VERSION 5.8 ;
BUSBITCHARS "[]" ;
DIVIDERCHAR "/" ;
UNITS
    DATABASE MICRONS 1000 ;
END UNITS

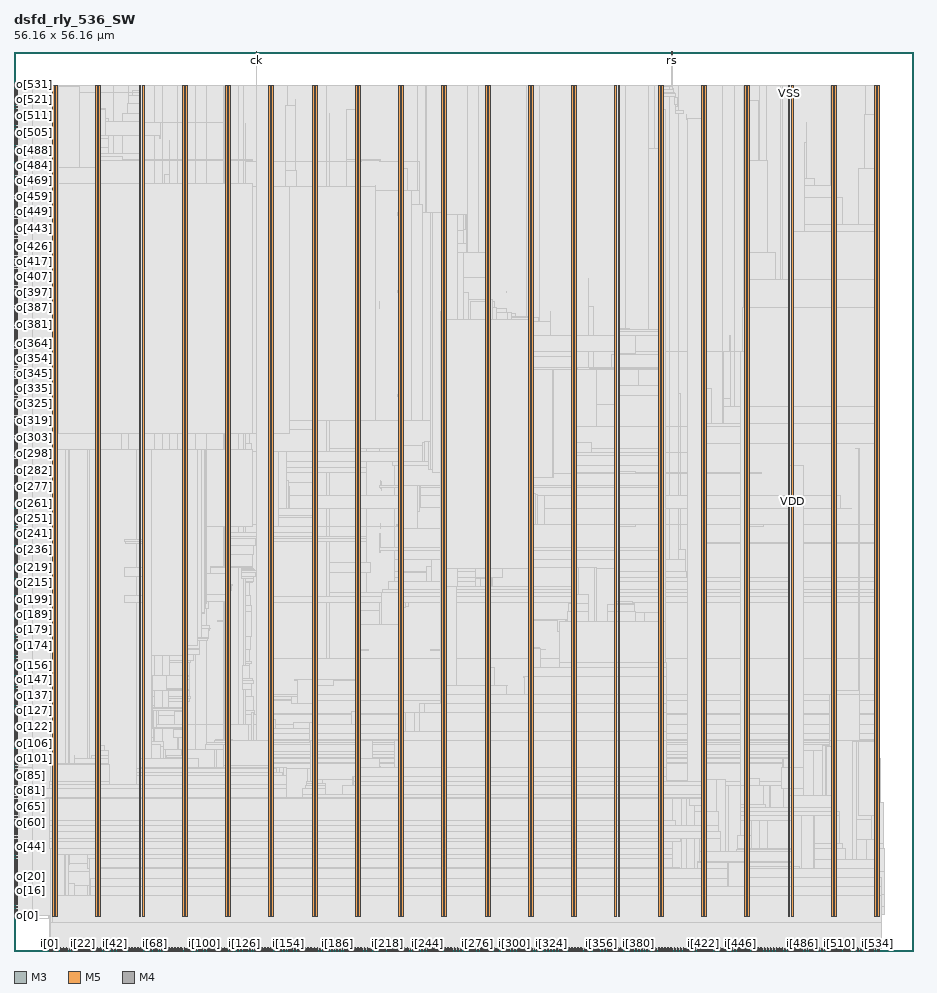
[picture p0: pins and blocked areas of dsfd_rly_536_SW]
MACRO dsfd_rly_536_SW
  FOREIGN dsfd_rly_536_SW 0 0 ;
  CLASS BLOCK ;
  SIZE 56.16 BY 56.16 ;
  PIN ck
    DIRECTION INPUT ;
    USE SIGNAL ;
    PORT
      LAYER M3 ;
        RECT  15.12 56.016 15.138 56.16 ;
    END
  END ck
  PIN i[0]
    DIRECTION INPUT ;
    USE SIGNAL ;
    PORT
      LAYER M3 ;
        RECT  2.196 0 2.214 0.144 ;
    END
  END i[0]
  PIN i[100]
    DIRECTION INPUT ;
    USE SIGNAL ;
    PORT
      LAYER M3 ;
        RECT  11.88 0 11.898 0.144 ;
    END
  END i[100]
  PIN i[101]
    DIRECTION INPUT ;
    USE SIGNAL ;
    PORT
      LAYER M5 ;
        RECT  11.952 0 11.976 0.192 ;
    END
  END i[101]
  PIN i[102]
    DIRECTION INPUT ;
    USE SIGNAL ;
    PORT
      LAYER M3 ;
        RECT  12.06 0 12.078 0.144 ;
    END
  END i[102]
  PIN i[103]
    DIRECTION INPUT ;
    USE SIGNAL ;
    PORT
      LAYER M5 ;
        RECT  12.144 0 12.168 0.192 ;
    END
  END i[103]
  PIN i[104]
    DIRECTION INPUT ;
    USE SIGNAL ;
    PORT
      LAYER M3 ;
        RECT  12.24 0 12.258 0.144 ;
    END
  END i[104]
  PIN i[105]
    DIRECTION INPUT ;
    USE SIGNAL ;
    PORT
      LAYER M5 ;
        RECT  12.336 0 12.36 0.192 ;
    END
  END i[105]
  PIN i[106]
    DIRECTION INPUT ;
    USE SIGNAL ;
    PORT
      LAYER M3 ;
        RECT  12.456 0 12.474 0.144 ;
    END
  END i[106]
  PIN i[107]
    DIRECTION INPUT ;
    USE SIGNAL ;
    PORT
      LAYER M5 ;
        RECT  12.528 0 12.552 0.192 ;
    END
  END i[107]
  PIN i[108]
    DIRECTION INPUT ;
    USE SIGNAL ;
    PORT
      LAYER M3 ;
        RECT  12.636 0 12.654 0.144 ;
    END
  END i[108]
  PIN i[109]
    DIRECTION INPUT ;
    USE SIGNAL ;
    PORT
      LAYER M5 ;
        RECT  12.72 0 12.744 0.192 ;
    END
  END i[109]
  PIN i[10]
    DIRECTION INPUT ;
    USE SIGNAL ;
    PORT
      LAYER M3 ;
        RECT  3.168 0 3.186 0.144 ;
    END
  END i[10]
  PIN i[110]
    DIRECTION INPUT ;
    USE SIGNAL ;
    PORT
      LAYER M3 ;
        RECT  12.852 0 12.87 0.144 ;
    END
  END i[110]
  PIN i[111]
    DIRECTION INPUT ;
    USE SIGNAL ;
    PORT
      LAYER M5 ;
        RECT  12.912 0 12.936 0.192 ;
    END
  END i[111]
  PIN i[112]
    DIRECTION INPUT ;
    USE SIGNAL ;
    PORT
      LAYER M3 ;
        RECT  13.032 0 13.05 0.144 ;
    END
  END i[112]
  PIN i[113]
    DIRECTION INPUT ;
    USE SIGNAL ;
    PORT
      LAYER M5 ;
        RECT  13.104 0 13.128 0.192 ;
    END
  END i[113]
  PIN i[114]
    DIRECTION INPUT ;
    USE SIGNAL ;
    PORT
      LAYER M3 ;
        RECT  13.212 0 13.23 0.144 ;
    END
  END i[114]
  PIN i[115]
    DIRECTION INPUT ;
    USE SIGNAL ;
    PORT
      LAYER M5 ;
        RECT  13.296 0 13.32 0.192 ;
    END
  END i[115]
  PIN i[116]
    DIRECTION INPUT ;
    USE SIGNAL ;
    PORT
      LAYER M3 ;
        RECT  13.428 0 13.446 0.144 ;
    END
  END i[116]
  PIN i[117]
    DIRECTION INPUT ;
    USE SIGNAL ;
    PORT
      LAYER M5 ;
        RECT  13.536 0 13.56 0.192 ;
    END
  END i[117]
  PIN i[118]
    DIRECTION INPUT ;
    USE SIGNAL ;
    PORT
      LAYER M3 ;
        RECT  13.608 0 13.626 0.144 ;
    END
  END i[118]
  PIN i[119]
    DIRECTION INPUT ;
    USE SIGNAL ;
    PORT
      LAYER M5 ;
        RECT  13.728 0 13.752 0.192 ;
    END
  END i[119]
  PIN i[11]
    DIRECTION INPUT ;
    USE SIGNAL ;
    PORT
      LAYER M5 ;
        RECT  3.264 0 3.288 0.192 ;
    END
  END i[11]
  PIN i[120]
    DIRECTION INPUT ;
    USE SIGNAL ;
    PORT
      LAYER M3 ;
        RECT  13.788 0 13.806 0.144 ;
    END
  END i[120]
  PIN i[121]
    DIRECTION INPUT ;
    USE SIGNAL ;
    PORT
      LAYER M5 ;
        RECT  13.92 0 13.944 0.192 ;
    END
  END i[121]
  PIN i[122]
    DIRECTION INPUT ;
    USE SIGNAL ;
    PORT
      LAYER M3 ;
        RECT  14.004 0 14.022 0.144 ;
    END
  END i[122]
  PIN i[123]
    DIRECTION INPUT ;
    USE SIGNAL ;
    PORT
      LAYER M5 ;
        RECT  14.112 0 14.136 0.192 ;
    END
  END i[123]
  PIN i[124]
    DIRECTION INPUT ;
    USE SIGNAL ;
    PORT
      LAYER M3 ;
        RECT  14.184 0 14.202 0.144 ;
    END
  END i[124]
  PIN i[125]
    DIRECTION INPUT ;
    USE SIGNAL ;
    PORT
      LAYER M5 ;
        RECT  14.304 0 14.328 0.192 ;
    END
  END i[125]
  PIN i[126]
    DIRECTION INPUT ;
    USE SIGNAL ;
    PORT
      LAYER M3 ;
        RECT  14.4 0 14.418 0.144 ;
    END
  END i[126]
  PIN i[127]
    DIRECTION INPUT ;
    USE SIGNAL ;
    PORT
      LAYER M5 ;
        RECT  14.496 0 14.52 0.192 ;
    END
  END i[127]
  PIN i[128]
    DIRECTION INPUT ;
    USE SIGNAL ;
    PORT
      LAYER M3 ;
        RECT  14.58 0 14.598 0.144 ;
    END
  END i[128]
  PIN i[129]
    DIRECTION INPUT ;
    USE SIGNAL ;
    PORT
      LAYER M5 ;
        RECT  14.688 0 14.712 0.192 ;
    END
  END i[129]
  PIN i[12]
    DIRECTION INPUT ;
    USE SIGNAL ;
    PORT
      LAYER M3 ;
        RECT  3.348 0 3.366 0.144 ;
    END
  END i[12]
  PIN i[130]
    DIRECTION INPUT ;
    USE SIGNAL ;
    PORT
      LAYER M3 ;
        RECT  14.76 0 14.778 0.144 ;
    END
  END i[130]
  PIN i[131]
    DIRECTION INPUT ;
    USE SIGNAL ;
    PORT
      LAYER M5 ;
        RECT  14.88 0 14.904 0.192 ;
    END
  END i[131]
  PIN i[132]
    DIRECTION INPUT ;
    USE SIGNAL ;
    PORT
      LAYER M3 ;
        RECT  14.976 0 14.994 0.144 ;
    END
  END i[132]
  PIN i[133]
    DIRECTION INPUT ;
    USE SIGNAL ;
    PORT
      LAYER M5 ;
        RECT  15.072 0 15.096 0.192 ;
    END
  END i[133]
  PIN i[134]
    DIRECTION INPUT ;
    USE SIGNAL ;
    PORT
      LAYER M3 ;
        RECT  15.156 0 15.174 0.144 ;
    END
  END i[134]
  PIN i[135]
    DIRECTION INPUT ;
    USE SIGNAL ;
    PORT
      LAYER M5 ;
        RECT  15.264 0 15.288 0.192 ;
    END
  END i[135]
  PIN i[136]
    DIRECTION INPUT ;
    USE SIGNAL ;
    PORT
      LAYER M3 ;
        RECT  15.336 0 15.354 0.144 ;
    END
  END i[136]
  PIN i[137]
    DIRECTION INPUT ;
    USE SIGNAL ;
    PORT
      LAYER M5 ;
        RECT  15.456 0 15.48 0.192 ;
    END
  END i[137]
  PIN i[138]
    DIRECTION INPUT ;
    USE SIGNAL ;
    PORT
      LAYER M3 ;
        RECT  15.552 0 15.57 0.144 ;
    END
  END i[138]
  PIN i[139]
    DIRECTION INPUT ;
    USE SIGNAL ;
    PORT
      LAYER M5 ;
        RECT  15.648 0 15.672 0.192 ;
    END
  END i[139]
  PIN i[13]
    DIRECTION INPUT ;
    USE SIGNAL ;
    PORT
      LAYER M5 ;
        RECT  3.456 0 3.48 0.192 ;
    END
  END i[13]
  PIN i[140]
    DIRECTION INPUT ;
    USE SIGNAL ;
    PORT
      LAYER M3 ;
        RECT  15.732 0 15.75 0.144 ;
    END
  END i[140]
  PIN i[141]
    DIRECTION INPUT ;
    USE SIGNAL ;
    PORT
      LAYER M5 ;
        RECT  15.84 0 15.864 0.192 ;
    END
  END i[141]
  PIN i[142]
    DIRECTION INPUT ;
    USE SIGNAL ;
    PORT
      LAYER M3 ;
        RECT  15.948 0 15.966 0.144 ;
    END
  END i[142]
  PIN i[143]
    DIRECTION INPUT ;
    USE SIGNAL ;
    PORT
      LAYER M5 ;
        RECT  16.032 0 16.056 0.192 ;
    END
  END i[143]
  PIN i[144]
    DIRECTION INPUT ;
    USE SIGNAL ;
    PORT
      LAYER M3 ;
        RECT  16.128 0 16.146 0.144 ;
    END
  END i[144]
  PIN i[145]
    DIRECTION INPUT ;
    USE SIGNAL ;
    PORT
      LAYER M5 ;
        RECT  16.224 0 16.248 0.192 ;
    END
  END i[145]
  PIN i[146]
    DIRECTION INPUT ;
    USE SIGNAL ;
    PORT
      LAYER M3 ;
        RECT  16.308 0 16.326 0.144 ;
    END
  END i[146]
  PIN i[147]
    DIRECTION INPUT ;
    USE SIGNAL ;
    PORT
      LAYER M5 ;
        RECT  16.416 0 16.44 0.192 ;
    END
  END i[147]
  PIN i[148]
    DIRECTION INPUT ;
    USE SIGNAL ;
    PORT
      LAYER M3 ;
        RECT  16.524 0 16.542 0.144 ;
    END
  END i[148]
  PIN i[149]
    DIRECTION INPUT ;
    USE SIGNAL ;
    PORT
      LAYER M5 ;
        RECT  16.608 0 16.632 0.192 ;
    END
  END i[149]
  PIN i[14]
    DIRECTION INPUT ;
    USE SIGNAL ;
    PORT
      LAYER M3 ;
        RECT  3.564 0 3.582 0.144 ;
    END
  END i[14]
  PIN i[150]
    DIRECTION INPUT ;
    USE SIGNAL ;
    PORT
      LAYER M3 ;
        RECT  16.704 0 16.722 0.144 ;
    END
  END i[150]
  PIN i[151]
    DIRECTION INPUT ;
    USE SIGNAL ;
    PORT
      LAYER M5 ;
        RECT  16.8 0 16.824 0.192 ;
    END
  END i[151]
  PIN i[152]
    DIRECTION INPUT ;
    USE SIGNAL ;
    PORT
      LAYER M3 ;
        RECT  16.884 0 16.902 0.144 ;
    END
  END i[152]
  PIN i[153]
    DIRECTION INPUT ;
    USE SIGNAL ;
    PORT
      LAYER M5 ;
        RECT  16.992 0 17.016 0.192 ;
    END
  END i[153]
  PIN i[154]
    DIRECTION INPUT ;
    USE SIGNAL ;
    PORT
      LAYER M3 ;
        RECT  17.1 0 17.118 0.144 ;
    END
  END i[154]
  PIN i[155]
    DIRECTION INPUT ;
    USE SIGNAL ;
    PORT
      LAYER M5 ;
        RECT  17.184 0 17.208 0.192 ;
    END
  END i[155]
  PIN i[156]
    DIRECTION INPUT ;
    USE SIGNAL ;
    PORT
      LAYER M3 ;
        RECT  17.28 0 17.298 0.144 ;
    END
  END i[156]
  PIN i[157]
    DIRECTION INPUT ;
    USE SIGNAL ;
    PORT
      LAYER M5 ;
        RECT  17.376 0 17.4 0.192 ;
    END
  END i[157]
  PIN i[158]
    DIRECTION INPUT ;
    USE SIGNAL ;
    PORT
      LAYER M3 ;
        RECT  17.496 0 17.514 0.144 ;
    END
  END i[158]
  PIN i[159]
    DIRECTION INPUT ;
    USE SIGNAL ;
    PORT
      LAYER M5 ;
        RECT  17.568 0 17.592 0.192 ;
    END
  END i[159]
  PIN i[15]
    DIRECTION INPUT ;
    USE SIGNAL ;
    PORT
      LAYER M5 ;
        RECT  3.648 0 3.672 0.192 ;
    END
  END i[15]
  PIN i[160]
    DIRECTION INPUT ;
    USE SIGNAL ;
    PORT
      LAYER M3 ;
        RECT  17.676 0 17.694 0.144 ;
    END
  END i[160]
  PIN i[161]
    DIRECTION INPUT ;
    USE SIGNAL ;
    PORT
      LAYER M5 ;
        RECT  17.76 0 17.784 0.192 ;
    END
  END i[161]
  PIN i[162]
    DIRECTION INPUT ;
    USE SIGNAL ;
    PORT
      LAYER M3 ;
        RECT  17.856 0 17.874 0.144 ;
    END
  END i[162]
  PIN i[163]
    DIRECTION INPUT ;
    USE SIGNAL ;
    PORT
      LAYER M5 ;
        RECT  17.952 0 17.976 0.192 ;
    END
  END i[163]
  PIN i[164]
    DIRECTION INPUT ;
    USE SIGNAL ;
    PORT
      LAYER M3 ;
        RECT  18.072 0 18.09 0.144 ;
    END
  END i[164]
  PIN i[165]
    DIRECTION INPUT ;
    USE SIGNAL ;
    PORT
      LAYER M5 ;
        RECT  18.144 0 18.168 0.192 ;
    END
  END i[165]
  PIN i[166]
    DIRECTION INPUT ;
    USE SIGNAL ;
    PORT
      LAYER M3 ;
        RECT  18.252 0 18.27 0.144 ;
    END
  END i[166]
  PIN i[167]
    DIRECTION INPUT ;
    USE SIGNAL ;
    PORT
      LAYER M5 ;
        RECT  18.336 0 18.36 0.192 ;
    END
  END i[167]
  PIN i[168]
    DIRECTION INPUT ;
    USE SIGNAL ;
    PORT
      LAYER M3 ;
        RECT  18.432 0 18.45 0.144 ;
    END
  END i[168]
  PIN i[169]
    DIRECTION INPUT ;
    USE SIGNAL ;
    PORT
      LAYER M5 ;
        RECT  18.528 0 18.552 0.192 ;
    END
  END i[169]
  PIN i[16]
    DIRECTION INPUT ;
    USE SIGNAL ;
    PORT
      LAYER M3 ;
        RECT  3.744 0 3.762 0.144 ;
    END
  END i[16]
  PIN i[170]
    DIRECTION INPUT ;
    USE SIGNAL ;
    PORT
      LAYER M3 ;
        RECT  18.648 0 18.666 0.144 ;
    END
  END i[170]
  PIN i[171]
    DIRECTION INPUT ;
    USE SIGNAL ;
    PORT
      LAYER M5 ;
        RECT  18.72 0 18.744 0.192 ;
    END
  END i[171]
  PIN i[172]
    DIRECTION INPUT ;
    USE SIGNAL ;
    PORT
      LAYER M3 ;
        RECT  18.828 0 18.846 0.144 ;
    END
  END i[172]
  PIN i[173]
    DIRECTION INPUT ;
    USE SIGNAL ;
    PORT
      LAYER M5 ;
        RECT  18.912 0 18.936 0.192 ;
    END
  END i[173]
  PIN i[174]
    DIRECTION INPUT ;
    USE SIGNAL ;
    PORT
      LAYER M3 ;
        RECT  19.044 0 19.062 0.144 ;
    END
  END i[174]
  PIN i[175]
    DIRECTION INPUT ;
    USE SIGNAL ;
    PORT
      LAYER M5 ;
        RECT  19.104 0 19.128 0.192 ;
    END
  END i[175]
  PIN i[176]
    DIRECTION INPUT ;
    USE SIGNAL ;
    PORT
      LAYER M3 ;
        RECT  19.224 0 19.242 0.144 ;
    END
  END i[176]
  PIN i[177]
    DIRECTION INPUT ;
    USE SIGNAL ;
    PORT
      LAYER M5 ;
        RECT  19.296 0 19.32 0.192 ;
    END
  END i[177]
  PIN i[178]
    DIRECTION INPUT ;
    USE SIGNAL ;
    PORT
      LAYER M3 ;
        RECT  19.404 0 19.422 0.144 ;
    END
  END i[178]
  PIN i[179]
    DIRECTION INPUT ;
    USE SIGNAL ;
    PORT
      LAYER M5 ;
        RECT  19.488 0 19.512 0.192 ;
    END
  END i[179]
  PIN i[17]
    DIRECTION INPUT ;
    USE SIGNAL ;
    PORT
      LAYER M5 ;
        RECT  3.84 0 3.864 0.192 ;
    END
  END i[17]
  PIN i[180]
    DIRECTION INPUT ;
    USE SIGNAL ;
    PORT
      LAYER M3 ;
        RECT  19.62 0 19.638 0.144 ;
    END
  END i[180]
  PIN i[181]
    DIRECTION INPUT ;
    USE SIGNAL ;
    PORT
      LAYER M5 ;
        RECT  19.68 0 19.704 0.192 ;
    END
  END i[181]
  PIN i[182]
    DIRECTION INPUT ;
    USE SIGNAL ;
    PORT
      LAYER M3 ;
        RECT  19.8 0 19.818 0.144 ;
    END
  END i[182]
  PIN i[183]
    DIRECTION INPUT ;
    USE SIGNAL ;
    PORT
      LAYER M5 ;
        RECT  19.872 0 19.896 0.192 ;
    END
  END i[183]
  PIN i[184]
    DIRECTION INPUT ;
    USE SIGNAL ;
    PORT
      LAYER M3 ;
        RECT  19.98 0 19.998 0.144 ;
    END
  END i[184]
  PIN i[185]
    DIRECTION INPUT ;
    USE SIGNAL ;
    PORT
      LAYER M5 ;
        RECT  20.112 0 20.136 0.192 ;
    END
  END i[185]
  PIN i[186]
    DIRECTION INPUT ;
    USE SIGNAL ;
    PORT
      LAYER M3 ;
        RECT  20.196 0 20.214 0.144 ;
    END
  END i[186]
  PIN i[187]
    DIRECTION INPUT ;
    USE SIGNAL ;
    PORT
      LAYER M5 ;
        RECT  20.304 0 20.328 0.192 ;
    END
  END i[187]
  PIN i[188]
    DIRECTION INPUT ;
    USE SIGNAL ;
    PORT
      LAYER M3 ;
        RECT  20.376 0 20.394 0.144 ;
    END
  END i[188]
  PIN i[189]
    DIRECTION INPUT ;
    USE SIGNAL ;
    PORT
      LAYER M5 ;
        RECT  20.496 0 20.52 0.192 ;
    END
  END i[189]
  PIN i[18]
    DIRECTION INPUT ;
    USE SIGNAL ;
    PORT
      LAYER M3 ;
        RECT  3.924 0 3.942 0.144 ;
    END
  END i[18]
  PIN i[190]
    DIRECTION INPUT ;
    USE SIGNAL ;
    PORT
      LAYER M3 ;
        RECT  20.592 0 20.61 0.144 ;
    END
  END i[190]
  PIN i[191]
    DIRECTION INPUT ;
    USE SIGNAL ;
    PORT
      LAYER M5 ;
        RECT  20.688 0 20.712 0.192 ;
    END
  END i[191]
  PIN i[192]
    DIRECTION INPUT ;
    USE SIGNAL ;
    PORT
      LAYER M3 ;
        RECT  20.772 0 20.79 0.144 ;
    END
  END i[192]
  PIN i[193]
    DIRECTION INPUT ;
    USE SIGNAL ;
    PORT
      LAYER M5 ;
        RECT  20.88 0 20.904 0.192 ;
    END
  END i[193]
  PIN i[194]
    DIRECTION INPUT ;
    USE SIGNAL ;
    PORT
      LAYER M3 ;
        RECT  20.952 0 20.97 0.144 ;
    END
  END i[194]
  PIN i[195]
    DIRECTION INPUT ;
    USE SIGNAL ;
    PORT
      LAYER M5 ;
        RECT  21.072 0 21.096 0.192 ;
    END
  END i[195]
  PIN i[196]
    DIRECTION INPUT ;
    USE SIGNAL ;
    PORT
      LAYER M3 ;
        RECT  21.168 0 21.186 0.144 ;
    END
  END i[196]
  PIN i[197]
    DIRECTION INPUT ;
    USE SIGNAL ;
    PORT
      LAYER M5 ;
        RECT  21.264 0 21.288 0.192 ;
    END
  END i[197]
  PIN i[198]
    DIRECTION INPUT ;
    USE SIGNAL ;
    PORT
      LAYER M3 ;
        RECT  21.348 0 21.366 0.144 ;
    END
  END i[198]
  PIN i[199]
    DIRECTION INPUT ;
    USE SIGNAL ;
    PORT
      LAYER M5 ;
        RECT  21.456 0 21.48 0.192 ;
    END
  END i[199]
  PIN i[19]
    DIRECTION INPUT ;
    USE SIGNAL ;
    PORT
      LAYER M5 ;
        RECT  4.032 0 4.056 0.192 ;
    END
  END i[19]
  PIN i[1]
    DIRECTION INPUT ;
    USE SIGNAL ;
    PORT
      LAYER M5 ;
        RECT  2.304 0 2.328 0.192 ;
    END
  END i[1]
  PIN i[200]
    DIRECTION INPUT ;
    USE SIGNAL ;
    PORT
      LAYER M3 ;
        RECT  21.528 0 21.546 0.144 ;
    END
  END i[200]
  PIN i[201]
    DIRECTION INPUT ;
    USE SIGNAL ;
    PORT
      LAYER M5 ;
        RECT  21.648 0 21.672 0.192 ;
    END
  END i[201]
  PIN i[202]
    DIRECTION INPUT ;
    USE SIGNAL ;
    PORT
      LAYER M3 ;
        RECT  21.744 0 21.762 0.144 ;
    END
  END i[202]
  PIN i[203]
    DIRECTION INPUT ;
    USE SIGNAL ;
    PORT
      LAYER M5 ;
        RECT  21.84 0 21.864 0.192 ;
    END
  END i[203]
  PIN i[204]
    DIRECTION INPUT ;
    USE SIGNAL ;
    PORT
      LAYER M3 ;
        RECT  21.924 0 21.942 0.144 ;
    END
  END i[204]
  PIN i[205]
    DIRECTION INPUT ;
    USE SIGNAL ;
    PORT
      LAYER M5 ;
        RECT  22.032 0 22.056 0.192 ;
    END
  END i[205]
  PIN i[206]
    DIRECTION INPUT ;
    USE SIGNAL ;
    PORT
      LAYER M3 ;
        RECT  22.14 0 22.158 0.144 ;
    END
  END i[206]
  PIN i[207]
    DIRECTION INPUT ;
    USE SIGNAL ;
    PORT
      LAYER M5 ;
        RECT  22.224 0 22.248 0.192 ;
    END
  END i[207]
  PIN i[208]
    DIRECTION INPUT ;
    USE SIGNAL ;
    PORT
      LAYER M3 ;
        RECT  22.32 0 22.338 0.144 ;
    END
  END i[208]
  PIN i[209]
    DIRECTION INPUT ;
    USE SIGNAL ;
    PORT
      LAYER M5 ;
        RECT  22.416 0 22.44 0.192 ;
    END
  END i[209]
  PIN i[20]
    DIRECTION INPUT ;
    USE SIGNAL ;
    PORT
      LAYER M3 ;
        RECT  4.14 0 4.158 0.144 ;
    END
  END i[20]
  PIN i[210]
    DIRECTION INPUT ;
    USE SIGNAL ;
    PORT
      LAYER M3 ;
        RECT  22.5 0 22.518 0.144 ;
    END
  END i[210]
  PIN i[211]
    DIRECTION INPUT ;
    USE SIGNAL ;
    PORT
      LAYER M5 ;
        RECT  22.608 0 22.632 0.192 ;
    END
  END i[211]
  PIN i[212]
    DIRECTION INPUT ;
    USE SIGNAL ;
    PORT
      LAYER M3 ;
        RECT  22.716 0 22.734 0.144 ;
    END
  END i[212]
  PIN i[213]
    DIRECTION INPUT ;
    USE SIGNAL ;
    PORT
      LAYER M5 ;
        RECT  22.8 0 22.824 0.192 ;
    END
  END i[213]
  PIN i[214]
    DIRECTION INPUT ;
    USE SIGNAL ;
    PORT
      LAYER M3 ;
        RECT  22.896 0 22.914 0.144 ;
    END
  END i[214]
  PIN i[215]
    DIRECTION INPUT ;
    USE SIGNAL ;
    PORT
      LAYER M5 ;
        RECT  22.992 0 23.016 0.192 ;
    END
  END i[215]
  PIN i[216]
    DIRECTION INPUT ;
    USE SIGNAL ;
    PORT
      LAYER M3 ;
        RECT  23.076 0 23.094 0.144 ;
    END
  END i[216]
  PIN i[217]
    DIRECTION INPUT ;
    USE SIGNAL ;
    PORT
      LAYER M5 ;
        RECT  23.184 0 23.208 0.192 ;
    END
  END i[217]
  PIN i[218]
    DIRECTION INPUT ;
    USE SIGNAL ;
    PORT
      LAYER M3 ;
        RECT  23.292 0 23.31 0.144 ;
    END
  END i[218]
  PIN i[219]
    DIRECTION INPUT ;
    USE SIGNAL ;
    PORT
      LAYER M5 ;
        RECT  23.376 0 23.4 0.192 ;
    END
  END i[219]
  PIN i[21]
    DIRECTION INPUT ;
    USE SIGNAL ;
    PORT
      LAYER M5 ;
        RECT  4.224 0 4.248 0.192 ;
    END
  END i[21]
  PIN i[220]
    DIRECTION INPUT ;
    USE SIGNAL ;
    PORT
      LAYER M3 ;
        RECT  23.472 0 23.49 0.144 ;
    END
  END i[220]
  PIN i[221]
    DIRECTION INPUT ;
    USE SIGNAL ;
    PORT
      LAYER M5 ;
        RECT  23.568 0 23.592 0.192 ;
    END
  END i[221]
  PIN i[222]
    DIRECTION INPUT ;
    USE SIGNAL ;
    PORT
      LAYER M3 ;
        RECT  23.688 0 23.706 0.144 ;
    END
  END i[222]
  PIN i[223]
    DIRECTION INPUT ;
    USE SIGNAL ;
    PORT
      LAYER M5 ;
        RECT  23.76 0 23.784 0.192 ;
    END
  END i[223]
  PIN i[224]
    DIRECTION INPUT ;
    USE SIGNAL ;
    PORT
      LAYER M3 ;
        RECT  23.868 0 23.886 0.144 ;
    END
  END i[224]
  PIN i[225]
    DIRECTION INPUT ;
    USE SIGNAL ;
    PORT
      LAYER M5 ;
        RECT  23.952 0 23.976 0.192 ;
    END
  END i[225]
  PIN i[226]
    DIRECTION INPUT ;
    USE SIGNAL ;
    PORT
      LAYER M3 ;
        RECT  24.048 0 24.066 0.144 ;
    END
  END i[226]
  PIN i[227]
    DIRECTION INPUT ;
    USE SIGNAL ;
    PORT
      LAYER M5 ;
        RECT  24.144 0 24.168 0.192 ;
    END
  END i[227]
  PIN i[228]
    DIRECTION INPUT ;
    USE SIGNAL ;
    PORT
      LAYER M3 ;
        RECT  24.264 0 24.282 0.144 ;
    END
  END i[228]
  PIN i[229]
    DIRECTION INPUT ;
    USE SIGNAL ;
    PORT
      LAYER M5 ;
        RECT  24.336 0 24.36 0.192 ;
    END
  END i[229]
  PIN i[22]
    DIRECTION INPUT ;
    USE SIGNAL ;
    PORT
      LAYER M3 ;
        RECT  4.32 0 4.338 0.144 ;
    END
  END i[22]
  PIN i[230]
    DIRECTION INPUT ;
    USE SIGNAL ;
    PORT
      LAYER M3 ;
        RECT  24.444 0 24.462 0.144 ;
    END
  END i[230]
  PIN i[231]
    DIRECTION INPUT ;
    USE SIGNAL ;
    PORT
      LAYER M5 ;
        RECT  24.528 0 24.552 0.192 ;
    END
  END i[231]
  PIN i[232]
    DIRECTION INPUT ;
    USE SIGNAL ;
    PORT
      LAYER M3 ;
        RECT  24.624 0 24.642 0.144 ;
    END
  END i[232]
  PIN i[233]
    DIRECTION INPUT ;
    USE SIGNAL ;
    PORT
      LAYER M5 ;
        RECT  24.72 0 24.744 0.192 ;
    END
  END i[233]
  PIN i[234]
    DIRECTION INPUT ;
    USE SIGNAL ;
    PORT
      LAYER M3 ;
        RECT  24.84 0 24.858 0.144 ;
    END
  END i[234]
  PIN i[235]
    DIRECTION INPUT ;
    USE SIGNAL ;
    PORT
      LAYER M5 ;
        RECT  24.912 0 24.936 0.192 ;
    END
  END i[235]
  PIN i[236]
    DIRECTION INPUT ;
    USE SIGNAL ;
    PORT
      LAYER M3 ;
        RECT  25.02 0 25.038 0.144 ;
    END
  END i[236]
  PIN i[237]
    DIRECTION INPUT ;
    USE SIGNAL ;
    PORT
      LAYER M5 ;
        RECT  25.104 0 25.128 0.192 ;
    END
  END i[237]
  PIN i[238]
    DIRECTION INPUT ;
    USE SIGNAL ;
    PORT
      LAYER M3 ;
        RECT  25.2 0 25.218 0.144 ;
    END
  END i[238]
  PIN i[239]
    DIRECTION INPUT ;
    USE SIGNAL ;
    PORT
      LAYER M5 ;
        RECT  25.296 0 25.32 0.192 ;
    END
  END i[239]
  PIN i[23]
    DIRECTION INPUT ;
    USE SIGNAL ;
    PORT
      LAYER M5 ;
        RECT  4.416 0 4.44 0.192 ;
    END
  END i[23]
  PIN i[240]
    DIRECTION INPUT ;
    USE SIGNAL ;
    PORT
      LAYER M3 ;
        RECT  25.416 0 25.434 0.144 ;
    END
  END i[240]
  PIN i[241]
    DIRECTION INPUT ;
    USE SIGNAL ;
    PORT
      LAYER M5 ;
        RECT  25.488 0 25.512 0.192 ;
    END
  END i[241]
  PIN i[242]
    DIRECTION INPUT ;
    USE SIGNAL ;
    PORT
      LAYER M3 ;
        RECT  25.596 0 25.614 0.144 ;
    END
  END i[242]
  PIN i[243]
    DIRECTION INPUT ;
    USE SIGNAL ;
    PORT
      LAYER M5 ;
        RECT  25.68 0 25.704 0.192 ;
    END
  END i[243]
  PIN i[244]
    DIRECTION INPUT ;
    USE SIGNAL ;
    PORT
      LAYER M3 ;
        RECT  25.812 0 25.83 0.144 ;
    END
  END i[244]
  PIN i[245]
    DIRECTION INPUT ;
    USE SIGNAL ;
    PORT
      LAYER M5 ;
        RECT  25.872 0 25.896 0.192 ;
    END
  END i[245]
  PIN i[246]
    DIRECTION INPUT ;
    USE SIGNAL ;
    PORT
      LAYER M3 ;
        RECT  25.992 0 26.01 0.144 ;
    END
  END i[246]
  PIN i[247]
    DIRECTION INPUT ;
    USE SIGNAL ;
    PORT
      LAYER M5 ;
        RECT  26.064 0 26.088 0.192 ;
    END
  END i[247]
  PIN i[248]
    DIRECTION INPUT ;
    USE SIGNAL ;
    PORT
      LAYER M3 ;
        RECT  26.172 0 26.19 0.144 ;
    END
  END i[248]
  PIN i[249]
    DIRECTION INPUT ;
    USE SIGNAL ;
    PORT
      LAYER M5 ;
        RECT  26.256 0 26.28 0.192 ;
    END
  END i[249]
  PIN i[24]
    DIRECTION INPUT ;
    USE SIGNAL ;
    PORT
      LAYER M3 ;
        RECT  4.536 0 4.554 0.144 ;
    END
  END i[24]
  PIN i[250]
    DIRECTION INPUT ;
    USE SIGNAL ;
    PORT
      LAYER M3 ;
        RECT  26.388 0 26.406 0.144 ;
    END
  END i[250]
  PIN i[251]
    DIRECTION INPUT ;
    USE SIGNAL ;
    PORT
      LAYER M5 ;
        RECT  26.496 0 26.52 0.192 ;
    END
  END i[251]
  PIN i[252]
    DIRECTION INPUT ;
    USE SIGNAL ;
    PORT
      LAYER M3 ;
        RECT  26.568 0 26.586 0.144 ;
    END
  END i[252]
  PIN i[253]
    DIRECTION INPUT ;
    USE SIGNAL ;
    PORT
      LAYER M5 ;
        RECT  26.688 0 26.712 0.192 ;
    END
  END i[253]
  PIN i[254]
    DIRECTION INPUT ;
    USE SIGNAL ;
    PORT
      LAYER M3 ;
        RECT  26.748 0 26.766 0.144 ;
    END
  END i[254]
  PIN i[255]
    DIRECTION INPUT ;
    USE SIGNAL ;
    PORT
      LAYER M5 ;
        RECT  26.88 0 26.904 0.192 ;
    END
  END i[255]
  PIN i[256]
    DIRECTION INPUT ;
    USE SIGNAL ;
    PORT
      LAYER M3 ;
        RECT  26.964 0 26.982 0.144 ;
    END
  END i[256]
  PIN i[257]
    DIRECTION INPUT ;
    USE SIGNAL ;
    PORT
      LAYER M5 ;
        RECT  27.072 0 27.096 0.192 ;
    END
  END i[257]
  PIN i[258]
    DIRECTION INPUT ;
    USE SIGNAL ;
    PORT
      LAYER M3 ;
        RECT  27.144 0 27.162 0.144 ;
    END
  END i[258]
  PIN i[259]
    DIRECTION INPUT ;
    USE SIGNAL ;
    PORT
      LAYER M5 ;
        RECT  27.264 0 27.288 0.192 ;
    END
  END i[259]
  PIN i[25]
    DIRECTION INPUT ;
    USE SIGNAL ;
    PORT
      LAYER M5 ;
        RECT  4.608 0 4.632 0.192 ;
    END
  END i[25]
  PIN i[260]
    DIRECTION INPUT ;
    USE SIGNAL ;
    PORT
      LAYER M3 ;
        RECT  27.36 0 27.378 0.144 ;
    END
  END i[260]
  PIN i[261]
    DIRECTION INPUT ;
    USE SIGNAL ;
    PORT
      LAYER M5 ;
        RECT  27.456 0 27.48 0.192 ;
    END
  END i[261]
  PIN i[262]
    DIRECTION INPUT ;
    USE SIGNAL ;
    PORT
      LAYER M3 ;
        RECT  27.54 0 27.558 0.144 ;
    END
  END i[262]
  PIN i[263]
    DIRECTION INPUT ;
    USE SIGNAL ;
    PORT
      LAYER M5 ;
        RECT  27.648 0 27.672 0.192 ;
    END
  END i[263]
  PIN i[264]
    DIRECTION INPUT ;
    USE SIGNAL ;
    PORT
      LAYER M3 ;
        RECT  27.72 0 27.738 0.144 ;
    END
  END i[264]
  PIN i[265]
    DIRECTION INPUT ;
    USE SIGNAL ;
    PORT
      LAYER M5 ;
        RECT  27.84 0 27.864 0.192 ;
    END
  END i[265]
  PIN i[266]
    DIRECTION INPUT ;
    USE SIGNAL ;
    PORT
      LAYER M3 ;
        RECT  27.936 0 27.954 0.144 ;
    END
  END i[266]
  PIN i[267]
    DIRECTION INPUT ;
    USE SIGNAL ;
    PORT
      LAYER M5 ;
        RECT  28.032 0 28.056 0.192 ;
    END
  END i[267]
  PIN i[268]
    DIRECTION INPUT ;
    USE SIGNAL ;
    PORT
      LAYER M3 ;
        RECT  28.116 0 28.134 0.144 ;
    END
  END i[268]
  PIN i[269]
    DIRECTION INPUT ;
    USE SIGNAL ;
    PORT
      LAYER M5 ;
        RECT  28.224 0 28.248 0.192 ;
    END
  END i[269]
  PIN i[26]
    DIRECTION INPUT ;
    USE SIGNAL ;
    PORT
      LAYER M3 ;
        RECT  4.716 0 4.734 0.144 ;
    END
  END i[26]
  PIN i[270]
    DIRECTION INPUT ;
    USE SIGNAL ;
    PORT
      LAYER M3 ;
        RECT  28.296 0 28.314 0.144 ;
    END
  END i[270]
  PIN i[271]
    DIRECTION INPUT ;
    USE SIGNAL ;
    PORT
      LAYER M5 ;
        RECT  28.416 0 28.44 0.192 ;
    END
  END i[271]
  PIN i[272]
    DIRECTION INPUT ;
    USE SIGNAL ;
    PORT
      LAYER M3 ;
        RECT  28.512 0 28.53 0.144 ;
    END
  END i[272]
  PIN i[273]
    DIRECTION INPUT ;
    USE SIGNAL ;
    PORT
      LAYER M5 ;
        RECT  28.608 0 28.632 0.192 ;
    END
  END i[273]
  PIN i[274]
    DIRECTION INPUT ;
    USE SIGNAL ;
    PORT
      LAYER M3 ;
        RECT  28.692 0 28.71 0.144 ;
    END
  END i[274]
  PIN i[275]
    DIRECTION INPUT ;
    USE SIGNAL ;
    PORT
      LAYER M5 ;
        RECT  28.8 0 28.824 0.192 ;
    END
  END i[275]
  PIN i[276]
    DIRECTION INPUT ;
    USE SIGNAL ;
    PORT
      LAYER M3 ;
        RECT  28.908 0 28.926 0.144 ;
    END
  END i[276]
  PIN i[277]
    DIRECTION INPUT ;
    USE SIGNAL ;
    PORT
      LAYER M5 ;
        RECT  28.992 0 29.016 0.192 ;
    END
  END i[277]
  PIN i[278]
    DIRECTION INPUT ;
    USE SIGNAL ;
    PORT
      LAYER M3 ;
        RECT  29.088 0 29.106 0.144 ;
    END
  END i[278]
  PIN i[279]
    DIRECTION INPUT ;
    USE SIGNAL ;
    PORT
      LAYER M5 ;
        RECT  29.184 0 29.208 0.192 ;
    END
  END i[279]
  PIN i[27]
    DIRECTION INPUT ;
    USE SIGNAL ;
    PORT
      LAYER M5 ;
        RECT  4.8 0 4.824 0.192 ;
    END
  END i[27]
  PIN i[280]
    DIRECTION INPUT ;
    USE SIGNAL ;
    PORT
      LAYER M3 ;
        RECT  29.268 0 29.286 0.144 ;
    END
  END i[280]
  PIN i[281]
    DIRECTION INPUT ;
    USE SIGNAL ;
    PORT
      LAYER M5 ;
        RECT  29.376 0 29.4 0.192 ;
    END
  END i[281]
  PIN i[282]
    DIRECTION INPUT ;
    USE SIGNAL ;
    PORT
      LAYER M3 ;
        RECT  29.484 0 29.502 0.144 ;
    END
  END i[282]
  PIN i[283]
    DIRECTION INPUT ;
    USE SIGNAL ;
    PORT
      LAYER M5 ;
        RECT  29.568 0 29.592 0.192 ;
    END
  END i[283]
  PIN i[284]
    DIRECTION INPUT ;
    USE SIGNAL ;
    PORT
      LAYER M3 ;
        RECT  29.664 0 29.682 0.144 ;
    END
  END i[284]
  PIN i[285]
    DIRECTION INPUT ;
    USE SIGNAL ;
    PORT
      LAYER M5 ;
        RECT  29.76 0 29.784 0.192 ;
    END
  END i[285]
  PIN i[286]
    DIRECTION INPUT ;
    USE SIGNAL ;
    PORT
      LAYER M3 ;
        RECT  29.844 0 29.862 0.144 ;
    END
  END i[286]
  PIN i[287]
    DIRECTION INPUT ;
    USE SIGNAL ;
    PORT
      LAYER M5 ;
        RECT  29.952 0 29.976 0.192 ;
    END
  END i[287]
  PIN i[288]
    DIRECTION INPUT ;
    USE SIGNAL ;
    PORT
      LAYER M3 ;
        RECT  30.06 0 30.078 0.144 ;
    END
  END i[288]
  PIN i[289]
    DIRECTION INPUT ;
    USE SIGNAL ;
    PORT
      LAYER M5 ;
        RECT  30.144 0 30.168 0.192 ;
    END
  END i[289]
  PIN i[28]
    DIRECTION INPUT ;
    USE SIGNAL ;
    PORT
      LAYER M3 ;
        RECT  4.896 0 4.914 0.144 ;
    END
  END i[28]
  PIN i[290]
    DIRECTION INPUT ;
    USE SIGNAL ;
    PORT
      LAYER M3 ;
        RECT  30.24 0 30.258 0.144 ;
    END
  END i[290]
  PIN i[291]
    DIRECTION INPUT ;
    USE SIGNAL ;
    PORT
      LAYER M5 ;
        RECT  30.336 0 30.36 0.192 ;
    END
  END i[291]
  PIN i[292]
    DIRECTION INPUT ;
    USE SIGNAL ;
    PORT
      LAYER M3 ;
        RECT  30.456 0 30.474 0.144 ;
    END
  END i[292]
  PIN i[293]
    DIRECTION INPUT ;
    USE SIGNAL ;
    PORT
      LAYER M5 ;
        RECT  30.528 0 30.552 0.192 ;
    END
  END i[293]
  PIN i[294]
    DIRECTION INPUT ;
    USE SIGNAL ;
    PORT
      LAYER M3 ;
        RECT  30.636 0 30.654 0.144 ;
    END
  END i[294]
  PIN i[295]
    DIRECTION INPUT ;
    USE SIGNAL ;
    PORT
      LAYER M5 ;
        RECT  30.72 0 30.744 0.192 ;
    END
  END i[295]
  PIN i[296]
    DIRECTION INPUT ;
    USE SIGNAL ;
    PORT
      LAYER M3 ;
        RECT  30.816 0 30.834 0.144 ;
    END
  END i[296]
  PIN i[297]
    DIRECTION INPUT ;
    USE SIGNAL ;
    PORT
      LAYER M5 ;
        RECT  30.912 0 30.936 0.192 ;
    END
  END i[297]
  PIN i[298]
    DIRECTION INPUT ;
    USE SIGNAL ;
    PORT
      LAYER M3 ;
        RECT  31.032 0 31.05 0.144 ;
    END
  END i[298]
  PIN i[299]
    DIRECTION INPUT ;
    USE SIGNAL ;
    PORT
      LAYER M5 ;
        RECT  31.104 0 31.128 0.192 ;
    END
  END i[299]
  PIN i[29]
    DIRECTION INPUT ;
    USE SIGNAL ;
    PORT
      LAYER M5 ;
        RECT  4.992 0 5.016 0.192 ;
    END
  END i[29]
  PIN i[2]
    DIRECTION INPUT ;
    USE SIGNAL ;
    PORT
      LAYER M3 ;
        RECT  2.376 0 2.394 0.144 ;
    END
  END i[2]
  PIN i[300]
    DIRECTION INPUT ;
    USE SIGNAL ;
    PORT
      LAYER M3 ;
        RECT  31.212 0 31.23 0.144 ;
    END
  END i[300]
  PIN i[301]
    DIRECTION INPUT ;
    USE SIGNAL ;
    PORT
      LAYER M5 ;
        RECT  31.296 0 31.32 0.192 ;
    END
  END i[301]
  PIN i[302]
    DIRECTION INPUT ;
    USE SIGNAL ;
    PORT
      LAYER M3 ;
        RECT  31.392 0 31.41 0.144 ;
    END
  END i[302]
  PIN i[303]
    DIRECTION INPUT ;
    USE SIGNAL ;
    PORT
      LAYER M5 ;
        RECT  31.488 0 31.512 0.192 ;
    END
  END i[303]
  PIN i[304]
    DIRECTION INPUT ;
    USE SIGNAL ;
    PORT
      LAYER M3 ;
        RECT  31.608 0 31.626 0.144 ;
    END
  END i[304]
  PIN i[305]
    DIRECTION INPUT ;
    USE SIGNAL ;
    PORT
      LAYER M5 ;
        RECT  31.68 0 31.704 0.192 ;
    END
  END i[305]
  PIN i[306]
    DIRECTION INPUT ;
    USE SIGNAL ;
    PORT
      LAYER M3 ;
        RECT  31.788 0 31.806 0.144 ;
    END
  END i[306]
  PIN i[307]
    DIRECTION INPUT ;
    USE SIGNAL ;
    PORT
      LAYER M5 ;
        RECT  31.872 0 31.896 0.192 ;
    END
  END i[307]
  PIN i[308]
    DIRECTION INPUT ;
    USE SIGNAL ;
    PORT
      LAYER M3 ;
        RECT  32.004 0 32.022 0.144 ;
    END
  END i[308]
  PIN i[309]
    DIRECTION INPUT ;
    USE SIGNAL ;
    PORT
      LAYER M5 ;
        RECT  32.064 0 32.088 0.192 ;
    END
  END i[309]
  PIN i[30]
    DIRECTION INPUT ;
    USE SIGNAL ;
    PORT
      LAYER M3 ;
        RECT  5.112 0 5.13 0.144 ;
    END
  END i[30]
  PIN i[310]
    DIRECTION INPUT ;
    USE SIGNAL ;
    PORT
      LAYER M3 ;
        RECT  32.184 0 32.202 0.144 ;
    END
  END i[310]
  PIN i[311]
    DIRECTION INPUT ;
    USE SIGNAL ;
    PORT
      LAYER M5 ;
        RECT  32.256 0 32.28 0.192 ;
    END
  END i[311]
  PIN i[312]
    DIRECTION INPUT ;
    USE SIGNAL ;
    PORT
      LAYER M3 ;
        RECT  32.364 0 32.382 0.144 ;
    END
  END i[312]
  PIN i[313]
    DIRECTION INPUT ;
    USE SIGNAL ;
    PORT
      LAYER M5 ;
        RECT  32.448 0 32.472 0.192 ;
    END
  END i[313]
  PIN i[314]
    DIRECTION INPUT ;
    USE SIGNAL ;
    PORT
      LAYER M3 ;
        RECT  32.58 0 32.598 0.144 ;
    END
  END i[314]
  PIN i[315]
    DIRECTION INPUT ;
    USE SIGNAL ;
    PORT
      LAYER M5 ;
        RECT  32.64 0 32.664 0.192 ;
    END
  END i[315]
  PIN i[316]
    DIRECTION INPUT ;
    USE SIGNAL ;
    PORT
      LAYER M3 ;
        RECT  32.76 0 32.778 0.144 ;
    END
  END i[316]
  PIN i[317]
    DIRECTION INPUT ;
    USE SIGNAL ;
    PORT
      LAYER M5 ;
        RECT  32.832 0 32.856 0.192 ;
    END
  END i[317]
  PIN i[318]
    DIRECTION INPUT ;
    USE SIGNAL ;
    PORT
      LAYER M3 ;
        RECT  32.94 0 32.958 0.144 ;
    END
  END i[318]
  PIN i[319]
    DIRECTION INPUT ;
    USE SIGNAL ;
    PORT
      LAYER M5 ;
        RECT  33.072 0 33.096 0.192 ;
    END
  END i[319]
  PIN i[31]
    DIRECTION INPUT ;
    USE SIGNAL ;
    PORT
      LAYER M5 ;
        RECT  5.184 0 5.208 0.192 ;
    END
  END i[31]
  PIN i[320]
    DIRECTION INPUT ;
    USE SIGNAL ;
    PORT
      LAYER M3 ;
        RECT  33.156 0 33.174 0.144 ;
    END
  END i[320]
  PIN i[321]
    DIRECTION INPUT ;
    USE SIGNAL ;
    PORT
      LAYER M5 ;
        RECT  33.264 0 33.288 0.192 ;
    END
  END i[321]
  PIN i[322]
    DIRECTION INPUT ;
    USE SIGNAL ;
    PORT
      LAYER M3 ;
        RECT  33.336 0 33.354 0.144 ;
    END
  END i[322]
  PIN i[323]
    DIRECTION INPUT ;
    USE SIGNAL ;
    PORT
      LAYER M5 ;
        RECT  33.456 0 33.48 0.192 ;
    END
  END i[323]
  PIN i[324]
    DIRECTION INPUT ;
    USE SIGNAL ;
    PORT
      LAYER M3 ;
        RECT  33.552 0 33.57 0.144 ;
    END
  END i[324]
  PIN i[325]
    DIRECTION INPUT ;
    USE SIGNAL ;
    PORT
      LAYER M5 ;
        RECT  33.648 0 33.672 0.192 ;
    END
  END i[325]
  PIN i[326]
    DIRECTION INPUT ;
    USE SIGNAL ;
    PORT
      LAYER M3 ;
        RECT  33.732 0 33.75 0.144 ;
    END
  END i[326]
  PIN i[327]
    DIRECTION INPUT ;
    USE SIGNAL ;
    PORT
      LAYER M5 ;
        RECT  33.84 0 33.864 0.192 ;
    END
  END i[327]
  PIN i[328]
    DIRECTION INPUT ;
    USE SIGNAL ;
    PORT
      LAYER M3 ;
        RECT  33.912 0 33.93 0.144 ;
    END
  END i[328]
  PIN i[329]
    DIRECTION INPUT ;
    USE SIGNAL ;
    PORT
      LAYER M5 ;
        RECT  34.032 0 34.056 0.192 ;
    END
  END i[329]
  PIN i[32]
    DIRECTION INPUT ;
    USE SIGNAL ;
    PORT
      LAYER M3 ;
        RECT  5.292 0 5.31 0.144 ;
    END
  END i[32]
  PIN i[330]
    DIRECTION INPUT ;
    USE SIGNAL ;
    PORT
      LAYER M3 ;
        RECT  34.128 0 34.146 0.144 ;
    END
  END i[330]
  PIN i[331]
    DIRECTION INPUT ;
    USE SIGNAL ;
    PORT
      LAYER M5 ;
        RECT  34.224 0 34.248 0.192 ;
    END
  END i[331]
  PIN i[332]
    DIRECTION INPUT ;
    USE SIGNAL ;
    PORT
      LAYER M3 ;
        RECT  34.308 0 34.326 0.144 ;
    END
  END i[332]
  PIN i[333]
    DIRECTION INPUT ;
    USE SIGNAL ;
    PORT
      LAYER M5 ;
        RECT  34.416 0 34.44 0.192 ;
    END
  END i[333]
  PIN i[334]
    DIRECTION INPUT ;
    USE SIGNAL ;
    PORT
      LAYER M3 ;
        RECT  34.488 0 34.506 0.144 ;
    END
  END i[334]
  PIN i[335]
    DIRECTION INPUT ;
    USE SIGNAL ;
    PORT
      LAYER M5 ;
        RECT  34.608 0 34.632 0.192 ;
    END
  END i[335]
  PIN i[336]
    DIRECTION INPUT ;
    USE SIGNAL ;
    PORT
      LAYER M3 ;
        RECT  34.704 0 34.722 0.144 ;
    END
  END i[336]
  PIN i[337]
    DIRECTION INPUT ;
    USE SIGNAL ;
    PORT
      LAYER M5 ;
        RECT  34.8 0 34.824 0.192 ;
    END
  END i[337]
  PIN i[338]
    DIRECTION INPUT ;
    USE SIGNAL ;
    PORT
      LAYER M3 ;
        RECT  34.884 0 34.902 0.144 ;
    END
  END i[338]
  PIN i[339]
    DIRECTION INPUT ;
    USE SIGNAL ;
    PORT
      LAYER M5 ;
        RECT  34.992 0 35.016 0.192 ;
    END
  END i[339]
  PIN i[33]
    DIRECTION INPUT ;
    USE SIGNAL ;
    PORT
      LAYER M5 ;
        RECT  5.376 0 5.4 0.192 ;
    END
  END i[33]
  PIN i[340]
    DIRECTION INPUT ;
    USE SIGNAL ;
    PORT
      LAYER M3 ;
        RECT  35.1 0 35.118 0.144 ;
    END
  END i[340]
  PIN i[341]
    DIRECTION INPUT ;
    USE SIGNAL ;
    PORT
      LAYER M5 ;
        RECT  35.184 0 35.208 0.192 ;
    END
  END i[341]
  PIN i[342]
    DIRECTION INPUT ;
    USE SIGNAL ;
    PORT
      LAYER M3 ;
        RECT  35.28 0 35.298 0.144 ;
    END
  END i[342]
  PIN i[343]
    DIRECTION INPUT ;
    USE SIGNAL ;
    PORT
      LAYER M5 ;
        RECT  35.376 0 35.4 0.192 ;
    END
  END i[343]
  PIN i[344]
    DIRECTION INPUT ;
    USE SIGNAL ;
    PORT
      LAYER M3 ;
        RECT  35.46 0 35.478 0.144 ;
    END
  END i[344]
  PIN i[345]
    DIRECTION INPUT ;
    USE SIGNAL ;
    PORT
      LAYER M5 ;
        RECT  35.568 0 35.592 0.192 ;
    END
  END i[345]
  PIN i[346]
    DIRECTION INPUT ;
    USE SIGNAL ;
    PORT
      LAYER M3 ;
        RECT  35.676 0 35.694 0.144 ;
    END
  END i[346]
  PIN i[347]
    DIRECTION INPUT ;
    USE SIGNAL ;
    PORT
      LAYER M5 ;
        RECT  35.76 0 35.784 0.192 ;
    END
  END i[347]
  PIN i[348]
    DIRECTION INPUT ;
    USE SIGNAL ;
    PORT
      LAYER M3 ;
        RECT  35.856 0 35.874 0.144 ;
    END
  END i[348]
  PIN i[349]
    DIRECTION INPUT ;
    USE SIGNAL ;
    PORT
      LAYER M5 ;
        RECT  35.952 0 35.976 0.192 ;
    END
  END i[349]
  PIN i[34]
    DIRECTION INPUT ;
    USE SIGNAL ;
    PORT
      LAYER M3 ;
        RECT  5.472 0 5.49 0.144 ;
    END
  END i[34]
  PIN i[350]
    DIRECTION INPUT ;
    USE SIGNAL ;
    PORT
      LAYER M3 ;
        RECT  36.036 0 36.054 0.144 ;
    END
  END i[350]
  PIN i[351]
    DIRECTION INPUT ;
    USE SIGNAL ;
    PORT
      LAYER M5 ;
        RECT  36.144 0 36.168 0.192 ;
    END
  END i[351]
  PIN i[352]
    DIRECTION INPUT ;
    USE SIGNAL ;
    PORT
      LAYER M3 ;
        RECT  36.252 0 36.27 0.144 ;
    END
  END i[352]
  PIN i[353]
    DIRECTION INPUT ;
    USE SIGNAL ;
    PORT
      LAYER M5 ;
        RECT  36.336 0 36.36 0.192 ;
    END
  END i[353]
  PIN i[354]
    DIRECTION INPUT ;
    USE SIGNAL ;
    PORT
      LAYER M3 ;
        RECT  36.432 0 36.45 0.144 ;
    END
  END i[354]
  PIN i[355]
    DIRECTION INPUT ;
    USE SIGNAL ;
    PORT
      LAYER M5 ;
        RECT  36.528 0 36.552 0.192 ;
    END
  END i[355]
  PIN i[356]
    DIRECTION INPUT ;
    USE SIGNAL ;
    PORT
      LAYER M3 ;
        RECT  36.648 0 36.666 0.144 ;
    END
  END i[356]
  PIN i[357]
    DIRECTION INPUT ;
    USE SIGNAL ;
    PORT
      LAYER M5 ;
        RECT  36.72 0 36.744 0.192 ;
    END
  END i[357]
  PIN i[358]
    DIRECTION INPUT ;
    USE SIGNAL ;
    PORT
      LAYER M3 ;
        RECT  36.828 0 36.846 0.144 ;
    END
  END i[358]
  PIN i[359]
    DIRECTION INPUT ;
    USE SIGNAL ;
    PORT
      LAYER M5 ;
        RECT  36.912 0 36.936 0.192 ;
    END
  END i[359]
  PIN i[35]
    DIRECTION INPUT ;
    USE SIGNAL ;
    PORT
      LAYER M5 ;
        RECT  5.568 0 5.592 0.192 ;
    END
  END i[35]
  PIN i[360]
    DIRECTION INPUT ;
    USE SIGNAL ;
    PORT
      LAYER M3 ;
        RECT  37.008 0 37.026 0.144 ;
    END
  END i[360]
  PIN i[361]
    DIRECTION INPUT ;
    USE SIGNAL ;
    PORT
      LAYER M5 ;
        RECT  37.104 0 37.128 0.192 ;
    END
  END i[361]
  PIN i[362]
    DIRECTION INPUT ;
    USE SIGNAL ;
    PORT
      LAYER M3 ;
        RECT  37.224 0 37.242 0.144 ;
    END
  END i[362]
  PIN i[363]
    DIRECTION INPUT ;
    USE SIGNAL ;
    PORT
      LAYER M5 ;
        RECT  37.296 0 37.32 0.192 ;
    END
  END i[363]
  PIN i[364]
    DIRECTION INPUT ;
    USE SIGNAL ;
    PORT
      LAYER M3 ;
        RECT  37.404 0 37.422 0.144 ;
    END
  END i[364]
  PIN i[365]
    DIRECTION INPUT ;
    USE SIGNAL ;
    PORT
      LAYER M5 ;
        RECT  37.488 0 37.512 0.192 ;
    END
  END i[365]
  PIN i[366]
    DIRECTION INPUT ;
    USE SIGNAL ;
    PORT
      LAYER M3 ;
        RECT  37.584 0 37.602 0.144 ;
    END
  END i[366]
  PIN i[367]
    DIRECTION INPUT ;
    USE SIGNAL ;
    PORT
      LAYER M5 ;
        RECT  37.68 0 37.704 0.192 ;
    END
  END i[367]
  PIN i[368]
    DIRECTION INPUT ;
    USE SIGNAL ;
    PORT
      LAYER M3 ;
        RECT  37.8 0 37.818 0.144 ;
    END
  END i[368]
  PIN i[369]
    DIRECTION INPUT ;
    USE SIGNAL ;
    PORT
      LAYER M5 ;
        RECT  37.872 0 37.896 0.192 ;
    END
  END i[369]
  PIN i[36]
    DIRECTION INPUT ;
    USE SIGNAL ;
    PORT
      LAYER M3 ;
        RECT  5.688 0 5.706 0.144 ;
    END
  END i[36]
  PIN i[370]
    DIRECTION INPUT ;
    USE SIGNAL ;
    PORT
      LAYER M3 ;
        RECT  37.98 0 37.998 0.144 ;
    END
  END i[370]
  PIN i[371]
    DIRECTION INPUT ;
    USE SIGNAL ;
    PORT
      LAYER M5 ;
        RECT  38.064 0 38.088 0.192 ;
    END
  END i[371]
  PIN i[372]
    DIRECTION INPUT ;
    USE SIGNAL ;
    PORT
      LAYER M3 ;
        RECT  38.16 0 38.178 0.144 ;
    END
  END i[372]
  PIN i[373]
    DIRECTION INPUT ;
    USE SIGNAL ;
    PORT
      LAYER M5 ;
        RECT  38.256 0 38.28 0.192 ;
    END
  END i[373]
  PIN i[374]
    DIRECTION INPUT ;
    USE SIGNAL ;
    PORT
      LAYER M3 ;
        RECT  38.376 0 38.394 0.144 ;
    END
  END i[374]
  PIN i[375]
    DIRECTION INPUT ;
    USE SIGNAL ;
    PORT
      LAYER M5 ;
        RECT  38.448 0 38.472 0.192 ;
    END
  END i[375]
  PIN i[376]
    DIRECTION INPUT ;
    USE SIGNAL ;
    PORT
      LAYER M3 ;
        RECT  38.556 0 38.574 0.144 ;
    END
  END i[376]
  PIN i[377]
    DIRECTION INPUT ;
    USE SIGNAL ;
    PORT
      LAYER M5 ;
        RECT  38.64 0 38.664 0.192 ;
    END
  END i[377]
  PIN i[378]
    DIRECTION INPUT ;
    USE SIGNAL ;
    PORT
      LAYER M3 ;
        RECT  38.772 0 38.79 0.144 ;
    END
  END i[378]
  PIN i[379]
    DIRECTION INPUT ;
    USE SIGNAL ;
    PORT
      LAYER M5 ;
        RECT  38.832 0 38.856 0.192 ;
    END
  END i[379]
  PIN i[37]
    DIRECTION INPUT ;
    USE SIGNAL ;
    PORT
      LAYER M5 ;
        RECT  5.76 0 5.784 0.192 ;
    END
  END i[37]
  PIN i[380]
    DIRECTION INPUT ;
    USE SIGNAL ;
    PORT
      LAYER M3 ;
        RECT  38.952 0 38.97 0.144 ;
    END
  END i[380]
  PIN i[381]
    DIRECTION INPUT ;
    USE SIGNAL ;
    PORT
      LAYER M5 ;
        RECT  39.024 0 39.048 0.192 ;
    END
  END i[381]
  PIN i[382]
    DIRECTION INPUT ;
    USE SIGNAL ;
    PORT
      LAYER M3 ;
        RECT  39.132 0 39.15 0.144 ;
    END
  END i[382]
  PIN i[383]
    DIRECTION INPUT ;
    USE SIGNAL ;
    PORT
      LAYER M5 ;
        RECT  39.216 0 39.24 0.192 ;
    END
  END i[383]
  PIN i[384]
    DIRECTION INPUT ;
    USE SIGNAL ;
    PORT
      LAYER M3 ;
        RECT  39.348 0 39.366 0.144 ;
    END
  END i[384]
  PIN i[385]
    DIRECTION INPUT ;
    USE SIGNAL ;
    PORT
      LAYER M5 ;
        RECT  39.456 0 39.48 0.192 ;
    END
  END i[385]
  PIN i[386]
    DIRECTION INPUT ;
    USE SIGNAL ;
    PORT
      LAYER M3 ;
        RECT  39.528 0 39.546 0.144 ;
    END
  END i[386]
  PIN i[387]
    DIRECTION INPUT ;
    USE SIGNAL ;
    PORT
      LAYER M5 ;
        RECT  39.648 0 39.672 0.192 ;
    END
  END i[387]
  PIN i[388]
    DIRECTION INPUT ;
    USE SIGNAL ;
    PORT
      LAYER M3 ;
        RECT  39.708 0 39.726 0.144 ;
    END
  END i[388]
  PIN i[389]
    DIRECTION INPUT ;
    USE SIGNAL ;
    PORT
      LAYER M5 ;
        RECT  39.84 0 39.864 0.192 ;
    END
  END i[389]
  PIN i[38]
    DIRECTION INPUT ;
    USE SIGNAL ;
    PORT
      LAYER M3 ;
        RECT  5.868 0 5.886 0.144 ;
    END
  END i[38]
  PIN i[390]
    DIRECTION INPUT ;
    USE SIGNAL ;
    PORT
      LAYER M3 ;
        RECT  39.924 0 39.942 0.144 ;
    END
  END i[390]
  PIN i[391]
    DIRECTION INPUT ;
    USE SIGNAL ;
    PORT
      LAYER M5 ;
        RECT  40.032 0 40.056 0.192 ;
    END
  END i[391]
  PIN i[392]
    DIRECTION INPUT ;
    USE SIGNAL ;
    PORT
      LAYER M3 ;
        RECT  40.104 0 40.122 0.144 ;
    END
  END i[392]
  PIN i[393]
    DIRECTION INPUT ;
    USE SIGNAL ;
    PORT
      LAYER M5 ;
        RECT  40.224 0 40.248 0.192 ;
    END
  END i[393]
  PIN i[394]
    DIRECTION INPUT ;
    USE SIGNAL ;
    PORT
      LAYER M3 ;
        RECT  40.32 0 40.338 0.144 ;
    END
  END i[394]
  PIN i[395]
    DIRECTION INPUT ;
    USE SIGNAL ;
    PORT
      LAYER M5 ;
        RECT  40.416 0 40.44 0.192 ;
    END
  END i[395]
  PIN i[396]
    DIRECTION INPUT ;
    USE SIGNAL ;
    PORT
      LAYER M3 ;
        RECT  40.5 0 40.518 0.144 ;
    END
  END i[396]
  PIN i[397]
    DIRECTION INPUT ;
    USE SIGNAL ;
    PORT
      LAYER M5 ;
        RECT  40.608 0 40.632 0.192 ;
    END
  END i[397]
  PIN i[398]
    DIRECTION INPUT ;
    USE SIGNAL ;
    PORT
      LAYER M3 ;
        RECT  40.68 0 40.698 0.144 ;
    END
  END i[398]
  PIN i[399]
    DIRECTION INPUT ;
    USE SIGNAL ;
    PORT
      LAYER M5 ;
        RECT  40.8 0 40.824 0.192 ;
    END
  END i[399]
  PIN i[39]
    DIRECTION INPUT ;
    USE SIGNAL ;
    PORT
      LAYER M5 ;
        RECT  5.952 0 5.976 0.192 ;
    END
  END i[39]
  PIN i[3]
    DIRECTION INPUT ;
    USE SIGNAL ;
    PORT
      LAYER M5 ;
        RECT  2.496 0 2.52 0.192 ;
    END
  END i[3]
  PIN i[400]
    DIRECTION INPUT ;
    USE SIGNAL ;
    PORT
      LAYER M3 ;
        RECT  40.896 0 40.914 0.144 ;
    END
  END i[400]
  PIN i[401]
    DIRECTION INPUT ;
    USE SIGNAL ;
    PORT
      LAYER M5 ;
        RECT  40.992 0 41.016 0.192 ;
    END
  END i[401]
  PIN i[402]
    DIRECTION INPUT ;
    USE SIGNAL ;
    PORT
      LAYER M3 ;
        RECT  41.076 0 41.094 0.144 ;
    END
  END i[402]
  PIN i[403]
    DIRECTION INPUT ;
    USE SIGNAL ;
    PORT
      LAYER M5 ;
        RECT  41.184 0 41.208 0.192 ;
    END
  END i[403]
  PIN i[404]
    DIRECTION INPUT ;
    USE SIGNAL ;
    PORT
      LAYER M3 ;
        RECT  41.256 0 41.274 0.144 ;
    END
  END i[404]
  PIN i[405]
    DIRECTION INPUT ;
    USE SIGNAL ;
    PORT
      LAYER M5 ;
        RECT  41.376 0 41.4 0.192 ;
    END
  END i[405]
  PIN i[406]
    DIRECTION INPUT ;
    USE SIGNAL ;
    PORT
      LAYER M3 ;
        RECT  41.472 0 41.49 0.144 ;
    END
  END i[406]
  PIN i[407]
    DIRECTION INPUT ;
    USE SIGNAL ;
    PORT
      LAYER M5 ;
        RECT  41.568 0 41.592 0.192 ;
    END
  END i[407]
  PIN i[408]
    DIRECTION INPUT ;
    USE SIGNAL ;
    PORT
      LAYER M3 ;
        RECT  41.652 0 41.67 0.144 ;
    END
  END i[408]
  PIN i[409]
    DIRECTION INPUT ;
    USE SIGNAL ;
    PORT
      LAYER M5 ;
        RECT  41.76 0 41.784 0.192 ;
    END
  END i[409]
  PIN i[40]
    DIRECTION INPUT ;
    USE SIGNAL ;
    PORT
      LAYER M3 ;
        RECT  6.084 0 6.102 0.144 ;
    END
  END i[40]
  PIN i[410]
    DIRECTION INPUT ;
    USE SIGNAL ;
    PORT
      LAYER M3 ;
        RECT  41.868 0 41.886 0.144 ;
    END
  END i[410]
  PIN i[411]
    DIRECTION INPUT ;
    USE SIGNAL ;
    PORT
      LAYER M5 ;
        RECT  41.952 0 41.976 0.192 ;
    END
  END i[411]
  PIN i[412]
    DIRECTION INPUT ;
    USE SIGNAL ;
    PORT
      LAYER M3 ;
        RECT  42.048 0 42.066 0.144 ;
    END
  END i[412]
  PIN i[413]
    DIRECTION INPUT ;
    USE SIGNAL ;
    PORT
      LAYER M5 ;
        RECT  42.144 0 42.168 0.192 ;
    END
  END i[413]
  PIN i[414]
    DIRECTION INPUT ;
    USE SIGNAL ;
    PORT
      LAYER M3 ;
        RECT  42.228 0 42.246 0.144 ;
    END
  END i[414]
  PIN i[415]
    DIRECTION INPUT ;
    USE SIGNAL ;
    PORT
      LAYER M5 ;
        RECT  42.336 0 42.36 0.192 ;
    END
  END i[415]
  PIN i[416]
    DIRECTION INPUT ;
    USE SIGNAL ;
    PORT
      LAYER M3 ;
        RECT  42.444 0 42.462 0.144 ;
    END
  END i[416]
  PIN i[417]
    DIRECTION INPUT ;
    USE SIGNAL ;
    PORT
      LAYER M5 ;
        RECT  42.528 0 42.552 0.192 ;
    END
  END i[417]
  PIN i[418]
    DIRECTION INPUT ;
    USE SIGNAL ;
    PORT
      LAYER M3 ;
        RECT  42.624 0 42.642 0.144 ;
    END
  END i[418]
  PIN i[419]
    DIRECTION INPUT ;
    USE SIGNAL ;
    PORT
      LAYER M5 ;
        RECT  42.72 0 42.744 0.192 ;
    END
  END i[419]
  PIN i[41]
    DIRECTION INPUT ;
    USE SIGNAL ;
    PORT
      LAYER M5 ;
        RECT  6.144 0 6.168 0.192 ;
    END
  END i[41]
  PIN i[420]
    DIRECTION INPUT ;
    USE SIGNAL ;
    PORT
      LAYER M3 ;
        RECT  42.804 0 42.822 0.144 ;
    END
  END i[420]
  PIN i[421]
    DIRECTION INPUT ;
    USE SIGNAL ;
    PORT
      LAYER M5 ;
        RECT  42.912 0 42.936 0.192 ;
    END
  END i[421]
  PIN i[422]
    DIRECTION INPUT ;
    USE SIGNAL ;
    PORT
      LAYER M3 ;
        RECT  43.02 0 43.038 0.144 ;
    END
  END i[422]
  PIN i[423]
    DIRECTION INPUT ;
    USE SIGNAL ;
    PORT
      LAYER M5 ;
        RECT  43.104 0 43.128 0.192 ;
    END
  END i[423]
  PIN i[424]
    DIRECTION INPUT ;
    USE SIGNAL ;
    PORT
      LAYER M3 ;
        RECT  43.2 0 43.218 0.144 ;
    END
  END i[424]
  PIN i[425]
    DIRECTION INPUT ;
    USE SIGNAL ;
    PORT
      LAYER M5 ;
        RECT  43.296 0 43.32 0.192 ;
    END
  END i[425]
  PIN i[426]
    DIRECTION INPUT ;
    USE SIGNAL ;
    PORT
      LAYER M3 ;
        RECT  43.416 0 43.434 0.144 ;
    END
  END i[426]
  PIN i[427]
    DIRECTION INPUT ;
    USE SIGNAL ;
    PORT
      LAYER M5 ;
        RECT  43.488 0 43.512 0.192 ;
    END
  END i[427]
  PIN i[428]
    DIRECTION INPUT ;
    USE SIGNAL ;
    PORT
      LAYER M3 ;
        RECT  43.596 0 43.614 0.144 ;
    END
  END i[428]
  PIN i[429]
    DIRECTION INPUT ;
    USE SIGNAL ;
    PORT
      LAYER M5 ;
        RECT  43.68 0 43.704 0.192 ;
    END
  END i[429]
  PIN i[42]
    DIRECTION INPUT ;
    USE SIGNAL ;
    PORT
      LAYER M3 ;
        RECT  6.264 0 6.282 0.144 ;
    END
  END i[42]
  PIN i[430]
    DIRECTION INPUT ;
    USE SIGNAL ;
    PORT
      LAYER M3 ;
        RECT  43.776 0 43.794 0.144 ;
    END
  END i[430]
  PIN i[431]
    DIRECTION INPUT ;
    USE SIGNAL ;
    PORT
      LAYER M5 ;
        RECT  43.872 0 43.896 0.192 ;
    END
  END i[431]
  PIN i[432]
    DIRECTION INPUT ;
    USE SIGNAL ;
    PORT
      LAYER M3 ;
        RECT  43.992 0 44.01 0.144 ;
    END
  END i[432]
  PIN i[433]
    DIRECTION INPUT ;
    USE SIGNAL ;
    PORT
      LAYER M5 ;
        RECT  44.064 0 44.088 0.192 ;
    END
  END i[433]
  PIN i[434]
    DIRECTION INPUT ;
    USE SIGNAL ;
    PORT
      LAYER M3 ;
        RECT  44.172 0 44.19 0.144 ;
    END
  END i[434]
  PIN i[435]
    DIRECTION INPUT ;
    USE SIGNAL ;
    PORT
      LAYER M5 ;
        RECT  44.256 0 44.28 0.192 ;
    END
  END i[435]
  PIN i[436]
    DIRECTION INPUT ;
    USE SIGNAL ;
    PORT
      LAYER M3 ;
        RECT  44.352 0 44.37 0.144 ;
    END
  END i[436]
  PIN i[437]
    DIRECTION INPUT ;
    USE SIGNAL ;
    PORT
      LAYER M5 ;
        RECT  44.448 0 44.472 0.192 ;
    END
  END i[437]
  PIN i[438]
    DIRECTION INPUT ;
    USE SIGNAL ;
    PORT
      LAYER M3 ;
        RECT  44.568 0 44.586 0.144 ;
    END
  END i[438]
  PIN i[439]
    DIRECTION INPUT ;
    USE SIGNAL ;
    PORT
      LAYER M5 ;
        RECT  44.64 0 44.664 0.192 ;
    END
  END i[439]
  PIN i[43]
    DIRECTION INPUT ;
    USE SIGNAL ;
    PORT
      LAYER M5 ;
        RECT  6.336 0 6.36 0.192 ;
    END
  END i[43]
  PIN i[440]
    DIRECTION INPUT ;
    USE SIGNAL ;
    PORT
      LAYER M3 ;
        RECT  44.748 0 44.766 0.144 ;
    END
  END i[440]
  PIN i[441]
    DIRECTION INPUT ;
    USE SIGNAL ;
    PORT
      LAYER M5 ;
        RECT  44.832 0 44.856 0.192 ;
    END
  END i[441]
  PIN i[442]
    DIRECTION INPUT ;
    USE SIGNAL ;
    PORT
      LAYER M3 ;
        RECT  44.964 0 44.982 0.144 ;
    END
  END i[442]
  PIN i[443]
    DIRECTION INPUT ;
    USE SIGNAL ;
    PORT
      LAYER M5 ;
        RECT  45.024 0 45.048 0.192 ;
    END
  END i[443]
  PIN i[444]
    DIRECTION INPUT ;
    USE SIGNAL ;
    PORT
      LAYER M3 ;
        RECT  45.144 0 45.162 0.144 ;
    END
  END i[444]
  PIN i[445]
    DIRECTION INPUT ;
    USE SIGNAL ;
    PORT
      LAYER M5 ;
        RECT  45.216 0 45.24 0.192 ;
    END
  END i[445]
  PIN i[446]
    DIRECTION INPUT ;
    USE SIGNAL ;
    PORT
      LAYER M3 ;
        RECT  45.324 0 45.342 0.144 ;
    END
  END i[446]
  PIN i[447]
    DIRECTION INPUT ;
    USE SIGNAL ;
    PORT
      LAYER M5 ;
        RECT  45.408 0 45.432 0.192 ;
    END
  END i[447]
  PIN i[448]
    DIRECTION INPUT ;
    USE SIGNAL ;
    PORT
      LAYER M3 ;
        RECT  45.54 0 45.558 0.144 ;
    END
  END i[448]
  PIN i[449]
    DIRECTION INPUT ;
    USE SIGNAL ;
    PORT
      LAYER M5 ;
        RECT  45.6 0 45.624 0.192 ;
    END
  END i[449]
  PIN i[44]
    DIRECTION INPUT ;
    USE SIGNAL ;
    PORT
      LAYER M3 ;
        RECT  6.444 0 6.462 0.144 ;
    END
  END i[44]
  PIN i[450]
    DIRECTION INPUT ;
    USE SIGNAL ;
    PORT
      LAYER M3 ;
        RECT  45.72 0 45.738 0.144 ;
    END
  END i[450]
  PIN i[451]
    DIRECTION INPUT ;
    USE SIGNAL ;
    PORT
      LAYER M5 ;
        RECT  45.792 0 45.816 0.192 ;
    END
  END i[451]
  PIN i[452]
    DIRECTION INPUT ;
    USE SIGNAL ;
    PORT
      LAYER M3 ;
        RECT  45.9 0 45.918 0.144 ;
    END
  END i[452]
  PIN i[453]
    DIRECTION INPUT ;
    USE SIGNAL ;
    PORT
      LAYER M5 ;
        RECT  46.032 0 46.056 0.192 ;
    END
  END i[453]
  PIN i[454]
    DIRECTION INPUT ;
    USE SIGNAL ;
    PORT
      LAYER M3 ;
        RECT  46.116 0 46.134 0.144 ;
    END
  END i[454]
  PIN i[455]
    DIRECTION INPUT ;
    USE SIGNAL ;
    PORT
      LAYER M5 ;
        RECT  46.224 0 46.248 0.192 ;
    END
  END i[455]
  PIN i[456]
    DIRECTION INPUT ;
    USE SIGNAL ;
    PORT
      LAYER M3 ;
        RECT  46.296 0 46.314 0.144 ;
    END
  END i[456]
  PIN i[457]
    DIRECTION INPUT ;
    USE SIGNAL ;
    PORT
      LAYER M5 ;
        RECT  46.416 0 46.44 0.192 ;
    END
  END i[457]
  PIN i[458]
    DIRECTION INPUT ;
    USE SIGNAL ;
    PORT
      LAYER M3 ;
        RECT  46.512 0 46.53 0.144 ;
    END
  END i[458]
  PIN i[459]
    DIRECTION INPUT ;
    USE SIGNAL ;
    PORT
      LAYER M5 ;
        RECT  46.608 0 46.632 0.192 ;
    END
  END i[459]
  PIN i[45]
    DIRECTION INPUT ;
    USE SIGNAL ;
    PORT
      LAYER M5 ;
        RECT  6.528 0 6.552 0.192 ;
    END
  END i[45]
  PIN i[460]
    DIRECTION INPUT ;
    USE SIGNAL ;
    PORT
      LAYER M3 ;
        RECT  46.692 0 46.71 0.144 ;
    END
  END i[460]
  PIN i[461]
    DIRECTION INPUT ;
    USE SIGNAL ;
    PORT
      LAYER M5 ;
        RECT  46.8 0 46.824 0.192 ;
    END
  END i[461]
  PIN i[462]
    DIRECTION INPUT ;
    USE SIGNAL ;
    PORT
      LAYER M3 ;
        RECT  46.872 0 46.89 0.144 ;
    END
  END i[462]
  PIN i[463]
    DIRECTION INPUT ;
    USE SIGNAL ;
    PORT
      LAYER M5 ;
        RECT  46.992 0 47.016 0.192 ;
    END
  END i[463]
  PIN i[464]
    DIRECTION INPUT ;
    USE SIGNAL ;
    PORT
      LAYER M3 ;
        RECT  47.088 0 47.106 0.144 ;
    END
  END i[464]
  PIN i[465]
    DIRECTION INPUT ;
    USE SIGNAL ;
    PORT
      LAYER M5 ;
        RECT  47.184 0 47.208 0.192 ;
    END
  END i[465]
  PIN i[466]
    DIRECTION INPUT ;
    USE SIGNAL ;
    PORT
      LAYER M3 ;
        RECT  47.268 0 47.286 0.144 ;
    END
  END i[466]
  PIN i[467]
    DIRECTION INPUT ;
    USE SIGNAL ;
    PORT
      LAYER M5 ;
        RECT  47.376 0 47.4 0.192 ;
    END
  END i[467]
  PIN i[468]
    DIRECTION INPUT ;
    USE SIGNAL ;
    PORT
      LAYER M3 ;
        RECT  47.448 0 47.466 0.144 ;
    END
  END i[468]
  PIN i[469]
    DIRECTION INPUT ;
    USE SIGNAL ;
    PORT
      LAYER M5 ;
        RECT  47.568 0 47.592 0.192 ;
    END
  END i[469]
  PIN i[46]
    DIRECTION INPUT ;
    USE SIGNAL ;
    PORT
      LAYER M3 ;
        RECT  6.66 0 6.678 0.144 ;
    END
  END i[46]
  PIN i[470]
    DIRECTION INPUT ;
    USE SIGNAL ;
    PORT
      LAYER M3 ;
        RECT  47.664 0 47.682 0.144 ;
    END
  END i[470]
  PIN i[471]
    DIRECTION INPUT ;
    USE SIGNAL ;
    PORT
      LAYER M5 ;
        RECT  47.76 0 47.784 0.192 ;
    END
  END i[471]
  PIN i[472]
    DIRECTION INPUT ;
    USE SIGNAL ;
    PORT
      LAYER M3 ;
        RECT  47.844 0 47.862 0.144 ;
    END
  END i[472]
  PIN i[473]
    DIRECTION INPUT ;
    USE SIGNAL ;
    PORT
      LAYER M5 ;
        RECT  47.952 0 47.976 0.192 ;
    END
  END i[473]
  PIN i[474]
    DIRECTION INPUT ;
    USE SIGNAL ;
    PORT
      LAYER M3 ;
        RECT  48.06 0 48.078 0.144 ;
    END
  END i[474]
  PIN i[475]
    DIRECTION INPUT ;
    USE SIGNAL ;
    PORT
      LAYER M5 ;
        RECT  48.144 0 48.168 0.192 ;
    END
  END i[475]
  PIN i[476]
    DIRECTION INPUT ;
    USE SIGNAL ;
    PORT
      LAYER M3 ;
        RECT  48.24 0 48.258 0.144 ;
    END
  END i[476]
  PIN i[477]
    DIRECTION INPUT ;
    USE SIGNAL ;
    PORT
      LAYER M5 ;
        RECT  48.336 0 48.36 0.192 ;
    END
  END i[477]
  PIN i[478]
    DIRECTION INPUT ;
    USE SIGNAL ;
    PORT
      LAYER M3 ;
        RECT  48.42 0 48.438 0.144 ;
    END
  END i[478]
  PIN i[479]
    DIRECTION INPUT ;
    USE SIGNAL ;
    PORT
      LAYER M5 ;
        RECT  48.528 0 48.552 0.192 ;
    END
  END i[479]
  PIN i[47]
    DIRECTION INPUT ;
    USE SIGNAL ;
    PORT
      LAYER M5 ;
        RECT  6.72 0 6.744 0.192 ;
    END
  END i[47]
  PIN i[480]
    DIRECTION INPUT ;
    USE SIGNAL ;
    PORT
      LAYER M3 ;
        RECT  48.636 0 48.654 0.144 ;
    END
  END i[480]
  PIN i[481]
    DIRECTION INPUT ;
    USE SIGNAL ;
    PORT
      LAYER M5 ;
        RECT  48.72 0 48.744 0.192 ;
    END
  END i[481]
  PIN i[482]
    DIRECTION INPUT ;
    USE SIGNAL ;
    PORT
      LAYER M3 ;
        RECT  48.816 0 48.834 0.144 ;
    END
  END i[482]
  PIN i[483]
    DIRECTION INPUT ;
    USE SIGNAL ;
    PORT
      LAYER M5 ;
        RECT  48.912 0 48.936 0.192 ;
    END
  END i[483]
  PIN i[484]
    DIRECTION INPUT ;
    USE SIGNAL ;
    PORT
      LAYER M3 ;
        RECT  48.996 0 49.014 0.144 ;
    END
  END i[484]
  PIN i[485]
    DIRECTION INPUT ;
    USE SIGNAL ;
    PORT
      LAYER M5 ;
        RECT  49.104 0 49.128 0.192 ;
    END
  END i[485]
  PIN i[486]
    DIRECTION INPUT ;
    USE SIGNAL ;
    PORT
      LAYER M3 ;
        RECT  49.212 0 49.23 0.144 ;
    END
  END i[486]
  PIN i[487]
    DIRECTION INPUT ;
    USE SIGNAL ;
    PORT
      LAYER M5 ;
        RECT  49.296 0 49.32 0.192 ;
    END
  END i[487]
  PIN i[488]
    DIRECTION INPUT ;
    USE SIGNAL ;
    PORT
      LAYER M3 ;
        RECT  49.392 0 49.41 0.144 ;
    END
  END i[488]
  PIN i[489]
    DIRECTION INPUT ;
    USE SIGNAL ;
    PORT
      LAYER M5 ;
        RECT  49.488 0 49.512 0.192 ;
    END
  END i[489]
  PIN i[48]
    DIRECTION INPUT ;
    USE SIGNAL ;
    PORT
      LAYER M3 ;
        RECT  6.84 0 6.858 0.144 ;
    END
  END i[48]
  PIN i[490]
    DIRECTION INPUT ;
    USE SIGNAL ;
    PORT
      LAYER M3 ;
        RECT  49.608 0 49.626 0.144 ;
    END
  END i[490]
  PIN i[491]
    DIRECTION INPUT ;
    USE SIGNAL ;
    PORT
      LAYER M5 ;
        RECT  49.68 0 49.704 0.192 ;
    END
  END i[491]
  PIN i[492]
    DIRECTION INPUT ;
    USE SIGNAL ;
    PORT
      LAYER M3 ;
        RECT  49.788 0 49.806 0.144 ;
    END
  END i[492]
  PIN i[493]
    DIRECTION INPUT ;
    USE SIGNAL ;
    PORT
      LAYER M5 ;
        RECT  49.872 0 49.896 0.192 ;
    END
  END i[493]
  PIN i[494]
    DIRECTION INPUT ;
    USE SIGNAL ;
    PORT
      LAYER M3 ;
        RECT  49.968 0 49.986 0.144 ;
    END
  END i[494]
  PIN i[495]
    DIRECTION INPUT ;
    USE SIGNAL ;
    PORT
      LAYER M5 ;
        RECT  50.064 0 50.088 0.192 ;
    END
  END i[495]
  PIN i[496]
    DIRECTION INPUT ;
    USE SIGNAL ;
    PORT
      LAYER M3 ;
        RECT  50.184 0 50.202 0.144 ;
    END
  END i[496]
  PIN i[497]
    DIRECTION INPUT ;
    USE SIGNAL ;
    PORT
      LAYER M5 ;
        RECT  50.256 0 50.28 0.192 ;
    END
  END i[497]
  PIN i[498]
    DIRECTION INPUT ;
    USE SIGNAL ;
    PORT
      LAYER M3 ;
        RECT  50.364 0 50.382 0.144 ;
    END
  END i[498]
  PIN i[499]
    DIRECTION INPUT ;
    USE SIGNAL ;
    PORT
      LAYER M5 ;
        RECT  50.448 0 50.472 0.192 ;
    END
  END i[499]
  PIN i[49]
    DIRECTION INPUT ;
    USE SIGNAL ;
    PORT
      LAYER M5 ;
        RECT  6.912 0 6.936 0.192 ;
    END
  END i[49]
  PIN i[4]
    DIRECTION INPUT ;
    USE SIGNAL ;
    PORT
      LAYER M3 ;
        RECT  2.592 0 2.61 0.144 ;
    END
  END i[4]
  PIN i[500]
    DIRECTION INPUT ;
    USE SIGNAL ;
    PORT
      LAYER M3 ;
        RECT  50.544 0 50.562 0.144 ;
    END
  END i[500]
  PIN i[501]
    DIRECTION INPUT ;
    USE SIGNAL ;
    PORT
      LAYER M5 ;
        RECT  50.64 0 50.664 0.192 ;
    END
  END i[501]
  PIN i[502]
    DIRECTION INPUT ;
    USE SIGNAL ;
    PORT
      LAYER M3 ;
        RECT  50.76 0 50.778 0.144 ;
    END
  END i[502]
  PIN i[503]
    DIRECTION INPUT ;
    USE SIGNAL ;
    PORT
      LAYER M5 ;
        RECT  50.832 0 50.856 0.192 ;
    END
  END i[503]
  PIN i[504]
    DIRECTION INPUT ;
    USE SIGNAL ;
    PORT
      LAYER M3 ;
        RECT  50.94 0 50.958 0.144 ;
    END
  END i[504]
  PIN i[505]
    DIRECTION INPUT ;
    USE SIGNAL ;
    PORT
      LAYER M5 ;
        RECT  51.024 0 51.048 0.192 ;
    END
  END i[505]
  PIN i[506]
    DIRECTION INPUT ;
    USE SIGNAL ;
    PORT
      LAYER M3 ;
        RECT  51.12 0 51.138 0.144 ;
    END
  END i[506]
  PIN i[507]
    DIRECTION INPUT ;
    USE SIGNAL ;
    PORT
      LAYER M5 ;
        RECT  51.216 0 51.24 0.192 ;
    END
  END i[507]
  PIN i[508]
    DIRECTION INPUT ;
    USE SIGNAL ;
    PORT
      LAYER M3 ;
        RECT  51.336 0 51.354 0.144 ;
    END
  END i[508]
  PIN i[509]
    DIRECTION INPUT ;
    USE SIGNAL ;
    PORT
      LAYER M5 ;
        RECT  51.408 0 51.432 0.192 ;
    END
  END i[509]
  PIN i[50]
    DIRECTION INPUT ;
    USE SIGNAL ;
    PORT
      LAYER M3 ;
        RECT  7.02 0 7.038 0.144 ;
    END
  END i[50]
  PIN i[510]
    DIRECTION INPUT ;
    USE SIGNAL ;
    PORT
      LAYER M3 ;
        RECT  51.516 0 51.534 0.144 ;
    END
  END i[510]
  PIN i[511]
    DIRECTION INPUT ;
    USE SIGNAL ;
    PORT
      LAYER M5 ;
        RECT  51.6 0 51.624 0.192 ;
    END
  END i[511]
  PIN i[512]
    DIRECTION INPUT ;
    USE SIGNAL ;
    PORT
      LAYER M3 ;
        RECT  51.732 0 51.75 0.144 ;
    END
  END i[512]
  PIN i[513]
    DIRECTION INPUT ;
    USE SIGNAL ;
    PORT
      LAYER M5 ;
        RECT  51.792 0 51.816 0.192 ;
    END
  END i[513]
  PIN i[514]
    DIRECTION INPUT ;
    USE SIGNAL ;
    PORT
      LAYER M3 ;
        RECT  51.912 0 51.93 0.144 ;
    END
  END i[514]
  PIN i[515]
    DIRECTION INPUT ;
    USE SIGNAL ;
    PORT
      LAYER M5 ;
        RECT  51.984 0 52.008 0.192 ;
    END
  END i[515]
  PIN i[516]
    DIRECTION INPUT ;
    USE SIGNAL ;
    PORT
      LAYER M3 ;
        RECT  52.092 0 52.11 0.144 ;
    END
  END i[516]
  PIN i[517]
    DIRECTION INPUT ;
    USE SIGNAL ;
    PORT
      LAYER M5 ;
        RECT  52.176 0 52.2 0.192 ;
    END
  END i[517]
  PIN i[518]
    DIRECTION INPUT ;
    USE SIGNAL ;
    PORT
      LAYER M3 ;
        RECT  52.308 0 52.326 0.144 ;
    END
  END i[518]
  PIN i[519]
    DIRECTION INPUT ;
    USE SIGNAL ;
    PORT
      LAYER M5 ;
        RECT  52.416 0 52.44 0.192 ;
    END
  END i[519]
  PIN i[51]
    DIRECTION INPUT ;
    USE SIGNAL ;
    PORT
      LAYER M5 ;
        RECT  7.152 0 7.176 0.192 ;
    END
  END i[51]
  PIN i[520]
    DIRECTION INPUT ;
    USE SIGNAL ;
    PORT
      LAYER M3 ;
        RECT  52.488 0 52.506 0.144 ;
    END
  END i[520]
  PIN i[521]
    DIRECTION INPUT ;
    USE SIGNAL ;
    PORT
      LAYER M5 ;
        RECT  52.608 0 52.632 0.192 ;
    END
  END i[521]
  PIN i[522]
    DIRECTION INPUT ;
    USE SIGNAL ;
    PORT
      LAYER M3 ;
        RECT  52.668 0 52.686 0.144 ;
    END
  END i[522]
  PIN i[523]
    DIRECTION INPUT ;
    USE SIGNAL ;
    PORT
      LAYER M5 ;
        RECT  52.8 0 52.824 0.192 ;
    END
  END i[523]
  PIN i[524]
    DIRECTION INPUT ;
    USE SIGNAL ;
    PORT
      LAYER M3 ;
        RECT  52.884 0 52.902 0.144 ;
    END
  END i[524]
  PIN i[525]
    DIRECTION INPUT ;
    USE SIGNAL ;
    PORT
      LAYER M5 ;
        RECT  52.992 0 53.016 0.192 ;
    END
  END i[525]
  PIN i[526]
    DIRECTION INPUT ;
    USE SIGNAL ;
    PORT
      LAYER M3 ;
        RECT  53.064 0 53.082 0.144 ;
    END
  END i[526]
  PIN i[527]
    DIRECTION INPUT ;
    USE SIGNAL ;
    PORT
      LAYER M5 ;
        RECT  53.184 0 53.208 0.192 ;
    END
  END i[527]
  PIN i[528]
    DIRECTION INPUT ;
    USE SIGNAL ;
    PORT
      LAYER M3 ;
        RECT  53.28 0 53.298 0.144 ;
    END
  END i[528]
  PIN i[529]
    DIRECTION INPUT ;
    USE SIGNAL ;
    PORT
      LAYER M5 ;
        RECT  53.376 0 53.4 0.192 ;
    END
  END i[529]
  PIN i[52]
    DIRECTION INPUT ;
    USE SIGNAL ;
    PORT
      LAYER M3 ;
        RECT  7.236 0 7.254 0.144 ;
    END
  END i[52]
  PIN i[530]
    DIRECTION INPUT ;
    USE SIGNAL ;
    PORT
      LAYER M3 ;
        RECT  53.46 0 53.478 0.144 ;
    END
  END i[530]
  PIN i[531]
    DIRECTION INPUT ;
    USE SIGNAL ;
    PORT
      LAYER M5 ;
        RECT  53.568 0 53.592 0.192 ;
    END
  END i[531]
  PIN i[532]
    DIRECTION INPUT ;
    USE SIGNAL ;
    PORT
      LAYER M3 ;
        RECT  53.64 0 53.658 0.144 ;
    END
  END i[532]
  PIN i[533]
    DIRECTION INPUT ;
    USE SIGNAL ;
    PORT
      LAYER M5 ;
        RECT  53.76 0 53.784 0.192 ;
    END
  END i[533]
  PIN i[534]
    DIRECTION INPUT ;
    USE SIGNAL ;
    PORT
      LAYER M3 ;
        RECT  53.856 0 53.874 0.144 ;
    END
  END i[534]
  PIN i[535]
    DIRECTION INPUT ;
    USE SIGNAL ;
    PORT
      LAYER M5 ;
        RECT  53.952 0 53.976 0.192 ;
    END
  END i[535]
  PIN i[53]
    DIRECTION INPUT ;
    USE SIGNAL ;
    PORT
      LAYER M5 ;
        RECT  7.344 0 7.368 0.192 ;
    END
  END i[53]
  PIN i[54]
    DIRECTION INPUT ;
    USE SIGNAL ;
    PORT
      LAYER M3 ;
        RECT  7.416 0 7.434 0.144 ;
    END
  END i[54]
  PIN i[55]
    DIRECTION INPUT ;
    USE SIGNAL ;
    PORT
      LAYER M5 ;
        RECT  7.536 0 7.56 0.192 ;
    END
  END i[55]
  PIN i[56]
    DIRECTION INPUT ;
    USE SIGNAL ;
    PORT
      LAYER M3 ;
        RECT  7.632 0 7.65 0.144 ;
    END
  END i[56]
  PIN i[57]
    DIRECTION INPUT ;
    USE SIGNAL ;
    PORT
      LAYER M5 ;
        RECT  7.728 0 7.752 0.192 ;
    END
  END i[57]
  PIN i[58]
    DIRECTION INPUT ;
    USE SIGNAL ;
    PORT
      LAYER M3 ;
        RECT  7.812 0 7.83 0.144 ;
    END
  END i[58]
  PIN i[59]
    DIRECTION INPUT ;
    USE SIGNAL ;
    PORT
      LAYER M5 ;
        RECT  7.92 0 7.944 0.192 ;
    END
  END i[59]
  PIN i[5]
    DIRECTION INPUT ;
    USE SIGNAL ;
    PORT
      LAYER M5 ;
        RECT  2.688 0 2.712 0.192 ;
    END
  END i[5]
  PIN i[60]
    DIRECTION INPUT ;
    USE SIGNAL ;
    PORT
      LAYER M3 ;
        RECT  7.992 0 8.01 0.144 ;
    END
  END i[60]
  PIN i[61]
    DIRECTION INPUT ;
    USE SIGNAL ;
    PORT
      LAYER M5 ;
        RECT  8.112 0 8.136 0.192 ;
    END
  END i[61]
  PIN i[62]
    DIRECTION INPUT ;
    USE SIGNAL ;
    PORT
      LAYER M3 ;
        RECT  8.208 0 8.226 0.144 ;
    END
  END i[62]
  PIN i[63]
    DIRECTION INPUT ;
    USE SIGNAL ;
    PORT
      LAYER M5 ;
        RECT  8.304 0 8.328 0.192 ;
    END
  END i[63]
  PIN i[64]
    DIRECTION INPUT ;
    USE SIGNAL ;
    PORT
      LAYER M3 ;
        RECT  8.388 0 8.406 0.144 ;
    END
  END i[64]
  PIN i[65]
    DIRECTION INPUT ;
    USE SIGNAL ;
    PORT
      LAYER M5 ;
        RECT  8.496 0 8.52 0.192 ;
    END
  END i[65]
  PIN i[66]
    DIRECTION INPUT ;
    USE SIGNAL ;
    PORT
      LAYER M3 ;
        RECT  8.568 0 8.586 0.144 ;
    END
  END i[66]
  PIN i[67]
    DIRECTION INPUT ;
    USE SIGNAL ;
    PORT
      LAYER M5 ;
        RECT  8.688 0 8.712 0.192 ;
    END
  END i[67]
  PIN i[68]
    DIRECTION INPUT ;
    USE SIGNAL ;
    PORT
      LAYER M3 ;
        RECT  8.784 0 8.802 0.144 ;
    END
  END i[68]
  PIN i[69]
    DIRECTION INPUT ;
    USE SIGNAL ;
    PORT
      LAYER M5 ;
        RECT  8.88 0 8.904 0.192 ;
    END
  END i[69]
  PIN i[6]
    DIRECTION INPUT ;
    USE SIGNAL ;
    PORT
      LAYER M3 ;
        RECT  2.772 0 2.79 0.144 ;
    END
  END i[6]
  PIN i[70]
    DIRECTION INPUT ;
    USE SIGNAL ;
    PORT
      LAYER M3 ;
        RECT  8.964 0 8.982 0.144 ;
    END
  END i[70]
  PIN i[71]
    DIRECTION INPUT ;
    USE SIGNAL ;
    PORT
      LAYER M5 ;
        RECT  9.072 0 9.096 0.192 ;
    END
  END i[71]
  PIN i[72]
    DIRECTION INPUT ;
    USE SIGNAL ;
    PORT
      LAYER M3 ;
        RECT  9.18 0 9.198 0.144 ;
    END
  END i[72]
  PIN i[73]
    DIRECTION INPUT ;
    USE SIGNAL ;
    PORT
      LAYER M5 ;
        RECT  9.264 0 9.288 0.192 ;
    END
  END i[73]
  PIN i[74]
    DIRECTION INPUT ;
    USE SIGNAL ;
    PORT
      LAYER M3 ;
        RECT  9.36 0 9.378 0.144 ;
    END
  END i[74]
  PIN i[75]
    DIRECTION INPUT ;
    USE SIGNAL ;
    PORT
      LAYER M5 ;
        RECT  9.456 0 9.48 0.192 ;
    END
  END i[75]
  PIN i[76]
    DIRECTION INPUT ;
    USE SIGNAL ;
    PORT
      LAYER M3 ;
        RECT  9.54 0 9.558 0.144 ;
    END
  END i[76]
  PIN i[77]
    DIRECTION INPUT ;
    USE SIGNAL ;
    PORT
      LAYER M5 ;
        RECT  9.648 0 9.672 0.192 ;
    END
  END i[77]
  PIN i[78]
    DIRECTION INPUT ;
    USE SIGNAL ;
    PORT
      LAYER M3 ;
        RECT  9.756 0 9.774 0.144 ;
    END
  END i[78]
  PIN i[79]
    DIRECTION INPUT ;
    USE SIGNAL ;
    PORT
      LAYER M5 ;
        RECT  9.84 0 9.864 0.192 ;
    END
  END i[79]
  PIN i[7]
    DIRECTION INPUT ;
    USE SIGNAL ;
    PORT
      LAYER M5 ;
        RECT  2.88 0 2.904 0.192 ;
    END
  END i[7]
  PIN i[80]
    DIRECTION INPUT ;
    USE SIGNAL ;
    PORT
      LAYER M3 ;
        RECT  9.936 0 9.954 0.144 ;
    END
  END i[80]
  PIN i[81]
    DIRECTION INPUT ;
    USE SIGNAL ;
    PORT
      LAYER M5 ;
        RECT  10.032 0 10.056 0.192 ;
    END
  END i[81]
  PIN i[82]
    DIRECTION INPUT ;
    USE SIGNAL ;
    PORT
      LAYER M3 ;
        RECT  10.116 0 10.134 0.144 ;
    END
  END i[82]
  PIN i[83]
    DIRECTION INPUT ;
    USE SIGNAL ;
    PORT
      LAYER M5 ;
        RECT  10.224 0 10.248 0.192 ;
    END
  END i[83]
  PIN i[84]
    DIRECTION INPUT ;
    USE SIGNAL ;
    PORT
      LAYER M3 ;
        RECT  10.332 0 10.35 0.144 ;
    END
  END i[84]
  PIN i[85]
    DIRECTION INPUT ;
    USE SIGNAL ;
    PORT
      LAYER M5 ;
        RECT  10.416 0 10.44 0.192 ;
    END
  END i[85]
  PIN i[86]
    DIRECTION INPUT ;
    USE SIGNAL ;
    PORT
      LAYER M3 ;
        RECT  10.512 0 10.53 0.144 ;
    END
  END i[86]
  PIN i[87]
    DIRECTION INPUT ;
    USE SIGNAL ;
    PORT
      LAYER M5 ;
        RECT  10.608 0 10.632 0.192 ;
    END
  END i[87]
  PIN i[88]
    DIRECTION INPUT ;
    USE SIGNAL ;
    PORT
      LAYER M3 ;
        RECT  10.728 0 10.746 0.144 ;
    END
  END i[88]
  PIN i[89]
    DIRECTION INPUT ;
    USE SIGNAL ;
    PORT
      LAYER M5 ;
        RECT  10.8 0 10.824 0.192 ;
    END
  END i[89]
  PIN i[8]
    DIRECTION INPUT ;
    USE SIGNAL ;
    PORT
      LAYER M3 ;
        RECT  2.988 0 3.006 0.144 ;
    END
  END i[8]
  PIN i[90]
    DIRECTION INPUT ;
    USE SIGNAL ;
    PORT
      LAYER M3 ;
        RECT  10.908 0 10.926 0.144 ;
    END
  END i[90]
  PIN i[91]
    DIRECTION INPUT ;
    USE SIGNAL ;
    PORT
      LAYER M5 ;
        RECT  10.992 0 11.016 0.192 ;
    END
  END i[91]
  PIN i[92]
    DIRECTION INPUT ;
    USE SIGNAL ;
    PORT
      LAYER M3 ;
        RECT  11.088 0 11.106 0.144 ;
    END
  END i[92]
  PIN i[93]
    DIRECTION INPUT ;
    USE SIGNAL ;
    PORT
      LAYER M5 ;
        RECT  11.184 0 11.208 0.192 ;
    END
  END i[93]
  PIN i[94]
    DIRECTION INPUT ;
    USE SIGNAL ;
    PORT
      LAYER M3 ;
        RECT  11.304 0 11.322 0.144 ;
    END
  END i[94]
  PIN i[95]
    DIRECTION INPUT ;
    USE SIGNAL ;
    PORT
      LAYER M5 ;
        RECT  11.376 0 11.4 0.192 ;
    END
  END i[95]
  PIN i[96]
    DIRECTION INPUT ;
    USE SIGNAL ;
    PORT
      LAYER M3 ;
        RECT  11.484 0 11.502 0.144 ;
    END
  END i[96]
  PIN i[97]
    DIRECTION INPUT ;
    USE SIGNAL ;
    PORT
      LAYER M5 ;
        RECT  11.568 0 11.592 0.192 ;
    END
  END i[97]
  PIN i[98]
    DIRECTION INPUT ;
    USE SIGNAL ;
    PORT
      LAYER M3 ;
        RECT  11.664 0 11.682 0.144 ;
    END
  END i[98]
  PIN i[99]
    DIRECTION INPUT ;
    USE SIGNAL ;
    PORT
      LAYER M5 ;
        RECT  11.76 0 11.784 0.192 ;
    END
  END i[99]
  PIN i[9]
    DIRECTION INPUT ;
    USE SIGNAL ;
    PORT
      LAYER M5 ;
        RECT  3.072 0 3.096 0.192 ;
    END
  END i[9]
  PIN o[0]
    DIRECTION OUTPUT ;
    USE SIGNAL ;
    PORT
      LAYER M4 ;
        RECT  0 2.208 0.192 2.232 ;
    END
  END o[0]
  PIN o[100]
    DIRECTION OUTPUT ;
    USE SIGNAL ;
    PORT
      LAYER M4 ;
        RECT  0 11.904 0.192 11.928 ;
    END
  END o[100]
  PIN o[101]
    DIRECTION OUTPUT ;
    USE SIGNAL ;
    PORT
      LAYER M4 ;
        RECT  0 12 0.192 12.024 ;
    END
  END o[101]
  PIN o[102]
    DIRECTION OUTPUT ;
    USE SIGNAL ;
    PORT
      LAYER M4 ;
        RECT  0 12.096 0.192 12.12 ;
    END
  END o[102]
  PIN o[103]
    DIRECTION OUTPUT ;
    USE SIGNAL ;
    PORT
      LAYER M4 ;
        RECT  0 12.192 0.192 12.216 ;
    END
  END o[103]
  PIN o[104]
    DIRECTION OUTPUT ;
    USE SIGNAL ;
    PORT
      LAYER M4 ;
        RECT  0 12.288 0.192 12.312 ;
    END
  END o[104]
  PIN o[105]
    DIRECTION OUTPUT ;
    USE SIGNAL ;
    PORT
      LAYER M4 ;
        RECT  0 12.384 0.192 12.408 ;
    END
  END o[105]
  PIN o[106]
    DIRECTION OUTPUT ;
    USE SIGNAL ;
    PORT
      LAYER M4 ;
        RECT  0 12.48 0.192 12.504 ;
    END
  END o[106]
  PIN o[107]
    DIRECTION OUTPUT ;
    USE SIGNAL ;
    PORT
      LAYER M4 ;
        RECT  0 12.576 0.192 12.6 ;
    END
  END o[107]
  PIN o[108]
    DIRECTION OUTPUT ;
    USE SIGNAL ;
    PORT
      LAYER M4 ;
        RECT  0 12.672 0.192 12.696 ;
    END
  END o[108]
  PIN o[109]
    DIRECTION OUTPUT ;
    USE SIGNAL ;
    PORT
      LAYER M4 ;
        RECT  0 12.768 0.192 12.792 ;
    END
  END o[109]
  PIN o[10]
    DIRECTION OUTPUT ;
    USE SIGNAL ;
    PORT
      LAYER M4 ;
        RECT  0 3.168 0.192 3.192 ;
    END
  END o[10]
  PIN o[110]
    DIRECTION OUTPUT ;
    USE SIGNAL ;
    PORT
      LAYER M4 ;
        RECT  0 12.864 0.192 12.888 ;
    END
  END o[110]
  PIN o[111]
    DIRECTION OUTPUT ;
    USE SIGNAL ;
    PORT
      LAYER M4 ;
        RECT  0 12.96 0.192 12.984 ;
    END
  END o[111]
  PIN o[112]
    DIRECTION OUTPUT ;
    USE SIGNAL ;
    PORT
      LAYER M4 ;
        RECT  0 13.056 0.192 13.08 ;
    END
  END o[112]
  PIN o[113]
    DIRECTION OUTPUT ;
    USE SIGNAL ;
    PORT
      LAYER M4 ;
        RECT  0 13.152 0.192 13.176 ;
    END
  END o[113]
  PIN o[114]
    DIRECTION OUTPUT ;
    USE SIGNAL ;
    PORT
      LAYER M4 ;
        RECT  0 13.248 0.192 13.272 ;
    END
  END o[114]
  PIN o[115]
    DIRECTION OUTPUT ;
    USE SIGNAL ;
    PORT
      LAYER M4 ;
        RECT  0 13.344 0.192 13.368 ;
    END
  END o[115]
  PIN o[116]
    DIRECTION OUTPUT ;
    USE SIGNAL ;
    PORT
      LAYER M4 ;
        RECT  0 13.44 0.192 13.464 ;
    END
  END o[116]
  PIN o[117]
    DIRECTION OUTPUT ;
    USE SIGNAL ;
    PORT
      LAYER M4 ;
        RECT  0 13.536 0.192 13.56 ;
    END
  END o[117]
  PIN o[118]
    DIRECTION OUTPUT ;
    USE SIGNAL ;
    PORT
      LAYER M4 ;
        RECT  0 13.632 0.192 13.656 ;
    END
  END o[118]
  PIN o[119]
    DIRECTION OUTPUT ;
    USE SIGNAL ;
    PORT
      LAYER M4 ;
        RECT  0 13.728 0.192 13.752 ;
    END
  END o[119]
  PIN o[11]
    DIRECTION OUTPUT ;
    USE SIGNAL ;
    PORT
      LAYER M4 ;
        RECT  0 3.264 0.192 3.288 ;
    END
  END o[11]
  PIN o[120]
    DIRECTION OUTPUT ;
    USE SIGNAL ;
    PORT
      LAYER M4 ;
        RECT  0 13.824 0.192 13.848 ;
    END
  END o[120]
  PIN o[121]
    DIRECTION OUTPUT ;
    USE SIGNAL ;
    PORT
      LAYER M4 ;
        RECT  0 13.92 0.192 13.944 ;
    END
  END o[121]
  PIN o[122]
    DIRECTION OUTPUT ;
    USE SIGNAL ;
    PORT
      LAYER M4 ;
        RECT  0 14.016 0.192 14.04 ;
    END
  END o[122]
  PIN o[123]
    DIRECTION OUTPUT ;
    USE SIGNAL ;
    PORT
      LAYER M4 ;
        RECT  0 14.112 0.192 14.136 ;
    END
  END o[123]
  PIN o[124]
    DIRECTION OUTPUT ;
    USE SIGNAL ;
    PORT
      LAYER M4 ;
        RECT  0 14.208 0.192 14.232 ;
    END
  END o[124]
  PIN o[125]
    DIRECTION OUTPUT ;
    USE SIGNAL ;
    PORT
      LAYER M4 ;
        RECT  0 14.304 0.192 14.328 ;
    END
  END o[125]
  PIN o[126]
    DIRECTION OUTPUT ;
    USE SIGNAL ;
    PORT
      LAYER M4 ;
        RECT  0 14.4 0.192 14.424 ;
    END
  END o[126]
  PIN o[127]
    DIRECTION OUTPUT ;
    USE SIGNAL ;
    PORT
      LAYER M4 ;
        RECT  0 14.496 0.192 14.52 ;
    END
  END o[127]
  PIN o[128]
    DIRECTION OUTPUT ;
    USE SIGNAL ;
    PORT
      LAYER M4 ;
        RECT  0 14.592 0.192 14.616 ;
    END
  END o[128]
  PIN o[129]
    DIRECTION OUTPUT ;
    USE SIGNAL ;
    PORT
      LAYER M4 ;
        RECT  0 14.688 0.192 14.712 ;
    END
  END o[129]
  PIN o[12]
    DIRECTION OUTPUT ;
    USE SIGNAL ;
    PORT
      LAYER M4 ;
        RECT  0 3.36 0.192 3.384 ;
    END
  END o[12]
  PIN o[130]
    DIRECTION OUTPUT ;
    USE SIGNAL ;
    PORT
      LAYER M4 ;
        RECT  0 14.784 0.192 14.808 ;
    END
  END o[130]
  PIN o[131]
    DIRECTION OUTPUT ;
    USE SIGNAL ;
    PORT
      LAYER M4 ;
        RECT  0 14.88 0.192 14.904 ;
    END
  END o[131]
  PIN o[132]
    DIRECTION OUTPUT ;
    USE SIGNAL ;
    PORT
      LAYER M4 ;
        RECT  0 14.976 0.192 15 ;
    END
  END o[132]
  PIN o[133]
    DIRECTION OUTPUT ;
    USE SIGNAL ;
    PORT
      LAYER M4 ;
        RECT  0 15.072 0.192 15.096 ;
    END
  END o[133]
  PIN o[134]
    DIRECTION OUTPUT ;
    USE SIGNAL ;
    PORT
      LAYER M4 ;
        RECT  0 15.168 0.192 15.192 ;
    END
  END o[134]
  PIN o[135]
    DIRECTION OUTPUT ;
    USE SIGNAL ;
    PORT
      LAYER M4 ;
        RECT  0 15.264 0.192 15.288 ;
    END
  END o[135]
  PIN o[136]
    DIRECTION OUTPUT ;
    USE SIGNAL ;
    PORT
      LAYER M4 ;
        RECT  0 15.36 0.192 15.384 ;
    END
  END o[136]
  PIN o[137]
    DIRECTION OUTPUT ;
    USE SIGNAL ;
    PORT
      LAYER M4 ;
        RECT  0 15.456 0.192 15.48 ;
    END
  END o[137]
  PIN o[138]
    DIRECTION OUTPUT ;
    USE SIGNAL ;
    PORT
      LAYER M4 ;
        RECT  0 15.552 0.192 15.576 ;
    END
  END o[138]
  PIN o[139]
    DIRECTION OUTPUT ;
    USE SIGNAL ;
    PORT
      LAYER M4 ;
        RECT  0 15.648 0.192 15.672 ;
    END
  END o[139]
  PIN o[13]
    DIRECTION OUTPUT ;
    USE SIGNAL ;
    PORT
      LAYER M4 ;
        RECT  0 3.456 0.192 3.48 ;
    END
  END o[13]
  PIN o[140]
    DIRECTION OUTPUT ;
    USE SIGNAL ;
    PORT
      LAYER M4 ;
        RECT  0 15.744 0.192 15.768 ;
    END
  END o[140]
  PIN o[141]
    DIRECTION OUTPUT ;
    USE SIGNAL ;
    PORT
      LAYER M4 ;
        RECT  0 15.84 0.192 15.864 ;
    END
  END o[141]
  PIN o[142]
    DIRECTION OUTPUT ;
    USE SIGNAL ;
    PORT
      LAYER M4 ;
        RECT  0 15.936 0.192 15.96 ;
    END
  END o[142]
  PIN o[143]
    DIRECTION OUTPUT ;
    USE SIGNAL ;
    PORT
      LAYER M4 ;
        RECT  0 16.032 0.192 16.056 ;
    END
  END o[143]
  PIN o[144]
    DIRECTION OUTPUT ;
    USE SIGNAL ;
    PORT
      LAYER M4 ;
        RECT  0 16.128 0.192 16.152 ;
    END
  END o[144]
  PIN o[145]
    DIRECTION OUTPUT ;
    USE SIGNAL ;
    PORT
      LAYER M4 ;
        RECT  0 16.224 0.192 16.248 ;
    END
  END o[145]
  PIN o[146]
    DIRECTION OUTPUT ;
    USE SIGNAL ;
    PORT
      LAYER M4 ;
        RECT  0 16.32 0.192 16.344 ;
    END
  END o[146]
  PIN o[147]
    DIRECTION OUTPUT ;
    USE SIGNAL ;
    PORT
      LAYER M4 ;
        RECT  0 16.416 0.192 16.44 ;
    END
  END o[147]
  PIN o[148]
    DIRECTION OUTPUT ;
    USE SIGNAL ;
    PORT
      LAYER M4 ;
        RECT  0 16.512 0.192 16.536 ;
    END
  END o[148]
  PIN o[149]
    DIRECTION OUTPUT ;
    USE SIGNAL ;
    PORT
      LAYER M4 ;
        RECT  0 16.608 0.192 16.632 ;
    END
  END o[149]
  PIN o[14]
    DIRECTION OUTPUT ;
    USE SIGNAL ;
    PORT
      LAYER M4 ;
        RECT  0 3.552 0.192 3.576 ;
    END
  END o[14]
  PIN o[150]
    DIRECTION OUTPUT ;
    USE SIGNAL ;
    PORT
      LAYER M4 ;
        RECT  0 16.704 0.192 16.728 ;
    END
  END o[150]
  PIN o[151]
    DIRECTION OUTPUT ;
    USE SIGNAL ;
    PORT
      LAYER M4 ;
        RECT  0 16.848 0.192 16.872 ;
    END
  END o[151]
  PIN o[152]
    DIRECTION OUTPUT ;
    USE SIGNAL ;
    PORT
      LAYER M4 ;
        RECT  0 16.944 0.192 16.968 ;
    END
  END o[152]
  PIN o[153]
    DIRECTION OUTPUT ;
    USE SIGNAL ;
    PORT
      LAYER M4 ;
        RECT  0 17.04 0.192 17.064 ;
    END
  END o[153]
  PIN o[154]
    DIRECTION OUTPUT ;
    USE SIGNAL ;
    PORT
      LAYER M4 ;
        RECT  0 17.136 0.192 17.16 ;
    END
  END o[154]
  PIN o[155]
    DIRECTION OUTPUT ;
    USE SIGNAL ;
    PORT
      LAYER M4 ;
        RECT  0 17.232 0.192 17.256 ;
    END
  END o[155]
  PIN o[156]
    DIRECTION OUTPUT ;
    USE SIGNAL ;
    PORT
      LAYER M4 ;
        RECT  0 17.328 0.192 17.352 ;
    END
  END o[156]
  PIN o[157]
    DIRECTION OUTPUT ;
    USE SIGNAL ;
    PORT
      LAYER M4 ;
        RECT  0 17.424 0.192 17.448 ;
    END
  END o[157]
  PIN o[158]
    DIRECTION OUTPUT ;
    USE SIGNAL ;
    PORT
      LAYER M4 ;
        RECT  0 17.52 0.192 17.544 ;
    END
  END o[158]
  PIN o[159]
    DIRECTION OUTPUT ;
    USE SIGNAL ;
    PORT
      LAYER M4 ;
        RECT  0 17.616 0.192 17.64 ;
    END
  END o[159]
  PIN o[15]
    DIRECTION OUTPUT ;
    USE SIGNAL ;
    PORT
      LAYER M4 ;
        RECT  0 3.648 0.192 3.672 ;
    END
  END o[15]
  PIN o[160]
    DIRECTION OUTPUT ;
    USE SIGNAL ;
    PORT
      LAYER M4 ;
        RECT  0 17.712 0.192 17.736 ;
    END
  END o[160]
  PIN o[161]
    DIRECTION OUTPUT ;
    USE SIGNAL ;
    PORT
      LAYER M4 ;
        RECT  0 17.808 0.192 17.832 ;
    END
  END o[161]
  PIN o[162]
    DIRECTION OUTPUT ;
    USE SIGNAL ;
    PORT
      LAYER M4 ;
        RECT  0 17.904 0.192 17.928 ;
    END
  END o[162]
  PIN o[163]
    DIRECTION OUTPUT ;
    USE SIGNAL ;
    PORT
      LAYER M4 ;
        RECT  0 18 0.192 18.024 ;
    END
  END o[163]
  PIN o[164]
    DIRECTION OUTPUT ;
    USE SIGNAL ;
    PORT
      LAYER M4 ;
        RECT  0 18.096 0.192 18.12 ;
    END
  END o[164]
  PIN o[165]
    DIRECTION OUTPUT ;
    USE SIGNAL ;
    PORT
      LAYER M4 ;
        RECT  0 18.192 0.192 18.216 ;
    END
  END o[165]
  PIN o[166]
    DIRECTION OUTPUT ;
    USE SIGNAL ;
    PORT
      LAYER M4 ;
        RECT  0 18.288 0.192 18.312 ;
    END
  END o[166]
  PIN o[167]
    DIRECTION OUTPUT ;
    USE SIGNAL ;
    PORT
      LAYER M4 ;
        RECT  0 18.384 0.192 18.408 ;
    END
  END o[167]
  PIN o[168]
    DIRECTION OUTPUT ;
    USE SIGNAL ;
    PORT
      LAYER M4 ;
        RECT  0 18.48 0.192 18.504 ;
    END
  END o[168]
  PIN o[169]
    DIRECTION OUTPUT ;
    USE SIGNAL ;
    PORT
      LAYER M4 ;
        RECT  0 18.576 0.192 18.6 ;
    END
  END o[169]
  PIN o[16]
    DIRECTION OUTPUT ;
    USE SIGNAL ;
    PORT
      LAYER M4 ;
        RECT  0 3.744 0.192 3.768 ;
    END
  END o[16]
  PIN o[170]
    DIRECTION OUTPUT ;
    USE SIGNAL ;
    PORT
      LAYER M4 ;
        RECT  0 18.672 0.192 18.696 ;
    END
  END o[170]
  PIN o[171]
    DIRECTION OUTPUT ;
    USE SIGNAL ;
    PORT
      LAYER M4 ;
        RECT  0 18.768 0.192 18.792 ;
    END
  END o[171]
  PIN o[172]
    DIRECTION OUTPUT ;
    USE SIGNAL ;
    PORT
      LAYER M4 ;
        RECT  0 18.864 0.192 18.888 ;
    END
  END o[172]
  PIN o[173]
    DIRECTION OUTPUT ;
    USE SIGNAL ;
    PORT
      LAYER M4 ;
        RECT  0 18.96 0.192 18.984 ;
    END
  END o[173]
  PIN o[174]
    DIRECTION OUTPUT ;
    USE SIGNAL ;
    PORT
      LAYER M4 ;
        RECT  0 19.056 0.192 19.08 ;
    END
  END o[174]
  PIN o[175]
    DIRECTION OUTPUT ;
    USE SIGNAL ;
    PORT
      LAYER M4 ;
        RECT  0 19.152 0.192 19.176 ;
    END
  END o[175]
  PIN o[176]
    DIRECTION OUTPUT ;
    USE SIGNAL ;
    PORT
      LAYER M4 ;
        RECT  0 19.248 0.192 19.272 ;
    END
  END o[176]
  PIN o[177]
    DIRECTION OUTPUT ;
    USE SIGNAL ;
    PORT
      LAYER M4 ;
        RECT  0 19.344 0.192 19.368 ;
    END
  END o[177]
  PIN o[178]
    DIRECTION OUTPUT ;
    USE SIGNAL ;
    PORT
      LAYER M4 ;
        RECT  0 19.44 0.192 19.464 ;
    END
  END o[178]
  PIN o[179]
    DIRECTION OUTPUT ;
    USE SIGNAL ;
    PORT
      LAYER M4 ;
        RECT  0 19.536 0.192 19.56 ;
    END
  END o[179]
  PIN o[17]
    DIRECTION OUTPUT ;
    USE SIGNAL ;
    PORT
      LAYER M4 ;
        RECT  0 3.888 0.192 3.912 ;
    END
  END o[17]
  PIN o[180]
    DIRECTION OUTPUT ;
    USE SIGNAL ;
    PORT
      LAYER M4 ;
        RECT  0 19.632 0.192 19.656 ;
    END
  END o[180]
  PIN o[181]
    DIRECTION OUTPUT ;
    USE SIGNAL ;
    PORT
      LAYER M4 ;
        RECT  0 19.728 0.192 19.752 ;
    END
  END o[181]
  PIN o[182]
    DIRECTION OUTPUT ;
    USE SIGNAL ;
    PORT
      LAYER M4 ;
        RECT  0 19.824 0.192 19.848 ;
    END
  END o[182]
  PIN o[183]
    DIRECTION OUTPUT ;
    USE SIGNAL ;
    PORT
      LAYER M4 ;
        RECT  0 19.92 0.192 19.944 ;
    END
  END o[183]
  PIN o[184]
    DIRECTION OUTPUT ;
    USE SIGNAL ;
    PORT
      LAYER M4 ;
        RECT  0 20.016 0.192 20.04 ;
    END
  END o[184]
  PIN o[185]
    DIRECTION OUTPUT ;
    USE SIGNAL ;
    PORT
      LAYER M4 ;
        RECT  0 20.112 0.192 20.136 ;
    END
  END o[185]
  PIN o[186]
    DIRECTION OUTPUT ;
    USE SIGNAL ;
    PORT
      LAYER M4 ;
        RECT  0 20.208 0.192 20.232 ;
    END
  END o[186]
  PIN o[187]
    DIRECTION OUTPUT ;
    USE SIGNAL ;
    PORT
      LAYER M4 ;
        RECT  0 20.304 0.192 20.328 ;
    END
  END o[187]
  PIN o[188]
    DIRECTION OUTPUT ;
    USE SIGNAL ;
    PORT
      LAYER M4 ;
        RECT  0 20.4 0.192 20.424 ;
    END
  END o[188]
  PIN o[189]
    DIRECTION OUTPUT ;
    USE SIGNAL ;
    PORT
      LAYER M4 ;
        RECT  0 20.496 0.192 20.52 ;
    END
  END o[189]
  PIN o[18]
    DIRECTION OUTPUT ;
    USE SIGNAL ;
    PORT
      LAYER M4 ;
        RECT  0 3.984 0.192 4.008 ;
    END
  END o[18]
  PIN o[190]
    DIRECTION OUTPUT ;
    USE SIGNAL ;
    PORT
      LAYER M4 ;
        RECT  0 20.592 0.192 20.616 ;
    END
  END o[190]
  PIN o[191]
    DIRECTION OUTPUT ;
    USE SIGNAL ;
    PORT
      LAYER M4 ;
        RECT  0 20.688 0.192 20.712 ;
    END
  END o[191]
  PIN o[192]
    DIRECTION OUTPUT ;
    USE SIGNAL ;
    PORT
      LAYER M4 ;
        RECT  0 20.784 0.192 20.808 ;
    END
  END o[192]
  PIN o[193]
    DIRECTION OUTPUT ;
    USE SIGNAL ;
    PORT
      LAYER M4 ;
        RECT  0 20.88 0.192 20.904 ;
    END
  END o[193]
  PIN o[194]
    DIRECTION OUTPUT ;
    USE SIGNAL ;
    PORT
      LAYER M4 ;
        RECT  0 20.976 0.192 21 ;
    END
  END o[194]
  PIN o[195]
    DIRECTION OUTPUT ;
    USE SIGNAL ;
    PORT
      LAYER M4 ;
        RECT  0 21.072 0.192 21.096 ;
    END
  END o[195]
  PIN o[196]
    DIRECTION OUTPUT ;
    USE SIGNAL ;
    PORT
      LAYER M4 ;
        RECT  0 21.168 0.192 21.192 ;
    END
  END o[196]
  PIN o[197]
    DIRECTION OUTPUT ;
    USE SIGNAL ;
    PORT
      LAYER M4 ;
        RECT  0 21.264 0.192 21.288 ;
    END
  END o[197]
  PIN o[198]
    DIRECTION OUTPUT ;
    USE SIGNAL ;
    PORT
      LAYER M4 ;
        RECT  0 21.36 0.192 21.384 ;
    END
  END o[198]
  PIN o[199]
    DIRECTION OUTPUT ;
    USE SIGNAL ;
    PORT
      LAYER M4 ;
        RECT  0 21.456 0.192 21.48 ;
    END
  END o[199]
  PIN o[19]
    DIRECTION OUTPUT ;
    USE SIGNAL ;
    PORT
      LAYER M4 ;
        RECT  0 4.08 0.192 4.104 ;
    END
  END o[19]
  PIN o[1]
    DIRECTION OUTPUT ;
    USE SIGNAL ;
    PORT
      LAYER M4 ;
        RECT  0 2.304 0.192 2.328 ;
    END
  END o[1]
  PIN o[200]
    DIRECTION OUTPUT ;
    USE SIGNAL ;
    PORT
      LAYER M4 ;
        RECT  0 21.552 0.192 21.576 ;
    END
  END o[200]
  PIN o[201]
    DIRECTION OUTPUT ;
    USE SIGNAL ;
    PORT
      LAYER M4 ;
        RECT  0 21.648 0.192 21.672 ;
    END
  END o[201]
  PIN o[202]
    DIRECTION OUTPUT ;
    USE SIGNAL ;
    PORT
      LAYER M4 ;
        RECT  0 21.744 0.192 21.768 ;
    END
  END o[202]
  PIN o[203]
    DIRECTION OUTPUT ;
    USE SIGNAL ;
    PORT
      LAYER M4 ;
        RECT  0 21.84 0.192 21.864 ;
    END
  END o[203]
  PIN o[204]
    DIRECTION OUTPUT ;
    USE SIGNAL ;
    PORT
      LAYER M4 ;
        RECT  0 21.936 0.192 21.96 ;
    END
  END o[204]
  PIN o[205]
    DIRECTION OUTPUT ;
    USE SIGNAL ;
    PORT
      LAYER M4 ;
        RECT  0 22.032 0.192 22.056 ;
    END
  END o[205]
  PIN o[206]
    DIRECTION OUTPUT ;
    USE SIGNAL ;
    PORT
      LAYER M4 ;
        RECT  0 22.128 0.192 22.152 ;
    END
  END o[206]
  PIN o[207]
    DIRECTION OUTPUT ;
    USE SIGNAL ;
    PORT
      LAYER M4 ;
        RECT  0 22.224 0.192 22.248 ;
    END
  END o[207]
  PIN o[208]
    DIRECTION OUTPUT ;
    USE SIGNAL ;
    PORT
      LAYER M4 ;
        RECT  0 22.32 0.192 22.344 ;
    END
  END o[208]
  PIN o[209]
    DIRECTION OUTPUT ;
    USE SIGNAL ;
    PORT
      LAYER M4 ;
        RECT  0 22.416 0.192 22.44 ;
    END
  END o[209]
  PIN o[20]
    DIRECTION OUTPUT ;
    USE SIGNAL ;
    PORT
      LAYER M4 ;
        RECT  0 4.176 0.192 4.2 ;
    END
  END o[20]
  PIN o[210]
    DIRECTION OUTPUT ;
    USE SIGNAL ;
    PORT
      LAYER M4 ;
        RECT  0 22.512 0.192 22.536 ;
    END
  END o[210]
  PIN o[211]
    DIRECTION OUTPUT ;
    USE SIGNAL ;
    PORT
      LAYER M4 ;
        RECT  0 22.608 0.192 22.632 ;
    END
  END o[211]
  PIN o[212]
    DIRECTION OUTPUT ;
    USE SIGNAL ;
    PORT
      LAYER M4 ;
        RECT  0 22.704 0.192 22.728 ;
    END
  END o[212]
  PIN o[213]
    DIRECTION OUTPUT ;
    USE SIGNAL ;
    PORT
      LAYER M4 ;
        RECT  0 22.8 0.192 22.824 ;
    END
  END o[213]
  PIN o[214]
    DIRECTION OUTPUT ;
    USE SIGNAL ;
    PORT
      LAYER M4 ;
        RECT  0 22.896 0.192 22.92 ;
    END
  END o[214]
  PIN o[215]
    DIRECTION OUTPUT ;
    USE SIGNAL ;
    PORT
      LAYER M4 ;
        RECT  0 22.992 0.192 23.016 ;
    END
  END o[215]
  PIN o[216]
    DIRECTION OUTPUT ;
    USE SIGNAL ;
    PORT
      LAYER M4 ;
        RECT  0 23.088 0.192 23.112 ;
    END
  END o[216]
  PIN o[217]
    DIRECTION OUTPUT ;
    USE SIGNAL ;
    PORT
      LAYER M4 ;
        RECT  0 23.184 0.192 23.208 ;
    END
  END o[217]
  PIN o[218]
    DIRECTION OUTPUT ;
    USE SIGNAL ;
    PORT
      LAYER M4 ;
        RECT  0 23.328 0.192 23.352 ;
    END
  END o[218]
  PIN o[219]
    DIRECTION OUTPUT ;
    USE SIGNAL ;
    PORT
      LAYER M4 ;
        RECT  0 23.424 0.192 23.448 ;
    END
  END o[219]
  PIN o[21]
    DIRECTION OUTPUT ;
    USE SIGNAL ;
    PORT
      LAYER M4 ;
        RECT  0 4.272 0.192 4.296 ;
    END
  END o[21]
  PIN o[220]
    DIRECTION OUTPUT ;
    USE SIGNAL ;
    PORT
      LAYER M4 ;
        RECT  0 23.52 0.192 23.544 ;
    END
  END o[220]
  PIN o[221]
    DIRECTION OUTPUT ;
    USE SIGNAL ;
    PORT
      LAYER M4 ;
        RECT  0 23.616 0.192 23.64 ;
    END
  END o[221]
  PIN o[222]
    DIRECTION OUTPUT ;
    USE SIGNAL ;
    PORT
      LAYER M4 ;
        RECT  0 23.712 0.192 23.736 ;
    END
  END o[222]
  PIN o[223]
    DIRECTION OUTPUT ;
    USE SIGNAL ;
    PORT
      LAYER M4 ;
        RECT  0 23.808 0.192 23.832 ;
    END
  END o[223]
  PIN o[224]
    DIRECTION OUTPUT ;
    USE SIGNAL ;
    PORT
      LAYER M4 ;
        RECT  0 23.904 0.192 23.928 ;
    END
  END o[224]
  PIN o[225]
    DIRECTION OUTPUT ;
    USE SIGNAL ;
    PORT
      LAYER M4 ;
        RECT  0 24 0.192 24.024 ;
    END
  END o[225]
  PIN o[226]
    DIRECTION OUTPUT ;
    USE SIGNAL ;
    PORT
      LAYER M4 ;
        RECT  0 24.096 0.192 24.12 ;
    END
  END o[226]
  PIN o[227]
    DIRECTION OUTPUT ;
    USE SIGNAL ;
    PORT
      LAYER M4 ;
        RECT  0 24.192 0.192 24.216 ;
    END
  END o[227]
  PIN o[228]
    DIRECTION OUTPUT ;
    USE SIGNAL ;
    PORT
      LAYER M4 ;
        RECT  0 24.288 0.192 24.312 ;
    END
  END o[228]
  PIN o[229]
    DIRECTION OUTPUT ;
    USE SIGNAL ;
    PORT
      LAYER M4 ;
        RECT  0 24.384 0.192 24.408 ;
    END
  END o[229]
  PIN o[22]
    DIRECTION OUTPUT ;
    USE SIGNAL ;
    PORT
      LAYER M4 ;
        RECT  0 4.368 0.192 4.392 ;
    END
  END o[22]
  PIN o[230]
    DIRECTION OUTPUT ;
    USE SIGNAL ;
    PORT
      LAYER M4 ;
        RECT  0 24.48 0.192 24.504 ;
    END
  END o[230]
  PIN o[231]
    DIRECTION OUTPUT ;
    USE SIGNAL ;
    PORT
      LAYER M4 ;
        RECT  0 24.576 0.192 24.6 ;
    END
  END o[231]
  PIN o[232]
    DIRECTION OUTPUT ;
    USE SIGNAL ;
    PORT
      LAYER M4 ;
        RECT  0 24.672 0.192 24.696 ;
    END
  END o[232]
  PIN o[233]
    DIRECTION OUTPUT ;
    USE SIGNAL ;
    PORT
      LAYER M4 ;
        RECT  0 24.768 0.192 24.792 ;
    END
  END o[233]
  PIN o[234]
    DIRECTION OUTPUT ;
    USE SIGNAL ;
    PORT
      LAYER M4 ;
        RECT  0 24.864 0.192 24.888 ;
    END
  END o[234]
  PIN o[235]
    DIRECTION OUTPUT ;
    USE SIGNAL ;
    PORT
      LAYER M4 ;
        RECT  0 24.96 0.192 24.984 ;
    END
  END o[235]
  PIN o[236]
    DIRECTION OUTPUT ;
    USE SIGNAL ;
    PORT
      LAYER M4 ;
        RECT  0 25.056 0.192 25.08 ;
    END
  END o[236]
  PIN o[237]
    DIRECTION OUTPUT ;
    USE SIGNAL ;
    PORT
      LAYER M4 ;
        RECT  0 25.152 0.192 25.176 ;
    END
  END o[237]
  PIN o[238]
    DIRECTION OUTPUT ;
    USE SIGNAL ;
    PORT
      LAYER M4 ;
        RECT  0 25.248 0.192 25.272 ;
    END
  END o[238]
  PIN o[239]
    DIRECTION OUTPUT ;
    USE SIGNAL ;
    PORT
      LAYER M4 ;
        RECT  0 25.344 0.192 25.368 ;
    END
  END o[239]
  PIN o[23]
    DIRECTION OUTPUT ;
    USE SIGNAL ;
    PORT
      LAYER M4 ;
        RECT  0 4.464 0.192 4.488 ;
    END
  END o[23]
  PIN o[240]
    DIRECTION OUTPUT ;
    USE SIGNAL ;
    PORT
      LAYER M4 ;
        RECT  0 25.44 0.192 25.464 ;
    END
  END o[240]
  PIN o[241]
    DIRECTION OUTPUT ;
    USE SIGNAL ;
    PORT
      LAYER M4 ;
        RECT  0 25.536 0.192 25.56 ;
    END
  END o[241]
  PIN o[242]
    DIRECTION OUTPUT ;
    USE SIGNAL ;
    PORT
      LAYER M4 ;
        RECT  0 25.632 0.192 25.656 ;
    END
  END o[242]
  PIN o[243]
    DIRECTION OUTPUT ;
    USE SIGNAL ;
    PORT
      LAYER M4 ;
        RECT  0 25.728 0.192 25.752 ;
    END
  END o[243]
  PIN o[244]
    DIRECTION OUTPUT ;
    USE SIGNAL ;
    PORT
      LAYER M4 ;
        RECT  0 25.824 0.192 25.848 ;
    END
  END o[244]
  PIN o[245]
    DIRECTION OUTPUT ;
    USE SIGNAL ;
    PORT
      LAYER M4 ;
        RECT  0 25.92 0.192 25.944 ;
    END
  END o[245]
  PIN o[246]
    DIRECTION OUTPUT ;
    USE SIGNAL ;
    PORT
      LAYER M4 ;
        RECT  0 26.016 0.192 26.04 ;
    END
  END o[246]
  PIN o[247]
    DIRECTION OUTPUT ;
    USE SIGNAL ;
    PORT
      LAYER M4 ;
        RECT  0 26.112 0.192 26.136 ;
    END
  END o[247]
  PIN o[248]
    DIRECTION OUTPUT ;
    USE SIGNAL ;
    PORT
      LAYER M4 ;
        RECT  0 26.208 0.192 26.232 ;
    END
  END o[248]
  PIN o[249]
    DIRECTION OUTPUT ;
    USE SIGNAL ;
    PORT
      LAYER M4 ;
        RECT  0 26.304 0.192 26.328 ;
    END
  END o[249]
  PIN o[24]
    DIRECTION OUTPUT ;
    USE SIGNAL ;
    PORT
      LAYER M4 ;
        RECT  0 4.56 0.192 4.584 ;
    END
  END o[24]
  PIN o[250]
    DIRECTION OUTPUT ;
    USE SIGNAL ;
    PORT
      LAYER M4 ;
        RECT  0 26.4 0.192 26.424 ;
    END
  END o[250]
  PIN o[251]
    DIRECTION OUTPUT ;
    USE SIGNAL ;
    PORT
      LAYER M4 ;
        RECT  0 26.496 0.192 26.52 ;
    END
  END o[251]
  PIN o[252]
    DIRECTION OUTPUT ;
    USE SIGNAL ;
    PORT
      LAYER M4 ;
        RECT  0 26.592 0.192 26.616 ;
    END
  END o[252]
  PIN o[253]
    DIRECTION OUTPUT ;
    USE SIGNAL ;
    PORT
      LAYER M4 ;
        RECT  0 26.688 0.192 26.712 ;
    END
  END o[253]
  PIN o[254]
    DIRECTION OUTPUT ;
    USE SIGNAL ;
    PORT
      LAYER M4 ;
        RECT  0 26.784 0.192 26.808 ;
    END
  END o[254]
  PIN o[255]
    DIRECTION OUTPUT ;
    USE SIGNAL ;
    PORT
      LAYER M4 ;
        RECT  0 26.88 0.192 26.904 ;
    END
  END o[255]
  PIN o[256]
    DIRECTION OUTPUT ;
    USE SIGNAL ;
    PORT
      LAYER M4 ;
        RECT  0 26.976 0.192 27 ;
    END
  END o[256]
  PIN o[257]
    DIRECTION OUTPUT ;
    USE SIGNAL ;
    PORT
      LAYER M4 ;
        RECT  0 27.072 0.192 27.096 ;
    END
  END o[257]
  PIN o[258]
    DIRECTION OUTPUT ;
    USE SIGNAL ;
    PORT
      LAYER M4 ;
        RECT  0 27.168 0.192 27.192 ;
    END
  END o[258]
  PIN o[259]
    DIRECTION OUTPUT ;
    USE SIGNAL ;
    PORT
      LAYER M4 ;
        RECT  0 27.264 0.192 27.288 ;
    END
  END o[259]
  PIN o[25]
    DIRECTION OUTPUT ;
    USE SIGNAL ;
    PORT
      LAYER M4 ;
        RECT  0 4.656 0.192 4.68 ;
    END
  END o[25]
  PIN o[260]
    DIRECTION OUTPUT ;
    USE SIGNAL ;
    PORT
      LAYER M4 ;
        RECT  0 27.36 0.192 27.384 ;
    END
  END o[260]
  PIN o[261]
    DIRECTION OUTPUT ;
    USE SIGNAL ;
    PORT
      LAYER M4 ;
        RECT  0 27.456 0.192 27.48 ;
    END
  END o[261]
  PIN o[262]
    DIRECTION OUTPUT ;
    USE SIGNAL ;
    PORT
      LAYER M4 ;
        RECT  0 27.552 0.192 27.576 ;
    END
  END o[262]
  PIN o[263]
    DIRECTION OUTPUT ;
    USE SIGNAL ;
    PORT
      LAYER M4 ;
        RECT  0 27.648 0.192 27.672 ;
    END
  END o[263]
  PIN o[264]
    DIRECTION OUTPUT ;
    USE SIGNAL ;
    PORT
      LAYER M4 ;
        RECT  0 27.744 0.192 27.768 ;
    END
  END o[264]
  PIN o[265]
    DIRECTION OUTPUT ;
    USE SIGNAL ;
    PORT
      LAYER M4 ;
        RECT  0 27.84 0.192 27.864 ;
    END
  END o[265]
  PIN o[266]
    DIRECTION OUTPUT ;
    USE SIGNAL ;
    PORT
      LAYER M4 ;
        RECT  0 27.936 0.192 27.96 ;
    END
  END o[266]
  PIN o[267]
    DIRECTION OUTPUT ;
    USE SIGNAL ;
    PORT
      LAYER M4 ;
        RECT  0 28.032 0.192 28.056 ;
    END
  END o[267]
  PIN o[268]
    DIRECTION OUTPUT ;
    USE SIGNAL ;
    PORT
      LAYER M4 ;
        RECT  0 28.128 0.192 28.152 ;
    END
  END o[268]
  PIN o[269]
    DIRECTION OUTPUT ;
    USE SIGNAL ;
    PORT
      LAYER M4 ;
        RECT  0 28.224 0.192 28.248 ;
    END
  END o[269]
  PIN o[26]
    DIRECTION OUTPUT ;
    USE SIGNAL ;
    PORT
      LAYER M4 ;
        RECT  0 4.752 0.192 4.776 ;
    END
  END o[26]
  PIN o[270]
    DIRECTION OUTPUT ;
    USE SIGNAL ;
    PORT
      LAYER M4 ;
        RECT  0 28.32 0.192 28.344 ;
    END
  END o[270]
  PIN o[271]
    DIRECTION OUTPUT ;
    USE SIGNAL ;
    PORT
      LAYER M4 ;
        RECT  0 28.416 0.192 28.44 ;
    END
  END o[271]
  PIN o[272]
    DIRECTION OUTPUT ;
    USE SIGNAL ;
    PORT
      LAYER M4 ;
        RECT  0 28.512 0.192 28.536 ;
    END
  END o[272]
  PIN o[273]
    DIRECTION OUTPUT ;
    USE SIGNAL ;
    PORT
      LAYER M4 ;
        RECT  0 28.608 0.192 28.632 ;
    END
  END o[273]
  PIN o[274]
    DIRECTION OUTPUT ;
    USE SIGNAL ;
    PORT
      LAYER M4 ;
        RECT  0 28.704 0.192 28.728 ;
    END
  END o[274]
  PIN o[275]
    DIRECTION OUTPUT ;
    USE SIGNAL ;
    PORT
      LAYER M4 ;
        RECT  0 28.8 0.192 28.824 ;
    END
  END o[275]
  PIN o[276]
    DIRECTION OUTPUT ;
    USE SIGNAL ;
    PORT
      LAYER M4 ;
        RECT  0 28.896 0.192 28.92 ;
    END
  END o[276]
  PIN o[277]
    DIRECTION OUTPUT ;
    USE SIGNAL ;
    PORT
      LAYER M4 ;
        RECT  0 28.992 0.192 29.016 ;
    END
  END o[277]
  PIN o[278]
    DIRECTION OUTPUT ;
    USE SIGNAL ;
    PORT
      LAYER M4 ;
        RECT  0 29.088 0.192 29.112 ;
    END
  END o[278]
  PIN o[279]
    DIRECTION OUTPUT ;
    USE SIGNAL ;
    PORT
      LAYER M4 ;
        RECT  0 29.184 0.192 29.208 ;
    END
  END o[279]
  PIN o[27]
    DIRECTION OUTPUT ;
    USE SIGNAL ;
    PORT
      LAYER M4 ;
        RECT  0 4.848 0.192 4.872 ;
    END
  END o[27]
  PIN o[280]
    DIRECTION OUTPUT ;
    USE SIGNAL ;
    PORT
      LAYER M4 ;
        RECT  0 29.28 0.192 29.304 ;
    END
  END o[280]
  PIN o[281]
    DIRECTION OUTPUT ;
    USE SIGNAL ;
    PORT
      LAYER M4 ;
        RECT  0 29.376 0.192 29.4 ;
    END
  END o[281]
  PIN o[282]
    DIRECTION OUTPUT ;
    USE SIGNAL ;
    PORT
      LAYER M4 ;
        RECT  0 29.472 0.192 29.496 ;
    END
  END o[282]
  PIN o[283]
    DIRECTION OUTPUT ;
    USE SIGNAL ;
    PORT
      LAYER M4 ;
        RECT  0 29.568 0.192 29.592 ;
    END
  END o[283]
  PIN o[284]
    DIRECTION OUTPUT ;
    USE SIGNAL ;
    PORT
      LAYER M4 ;
        RECT  0 29.664 0.192 29.688 ;
    END
  END o[284]
  PIN o[285]
    DIRECTION OUTPUT ;
    USE SIGNAL ;
    PORT
      LAYER M4 ;
        RECT  0 29.808 0.192 29.832 ;
    END
  END o[285]
  PIN o[286]
    DIRECTION OUTPUT ;
    USE SIGNAL ;
    PORT
      LAYER M4 ;
        RECT  0 29.904 0.192 29.928 ;
    END
  END o[286]
  PIN o[287]
    DIRECTION OUTPUT ;
    USE SIGNAL ;
    PORT
      LAYER M4 ;
        RECT  0 30 0.192 30.024 ;
    END
  END o[287]
  PIN o[288]
    DIRECTION OUTPUT ;
    USE SIGNAL ;
    PORT
      LAYER M4 ;
        RECT  0 30.096 0.192 30.12 ;
    END
  END o[288]
  PIN o[289]
    DIRECTION OUTPUT ;
    USE SIGNAL ;
    PORT
      LAYER M4 ;
        RECT  0 30.192 0.192 30.216 ;
    END
  END o[289]
  PIN o[28]
    DIRECTION OUTPUT ;
    USE SIGNAL ;
    PORT
      LAYER M4 ;
        RECT  0 4.944 0.192 4.968 ;
    END
  END o[28]
  PIN o[290]
    DIRECTION OUTPUT ;
    USE SIGNAL ;
    PORT
      LAYER M4 ;
        RECT  0 30.288 0.192 30.312 ;
    END
  END o[290]
  PIN o[291]
    DIRECTION OUTPUT ;
    USE SIGNAL ;
    PORT
      LAYER M4 ;
        RECT  0 30.384 0.192 30.408 ;
    END
  END o[291]
  PIN o[292]
    DIRECTION OUTPUT ;
    USE SIGNAL ;
    PORT
      LAYER M4 ;
        RECT  0 30.48 0.192 30.504 ;
    END
  END o[292]
  PIN o[293]
    DIRECTION OUTPUT ;
    USE SIGNAL ;
    PORT
      LAYER M4 ;
        RECT  0 30.576 0.192 30.6 ;
    END
  END o[293]
  PIN o[294]
    DIRECTION OUTPUT ;
    USE SIGNAL ;
    PORT
      LAYER M4 ;
        RECT  0 30.672 0.192 30.696 ;
    END
  END o[294]
  PIN o[295]
    DIRECTION OUTPUT ;
    USE SIGNAL ;
    PORT
      LAYER M4 ;
        RECT  0 30.768 0.192 30.792 ;
    END
  END o[295]
  PIN o[296]
    DIRECTION OUTPUT ;
    USE SIGNAL ;
    PORT
      LAYER M4 ;
        RECT  0 30.864 0.192 30.888 ;
    END
  END o[296]
  PIN o[297]
    DIRECTION OUTPUT ;
    USE SIGNAL ;
    PORT
      LAYER M4 ;
        RECT  0 30.96 0.192 30.984 ;
    END
  END o[297]
  PIN o[298]
    DIRECTION OUTPUT ;
    USE SIGNAL ;
    PORT
      LAYER M4 ;
        RECT  0 31.056 0.192 31.08 ;
    END
  END o[298]
  PIN o[299]
    DIRECTION OUTPUT ;
    USE SIGNAL ;
    PORT
      LAYER M4 ;
        RECT  0 31.152 0.192 31.176 ;
    END
  END o[299]
  PIN o[29]
    DIRECTION OUTPUT ;
    USE SIGNAL ;
    PORT
      LAYER M4 ;
        RECT  0 5.04 0.192 5.064 ;
    END
  END o[29]
  PIN o[2]
    DIRECTION OUTPUT ;
    USE SIGNAL ;
    PORT
      LAYER M4 ;
        RECT  0 2.4 0.192 2.424 ;
    END
  END o[2]
  PIN o[300]
    DIRECTION OUTPUT ;
    USE SIGNAL ;
    PORT
      LAYER M4 ;
        RECT  0 31.248 0.192 31.272 ;
    END
  END o[300]
  PIN o[301]
    DIRECTION OUTPUT ;
    USE SIGNAL ;
    PORT
      LAYER M4 ;
        RECT  0 31.344 0.192 31.368 ;
    END
  END o[301]
  PIN o[302]
    DIRECTION OUTPUT ;
    USE SIGNAL ;
    PORT
      LAYER M4 ;
        RECT  0 31.44 0.192 31.464 ;
    END
  END o[302]
  PIN o[303]
    DIRECTION OUTPUT ;
    USE SIGNAL ;
    PORT
      LAYER M4 ;
        RECT  0 31.536 0.192 31.56 ;
    END
  END o[303]
  PIN o[304]
    DIRECTION OUTPUT ;
    USE SIGNAL ;
    PORT
      LAYER M4 ;
        RECT  0 31.632 0.192 31.656 ;
    END
  END o[304]
  PIN o[305]
    DIRECTION OUTPUT ;
    USE SIGNAL ;
    PORT
      LAYER M4 ;
        RECT  0 31.728 0.192 31.752 ;
    END
  END o[305]
  PIN o[306]
    DIRECTION OUTPUT ;
    USE SIGNAL ;
    PORT
      LAYER M4 ;
        RECT  0 31.824 0.192 31.848 ;
    END
  END o[306]
  PIN o[307]
    DIRECTION OUTPUT ;
    USE SIGNAL ;
    PORT
      LAYER M4 ;
        RECT  0 31.92 0.192 31.944 ;
    END
  END o[307]
  PIN o[308]
    DIRECTION OUTPUT ;
    USE SIGNAL ;
    PORT
      LAYER M4 ;
        RECT  0 32.016 0.192 32.04 ;
    END
  END o[308]
  PIN o[309]
    DIRECTION OUTPUT ;
    USE SIGNAL ;
    PORT
      LAYER M4 ;
        RECT  0 32.112 0.192 32.136 ;
    END
  END o[309]
  PIN o[30]
    DIRECTION OUTPUT ;
    USE SIGNAL ;
    PORT
      LAYER M4 ;
        RECT  0 5.136 0.192 5.16 ;
    END
  END o[30]
  PIN o[310]
    DIRECTION OUTPUT ;
    USE SIGNAL ;
    PORT
      LAYER M4 ;
        RECT  0 32.208 0.192 32.232 ;
    END
  END o[310]
  PIN o[311]
    DIRECTION OUTPUT ;
    USE SIGNAL ;
    PORT
      LAYER M4 ;
        RECT  0 32.304 0.192 32.328 ;
    END
  END o[311]
  PIN o[312]
    DIRECTION OUTPUT ;
    USE SIGNAL ;
    PORT
      LAYER M4 ;
        RECT  0 32.4 0.192 32.424 ;
    END
  END o[312]
  PIN o[313]
    DIRECTION OUTPUT ;
    USE SIGNAL ;
    PORT
      LAYER M4 ;
        RECT  0 32.496 0.192 32.52 ;
    END
  END o[313]
  PIN o[314]
    DIRECTION OUTPUT ;
    USE SIGNAL ;
    PORT
      LAYER M4 ;
        RECT  0 32.592 0.192 32.616 ;
    END
  END o[314]
  PIN o[315]
    DIRECTION OUTPUT ;
    USE SIGNAL ;
    PORT
      LAYER M4 ;
        RECT  0 32.688 0.192 32.712 ;
    END
  END o[315]
  PIN o[316]
    DIRECTION OUTPUT ;
    USE SIGNAL ;
    PORT
      LAYER M4 ;
        RECT  0 32.784 0.192 32.808 ;
    END
  END o[316]
  PIN o[317]
    DIRECTION OUTPUT ;
    USE SIGNAL ;
    PORT
      LAYER M4 ;
        RECT  0 32.88 0.192 32.904 ;
    END
  END o[317]
  PIN o[318]
    DIRECTION OUTPUT ;
    USE SIGNAL ;
    PORT
      LAYER M4 ;
        RECT  0 32.976 0.192 33 ;
    END
  END o[318]
  PIN o[319]
    DIRECTION OUTPUT ;
    USE SIGNAL ;
    PORT
      LAYER M4 ;
        RECT  0 33.072 0.192 33.096 ;
    END
  END o[319]
  PIN o[31]
    DIRECTION OUTPUT ;
    USE SIGNAL ;
    PORT
      LAYER M4 ;
        RECT  0 5.232 0.192 5.256 ;
    END
  END o[31]
  PIN o[320]
    DIRECTION OUTPUT ;
    USE SIGNAL ;
    PORT
      LAYER M4 ;
        RECT  0 33.168 0.192 33.192 ;
    END
  END o[320]
  PIN o[321]
    DIRECTION OUTPUT ;
    USE SIGNAL ;
    PORT
      LAYER M4 ;
        RECT  0 33.264 0.192 33.288 ;
    END
  END o[321]
  PIN o[322]
    DIRECTION OUTPUT ;
    USE SIGNAL ;
    PORT
      LAYER M4 ;
        RECT  0 33.36 0.192 33.384 ;
    END
  END o[322]
  PIN o[323]
    DIRECTION OUTPUT ;
    USE SIGNAL ;
    PORT
      LAYER M4 ;
        RECT  0 33.456 0.192 33.48 ;
    END
  END o[323]
  PIN o[324]
    DIRECTION OUTPUT ;
    USE SIGNAL ;
    PORT
      LAYER M4 ;
        RECT  0 33.552 0.192 33.576 ;
    END
  END o[324]
  PIN o[325]
    DIRECTION OUTPUT ;
    USE SIGNAL ;
    PORT
      LAYER M4 ;
        RECT  0 33.648 0.192 33.672 ;
    END
  END o[325]
  PIN o[326]
    DIRECTION OUTPUT ;
    USE SIGNAL ;
    PORT
      LAYER M4 ;
        RECT  0 33.744 0.192 33.768 ;
    END
  END o[326]
  PIN o[327]
    DIRECTION OUTPUT ;
    USE SIGNAL ;
    PORT
      LAYER M4 ;
        RECT  0 33.84 0.192 33.864 ;
    END
  END o[327]
  PIN o[328]
    DIRECTION OUTPUT ;
    USE SIGNAL ;
    PORT
      LAYER M4 ;
        RECT  0 33.936 0.192 33.96 ;
    END
  END o[328]
  PIN o[329]
    DIRECTION OUTPUT ;
    USE SIGNAL ;
    PORT
      LAYER M4 ;
        RECT  0 34.032 0.192 34.056 ;
    END
  END o[329]
  PIN o[32]
    DIRECTION OUTPUT ;
    USE SIGNAL ;
    PORT
      LAYER M4 ;
        RECT  0 5.328 0.192 5.352 ;
    END
  END o[32]
  PIN o[330]
    DIRECTION OUTPUT ;
    USE SIGNAL ;
    PORT
      LAYER M4 ;
        RECT  0 34.128 0.192 34.152 ;
    END
  END o[330]
  PIN o[331]
    DIRECTION OUTPUT ;
    USE SIGNAL ;
    PORT
      LAYER M4 ;
        RECT  0 34.224 0.192 34.248 ;
    END
  END o[331]
  PIN o[332]
    DIRECTION OUTPUT ;
    USE SIGNAL ;
    PORT
      LAYER M4 ;
        RECT  0 34.32 0.192 34.344 ;
    END
  END o[332]
  PIN o[333]
    DIRECTION OUTPUT ;
    USE SIGNAL ;
    PORT
      LAYER M4 ;
        RECT  0 34.416 0.192 34.44 ;
    END
  END o[333]
  PIN o[334]
    DIRECTION OUTPUT ;
    USE SIGNAL ;
    PORT
      LAYER M4 ;
        RECT  0 34.512 0.192 34.536 ;
    END
  END o[334]
  PIN o[335]
    DIRECTION OUTPUT ;
    USE SIGNAL ;
    PORT
      LAYER M4 ;
        RECT  0 34.608 0.192 34.632 ;
    END
  END o[335]
  PIN o[336]
    DIRECTION OUTPUT ;
    USE SIGNAL ;
    PORT
      LAYER M4 ;
        RECT  0 34.704 0.192 34.728 ;
    END
  END o[336]
  PIN o[337]
    DIRECTION OUTPUT ;
    USE SIGNAL ;
    PORT
      LAYER M4 ;
        RECT  0 34.8 0.192 34.824 ;
    END
  END o[337]
  PIN o[338]
    DIRECTION OUTPUT ;
    USE SIGNAL ;
    PORT
      LAYER M4 ;
        RECT  0 34.896 0.192 34.92 ;
    END
  END o[338]
  PIN o[339]
    DIRECTION OUTPUT ;
    USE SIGNAL ;
    PORT
      LAYER M4 ;
        RECT  0 34.992 0.192 35.016 ;
    END
  END o[339]
  PIN o[33]
    DIRECTION OUTPUT ;
    USE SIGNAL ;
    PORT
      LAYER M4 ;
        RECT  0 5.424 0.192 5.448 ;
    END
  END o[33]
  PIN o[340]
    DIRECTION OUTPUT ;
    USE SIGNAL ;
    PORT
      LAYER M4 ;
        RECT  0 35.088 0.192 35.112 ;
    END
  END o[340]
  PIN o[341]
    DIRECTION OUTPUT ;
    USE SIGNAL ;
    PORT
      LAYER M4 ;
        RECT  0 35.184 0.192 35.208 ;
    END
  END o[341]
  PIN o[342]
    DIRECTION OUTPUT ;
    USE SIGNAL ;
    PORT
      LAYER M4 ;
        RECT  0 35.28 0.192 35.304 ;
    END
  END o[342]
  PIN o[343]
    DIRECTION OUTPUT ;
    USE SIGNAL ;
    PORT
      LAYER M4 ;
        RECT  0 35.376 0.192 35.4 ;
    END
  END o[343]
  PIN o[344]
    DIRECTION OUTPUT ;
    USE SIGNAL ;
    PORT
      LAYER M4 ;
        RECT  0 35.472 0.192 35.496 ;
    END
  END o[344]
  PIN o[345]
    DIRECTION OUTPUT ;
    USE SIGNAL ;
    PORT
      LAYER M4 ;
        RECT  0 35.568 0.192 35.592 ;
    END
  END o[345]
  PIN o[346]
    DIRECTION OUTPUT ;
    USE SIGNAL ;
    PORT
      LAYER M4 ;
        RECT  0 35.664 0.192 35.688 ;
    END
  END o[346]
  PIN o[347]
    DIRECTION OUTPUT ;
    USE SIGNAL ;
    PORT
      LAYER M4 ;
        RECT  0 35.76 0.192 35.784 ;
    END
  END o[347]
  PIN o[348]
    DIRECTION OUTPUT ;
    USE SIGNAL ;
    PORT
      LAYER M4 ;
        RECT  0 35.856 0.192 35.88 ;
    END
  END o[348]
  PIN o[349]
    DIRECTION OUTPUT ;
    USE SIGNAL ;
    PORT
      LAYER M4 ;
        RECT  0 35.952 0.192 35.976 ;
    END
  END o[349]
  PIN o[34]
    DIRECTION OUTPUT ;
    USE SIGNAL ;
    PORT
      LAYER M4 ;
        RECT  0 5.52 0.192 5.544 ;
    END
  END o[34]
  PIN o[350]
    DIRECTION OUTPUT ;
    USE SIGNAL ;
    PORT
      LAYER M4 ;
        RECT  0 36.048 0.192 36.072 ;
    END
  END o[350]
  PIN o[351]
    DIRECTION OUTPUT ;
    USE SIGNAL ;
    PORT
      LAYER M4 ;
        RECT  0 36.144 0.192 36.168 ;
    END
  END o[351]
  PIN o[352]
    DIRECTION OUTPUT ;
    USE SIGNAL ;
    PORT
      LAYER M4 ;
        RECT  0 36.288 0.192 36.312 ;
    END
  END o[352]
  PIN o[353]
    DIRECTION OUTPUT ;
    USE SIGNAL ;
    PORT
      LAYER M4 ;
        RECT  0 36.384 0.192 36.408 ;
    END
  END o[353]
  PIN o[354]
    DIRECTION OUTPUT ;
    USE SIGNAL ;
    PORT
      LAYER M4 ;
        RECT  0 36.48 0.192 36.504 ;
    END
  END o[354]
  PIN o[355]
    DIRECTION OUTPUT ;
    USE SIGNAL ;
    PORT
      LAYER M4 ;
        RECT  0 36.576 0.192 36.6 ;
    END
  END o[355]
  PIN o[356]
    DIRECTION OUTPUT ;
    USE SIGNAL ;
    PORT
      LAYER M4 ;
        RECT  0 36.672 0.192 36.696 ;
    END
  END o[356]
  PIN o[357]
    DIRECTION OUTPUT ;
    USE SIGNAL ;
    PORT
      LAYER M4 ;
        RECT  0 36.768 0.192 36.792 ;
    END
  END o[357]
  PIN o[358]
    DIRECTION OUTPUT ;
    USE SIGNAL ;
    PORT
      LAYER M4 ;
        RECT  0 36.864 0.192 36.888 ;
    END
  END o[358]
  PIN o[359]
    DIRECTION OUTPUT ;
    USE SIGNAL ;
    PORT
      LAYER M4 ;
        RECT  0 36.96 0.192 36.984 ;
    END
  END o[359]
  PIN o[35]
    DIRECTION OUTPUT ;
    USE SIGNAL ;
    PORT
      LAYER M4 ;
        RECT  0 5.616 0.192 5.64 ;
    END
  END o[35]
  PIN o[360]
    DIRECTION OUTPUT ;
    USE SIGNAL ;
    PORT
      LAYER M4 ;
        RECT  0 37.056 0.192 37.08 ;
    END
  END o[360]
  PIN o[361]
    DIRECTION OUTPUT ;
    USE SIGNAL ;
    PORT
      LAYER M4 ;
        RECT  0 37.152 0.192 37.176 ;
    END
  END o[361]
  PIN o[362]
    DIRECTION OUTPUT ;
    USE SIGNAL ;
    PORT
      LAYER M4 ;
        RECT  0 37.248 0.192 37.272 ;
    END
  END o[362]
  PIN o[363]
    DIRECTION OUTPUT ;
    USE SIGNAL ;
    PORT
      LAYER M4 ;
        RECT  0 37.344 0.192 37.368 ;
    END
  END o[363]
  PIN o[364]
    DIRECTION OUTPUT ;
    USE SIGNAL ;
    PORT
      LAYER M4 ;
        RECT  0 37.44 0.192 37.464 ;
    END
  END o[364]
  PIN o[365]
    DIRECTION OUTPUT ;
    USE SIGNAL ;
    PORT
      LAYER M4 ;
        RECT  0 37.536 0.192 37.56 ;
    END
  END o[365]
  PIN o[366]
    DIRECTION OUTPUT ;
    USE SIGNAL ;
    PORT
      LAYER M4 ;
        RECT  0 37.632 0.192 37.656 ;
    END
  END o[366]
  PIN o[367]
    DIRECTION OUTPUT ;
    USE SIGNAL ;
    PORT
      LAYER M4 ;
        RECT  0 37.728 0.192 37.752 ;
    END
  END o[367]
  PIN o[368]
    DIRECTION OUTPUT ;
    USE SIGNAL ;
    PORT
      LAYER M4 ;
        RECT  0 37.824 0.192 37.848 ;
    END
  END o[368]
  PIN o[369]
    DIRECTION OUTPUT ;
    USE SIGNAL ;
    PORT
      LAYER M4 ;
        RECT  0 37.92 0.192 37.944 ;
    END
  END o[369]
  PIN o[36]
    DIRECTION OUTPUT ;
    USE SIGNAL ;
    PORT
      LAYER M4 ;
        RECT  0 5.712 0.192 5.736 ;
    END
  END o[36]
  PIN o[370]
    DIRECTION OUTPUT ;
    USE SIGNAL ;
    PORT
      LAYER M4 ;
        RECT  0 38.016 0.192 38.04 ;
    END
  END o[370]
  PIN o[371]
    DIRECTION OUTPUT ;
    USE SIGNAL ;
    PORT
      LAYER M4 ;
        RECT  0 38.112 0.192 38.136 ;
    END
  END o[371]
  PIN o[372]
    DIRECTION OUTPUT ;
    USE SIGNAL ;
    PORT
      LAYER M4 ;
        RECT  0 38.208 0.192 38.232 ;
    END
  END o[372]
  PIN o[373]
    DIRECTION OUTPUT ;
    USE SIGNAL ;
    PORT
      LAYER M4 ;
        RECT  0 38.304 0.192 38.328 ;
    END
  END o[373]
  PIN o[374]
    DIRECTION OUTPUT ;
    USE SIGNAL ;
    PORT
      LAYER M4 ;
        RECT  0 38.4 0.192 38.424 ;
    END
  END o[374]
  PIN o[375]
    DIRECTION OUTPUT ;
    USE SIGNAL ;
    PORT
      LAYER M4 ;
        RECT  0 38.496 0.192 38.52 ;
    END
  END o[375]
  PIN o[376]
    DIRECTION OUTPUT ;
    USE SIGNAL ;
    PORT
      LAYER M4 ;
        RECT  0 38.592 0.192 38.616 ;
    END
  END o[376]
  PIN o[377]
    DIRECTION OUTPUT ;
    USE SIGNAL ;
    PORT
      LAYER M4 ;
        RECT  0 38.688 0.192 38.712 ;
    END
  END o[377]
  PIN o[378]
    DIRECTION OUTPUT ;
    USE SIGNAL ;
    PORT
      LAYER M4 ;
        RECT  0 38.784 0.192 38.808 ;
    END
  END o[378]
  PIN o[379]
    DIRECTION OUTPUT ;
    USE SIGNAL ;
    PORT
      LAYER M4 ;
        RECT  0 38.88 0.192 38.904 ;
    END
  END o[379]
  PIN o[37]
    DIRECTION OUTPUT ;
    USE SIGNAL ;
    PORT
      LAYER M4 ;
        RECT  0 5.808 0.192 5.832 ;
    END
  END o[37]
  PIN o[380]
    DIRECTION OUTPUT ;
    USE SIGNAL ;
    PORT
      LAYER M4 ;
        RECT  0 38.976 0.192 39 ;
    END
  END o[380]
  PIN o[381]
    DIRECTION OUTPUT ;
    USE SIGNAL ;
    PORT
      LAYER M4 ;
        RECT  0 39.072 0.192 39.096 ;
    END
  END o[381]
  PIN o[382]
    DIRECTION OUTPUT ;
    USE SIGNAL ;
    PORT
      LAYER M4 ;
        RECT  0 39.168 0.192 39.192 ;
    END
  END o[382]
  PIN o[383]
    DIRECTION OUTPUT ;
    USE SIGNAL ;
    PORT
      LAYER M4 ;
        RECT  0 39.264 0.192 39.288 ;
    END
  END o[383]
  PIN o[384]
    DIRECTION OUTPUT ;
    USE SIGNAL ;
    PORT
      LAYER M4 ;
        RECT  0 39.36 0.192 39.384 ;
    END
  END o[384]
  PIN o[385]
    DIRECTION OUTPUT ;
    USE SIGNAL ;
    PORT
      LAYER M4 ;
        RECT  0 39.456 0.192 39.48 ;
    END
  END o[385]
  PIN o[386]
    DIRECTION OUTPUT ;
    USE SIGNAL ;
    PORT
      LAYER M4 ;
        RECT  0 39.552 0.192 39.576 ;
    END
  END o[386]
  PIN o[387]
    DIRECTION OUTPUT ;
    USE SIGNAL ;
    PORT
      LAYER M4 ;
        RECT  0 39.648 0.192 39.672 ;
    END
  END o[387]
  PIN o[388]
    DIRECTION OUTPUT ;
    USE SIGNAL ;
    PORT
      LAYER M4 ;
        RECT  0 39.744 0.192 39.768 ;
    END
  END o[388]
  PIN o[389]
    DIRECTION OUTPUT ;
    USE SIGNAL ;
    PORT
      LAYER M4 ;
        RECT  0 39.84 0.192 39.864 ;
    END
  END o[389]
  PIN o[38]
    DIRECTION OUTPUT ;
    USE SIGNAL ;
    PORT
      LAYER M4 ;
        RECT  0 5.904 0.192 5.928 ;
    END
  END o[38]
  PIN o[390]
    DIRECTION OUTPUT ;
    USE SIGNAL ;
    PORT
      LAYER M4 ;
        RECT  0 39.936 0.192 39.96 ;
    END
  END o[390]
  PIN o[391]
    DIRECTION OUTPUT ;
    USE SIGNAL ;
    PORT
      LAYER M4 ;
        RECT  0 40.032 0.192 40.056 ;
    END
  END o[391]
  PIN o[392]
    DIRECTION OUTPUT ;
    USE SIGNAL ;
    PORT
      LAYER M4 ;
        RECT  0 40.128 0.192 40.152 ;
    END
  END o[392]
  PIN o[393]
    DIRECTION OUTPUT ;
    USE SIGNAL ;
    PORT
      LAYER M4 ;
        RECT  0 40.224 0.192 40.248 ;
    END
  END o[393]
  PIN o[394]
    DIRECTION OUTPUT ;
    USE SIGNAL ;
    PORT
      LAYER M4 ;
        RECT  0 40.32 0.192 40.344 ;
    END
  END o[394]
  PIN o[395]
    DIRECTION OUTPUT ;
    USE SIGNAL ;
    PORT
      LAYER M4 ;
        RECT  0 40.416 0.192 40.44 ;
    END
  END o[395]
  PIN o[396]
    DIRECTION OUTPUT ;
    USE SIGNAL ;
    PORT
      LAYER M4 ;
        RECT  0 40.512 0.192 40.536 ;
    END
  END o[396]
  PIN o[397]
    DIRECTION OUTPUT ;
    USE SIGNAL ;
    PORT
      LAYER M4 ;
        RECT  0 40.608 0.192 40.632 ;
    END
  END o[397]
  PIN o[398]
    DIRECTION OUTPUT ;
    USE SIGNAL ;
    PORT
      LAYER M4 ;
        RECT  0 40.704 0.192 40.728 ;
    END
  END o[398]
  PIN o[399]
    DIRECTION OUTPUT ;
    USE SIGNAL ;
    PORT
      LAYER M4 ;
        RECT  0 40.8 0.192 40.824 ;
    END
  END o[399]
  PIN o[39]
    DIRECTION OUTPUT ;
    USE SIGNAL ;
    PORT
      LAYER M4 ;
        RECT  0 6 0.192 6.024 ;
    END
  END o[39]
  PIN o[3]
    DIRECTION OUTPUT ;
    USE SIGNAL ;
    PORT
      LAYER M4 ;
        RECT  0 2.496 0.192 2.52 ;
    END
  END o[3]
  PIN o[400]
    DIRECTION OUTPUT ;
    USE SIGNAL ;
    PORT
      LAYER M4 ;
        RECT  0 40.896 0.192 40.92 ;
    END
  END o[400]
  PIN o[401]
    DIRECTION OUTPUT ;
    USE SIGNAL ;
    PORT
      LAYER M4 ;
        RECT  0 40.992 0.192 41.016 ;
    END
  END o[401]
  PIN o[402]
    DIRECTION OUTPUT ;
    USE SIGNAL ;
    PORT
      LAYER M4 ;
        RECT  0 41.088 0.192 41.112 ;
    END
  END o[402]
  PIN o[403]
    DIRECTION OUTPUT ;
    USE SIGNAL ;
    PORT
      LAYER M4 ;
        RECT  0 41.184 0.192 41.208 ;
    END
  END o[403]
  PIN o[404]
    DIRECTION OUTPUT ;
    USE SIGNAL ;
    PORT
      LAYER M4 ;
        RECT  0 41.28 0.192 41.304 ;
    END
  END o[404]
  PIN o[405]
    DIRECTION OUTPUT ;
    USE SIGNAL ;
    PORT
      LAYER M4 ;
        RECT  0 41.376 0.192 41.4 ;
    END
  END o[405]
  PIN o[406]
    DIRECTION OUTPUT ;
    USE SIGNAL ;
    PORT
      LAYER M4 ;
        RECT  0 41.472 0.192 41.496 ;
    END
  END o[406]
  PIN o[407]
    DIRECTION OUTPUT ;
    USE SIGNAL ;
    PORT
      LAYER M4 ;
        RECT  0 41.568 0.192 41.592 ;
    END
  END o[407]
  PIN o[408]
    DIRECTION OUTPUT ;
    USE SIGNAL ;
    PORT
      LAYER M4 ;
        RECT  0 41.664 0.192 41.688 ;
    END
  END o[408]
  PIN o[409]
    DIRECTION OUTPUT ;
    USE SIGNAL ;
    PORT
      LAYER M4 ;
        RECT  0 41.76 0.192 41.784 ;
    END
  END o[409]
  PIN o[40]
    DIRECTION OUTPUT ;
    USE SIGNAL ;
    PORT
      LAYER M4 ;
        RECT  0 6.096 0.192 6.12 ;
    END
  END o[40]
  PIN o[410]
    DIRECTION OUTPUT ;
    USE SIGNAL ;
    PORT
      LAYER M4 ;
        RECT  0 41.856 0.192 41.88 ;
    END
  END o[410]
  PIN o[411]
    DIRECTION OUTPUT ;
    USE SIGNAL ;
    PORT
      LAYER M4 ;
        RECT  0 41.952 0.192 41.976 ;
    END
  END o[411]
  PIN o[412]
    DIRECTION OUTPUT ;
    USE SIGNAL ;
    PORT
      LAYER M4 ;
        RECT  0 42.048 0.192 42.072 ;
    END
  END o[412]
  PIN o[413]
    DIRECTION OUTPUT ;
    USE SIGNAL ;
    PORT
      LAYER M4 ;
        RECT  0 42.144 0.192 42.168 ;
    END
  END o[413]
  PIN o[414]
    DIRECTION OUTPUT ;
    USE SIGNAL ;
    PORT
      LAYER M4 ;
        RECT  0 42.24 0.192 42.264 ;
    END
  END o[414]
  PIN o[415]
    DIRECTION OUTPUT ;
    USE SIGNAL ;
    PORT
      LAYER M4 ;
        RECT  0 42.336 0.192 42.36 ;
    END
  END o[415]
  PIN o[416]
    DIRECTION OUTPUT ;
    USE SIGNAL ;
    PORT
      LAYER M4 ;
        RECT  0 42.432 0.192 42.456 ;
    END
  END o[416]
  PIN o[417]
    DIRECTION OUTPUT ;
    USE SIGNAL ;
    PORT
      LAYER M4 ;
        RECT  0 42.528 0.192 42.552 ;
    END
  END o[417]
  PIN o[418]
    DIRECTION OUTPUT ;
    USE SIGNAL ;
    PORT
      LAYER M4 ;
        RECT  0 42.624 0.192 42.648 ;
    END
  END o[418]
  PIN o[419]
    DIRECTION OUTPUT ;
    USE SIGNAL ;
    PORT
      LAYER M4 ;
        RECT  0 42.768 0.192 42.792 ;
    END
  END o[419]
  PIN o[41]
    DIRECTION OUTPUT ;
    USE SIGNAL ;
    PORT
      LAYER M4 ;
        RECT  0 6.192 0.192 6.216 ;
    END
  END o[41]
  PIN o[420]
    DIRECTION OUTPUT ;
    USE SIGNAL ;
    PORT
      LAYER M4 ;
        RECT  0 42.864 0.192 42.888 ;
    END
  END o[420]
  PIN o[421]
    DIRECTION OUTPUT ;
    USE SIGNAL ;
    PORT
      LAYER M4 ;
        RECT  0 42.96 0.192 42.984 ;
    END
  END o[421]
  PIN o[422]
    DIRECTION OUTPUT ;
    USE SIGNAL ;
    PORT
      LAYER M4 ;
        RECT  0 43.056 0.192 43.08 ;
    END
  END o[422]
  PIN o[423]
    DIRECTION OUTPUT ;
    USE SIGNAL ;
    PORT
      LAYER M4 ;
        RECT  0 43.152 0.192 43.176 ;
    END
  END o[423]
  PIN o[424]
    DIRECTION OUTPUT ;
    USE SIGNAL ;
    PORT
      LAYER M4 ;
        RECT  0 43.248 0.192 43.272 ;
    END
  END o[424]
  PIN o[425]
    DIRECTION OUTPUT ;
    USE SIGNAL ;
    PORT
      LAYER M4 ;
        RECT  0 43.344 0.192 43.368 ;
    END
  END o[425]
  PIN o[426]
    DIRECTION OUTPUT ;
    USE SIGNAL ;
    PORT
      LAYER M4 ;
        RECT  0 43.44 0.192 43.464 ;
    END
  END o[426]
  PIN o[427]
    DIRECTION OUTPUT ;
    USE SIGNAL ;
    PORT
      LAYER M4 ;
        RECT  0 43.536 0.192 43.56 ;
    END
  END o[427]
  PIN o[428]
    DIRECTION OUTPUT ;
    USE SIGNAL ;
    PORT
      LAYER M4 ;
        RECT  0 43.632 0.192 43.656 ;
    END
  END o[428]
  PIN o[429]
    DIRECTION OUTPUT ;
    USE SIGNAL ;
    PORT
      LAYER M4 ;
        RECT  0 43.728 0.192 43.752 ;
    END
  END o[429]
  PIN o[42]
    DIRECTION OUTPUT ;
    USE SIGNAL ;
    PORT
      LAYER M4 ;
        RECT  0 6.288 0.192 6.312 ;
    END
  END o[42]
  PIN o[430]
    DIRECTION OUTPUT ;
    USE SIGNAL ;
    PORT
      LAYER M4 ;
        RECT  0 43.824 0.192 43.848 ;
    END
  END o[430]
  PIN o[431]
    DIRECTION OUTPUT ;
    USE SIGNAL ;
    PORT
      LAYER M4 ;
        RECT  0 43.92 0.192 43.944 ;
    END
  END o[431]
  PIN o[432]
    DIRECTION OUTPUT ;
    USE SIGNAL ;
    PORT
      LAYER M4 ;
        RECT  0 44.016 0.192 44.04 ;
    END
  END o[432]
  PIN o[433]
    DIRECTION OUTPUT ;
    USE SIGNAL ;
    PORT
      LAYER M4 ;
        RECT  0 44.112 0.192 44.136 ;
    END
  END o[433]
  PIN o[434]
    DIRECTION OUTPUT ;
    USE SIGNAL ;
    PORT
      LAYER M4 ;
        RECT  0 44.208 0.192 44.232 ;
    END
  END o[434]
  PIN o[435]
    DIRECTION OUTPUT ;
    USE SIGNAL ;
    PORT
      LAYER M4 ;
        RECT  0 44.304 0.192 44.328 ;
    END
  END o[435]
  PIN o[436]
    DIRECTION OUTPUT ;
    USE SIGNAL ;
    PORT
      LAYER M4 ;
        RECT  0 44.4 0.192 44.424 ;
    END
  END o[436]
  PIN o[437]
    DIRECTION OUTPUT ;
    USE SIGNAL ;
    PORT
      LAYER M4 ;
        RECT  0 44.496 0.192 44.52 ;
    END
  END o[437]
  PIN o[438]
    DIRECTION OUTPUT ;
    USE SIGNAL ;
    PORT
      LAYER M4 ;
        RECT  0 44.592 0.192 44.616 ;
    END
  END o[438]
  PIN o[439]
    DIRECTION OUTPUT ;
    USE SIGNAL ;
    PORT
      LAYER M4 ;
        RECT  0 44.688 0.192 44.712 ;
    END
  END o[439]
  PIN o[43]
    DIRECTION OUTPUT ;
    USE SIGNAL ;
    PORT
      LAYER M4 ;
        RECT  0 6.384 0.192 6.408 ;
    END
  END o[43]
  PIN o[440]
    DIRECTION OUTPUT ;
    USE SIGNAL ;
    PORT
      LAYER M4 ;
        RECT  0 44.784 0.192 44.808 ;
    END
  END o[440]
  PIN o[441]
    DIRECTION OUTPUT ;
    USE SIGNAL ;
    PORT
      LAYER M4 ;
        RECT  0 44.88 0.192 44.904 ;
    END
  END o[441]
  PIN o[442]
    DIRECTION OUTPUT ;
    USE SIGNAL ;
    PORT
      LAYER M4 ;
        RECT  0 44.976 0.192 45 ;
    END
  END o[442]
  PIN o[443]
    DIRECTION OUTPUT ;
    USE SIGNAL ;
    PORT
      LAYER M4 ;
        RECT  0 45.072 0.192 45.096 ;
    END
  END o[443]
  PIN o[444]
    DIRECTION OUTPUT ;
    USE SIGNAL ;
    PORT
      LAYER M4 ;
        RECT  0 45.168 0.192 45.192 ;
    END
  END o[444]
  PIN o[445]
    DIRECTION OUTPUT ;
    USE SIGNAL ;
    PORT
      LAYER M4 ;
        RECT  0 45.264 0.192 45.288 ;
    END
  END o[445]
  PIN o[446]
    DIRECTION OUTPUT ;
    USE SIGNAL ;
    PORT
      LAYER M4 ;
        RECT  0 45.36 0.192 45.384 ;
    END
  END o[446]
  PIN o[447]
    DIRECTION OUTPUT ;
    USE SIGNAL ;
    PORT
      LAYER M4 ;
        RECT  0 45.456 0.192 45.48 ;
    END
  END o[447]
  PIN o[448]
    DIRECTION OUTPUT ;
    USE SIGNAL ;
    PORT
      LAYER M4 ;
        RECT  0 45.552 0.192 45.576 ;
    END
  END o[448]
  PIN o[449]
    DIRECTION OUTPUT ;
    USE SIGNAL ;
    PORT
      LAYER M4 ;
        RECT  0 45.648 0.192 45.672 ;
    END
  END o[449]
  PIN o[44]
    DIRECTION OUTPUT ;
    USE SIGNAL ;
    PORT
      LAYER M4 ;
        RECT  0 6.48 0.192 6.504 ;
    END
  END o[44]
  PIN o[450]
    DIRECTION OUTPUT ;
    USE SIGNAL ;
    PORT
      LAYER M4 ;
        RECT  0 45.744 0.192 45.768 ;
    END
  END o[450]
  PIN o[451]
    DIRECTION OUTPUT ;
    USE SIGNAL ;
    PORT
      LAYER M4 ;
        RECT  0 45.84 0.192 45.864 ;
    END
  END o[451]
  PIN o[452]
    DIRECTION OUTPUT ;
    USE SIGNAL ;
    PORT
      LAYER M4 ;
        RECT  0 45.936 0.192 45.96 ;
    END
  END o[452]
  PIN o[453]
    DIRECTION OUTPUT ;
    USE SIGNAL ;
    PORT
      LAYER M4 ;
        RECT  0 46.032 0.192 46.056 ;
    END
  END o[453]
  PIN o[454]
    DIRECTION OUTPUT ;
    USE SIGNAL ;
    PORT
      LAYER M4 ;
        RECT  0 46.128 0.192 46.152 ;
    END
  END o[454]
  PIN o[455]
    DIRECTION OUTPUT ;
    USE SIGNAL ;
    PORT
      LAYER M4 ;
        RECT  0 46.224 0.192 46.248 ;
    END
  END o[455]
  PIN o[456]
    DIRECTION OUTPUT ;
    USE SIGNAL ;
    PORT
      LAYER M4 ;
        RECT  0 46.32 0.192 46.344 ;
    END
  END o[456]
  PIN o[457]
    DIRECTION OUTPUT ;
    USE SIGNAL ;
    PORT
      LAYER M4 ;
        RECT  0 46.416 0.192 46.44 ;
    END
  END o[457]
  PIN o[458]
    DIRECTION OUTPUT ;
    USE SIGNAL ;
    PORT
      LAYER M4 ;
        RECT  0 46.512 0.192 46.536 ;
    END
  END o[458]
  PIN o[459]
    DIRECTION OUTPUT ;
    USE SIGNAL ;
    PORT
      LAYER M4 ;
        RECT  0 46.608 0.192 46.632 ;
    END
  END o[459]
  PIN o[45]
    DIRECTION OUTPUT ;
    USE SIGNAL ;
    PORT
      LAYER M4 ;
        RECT  0 6.576 0.192 6.6 ;
    END
  END o[45]
  PIN o[460]
    DIRECTION OUTPUT ;
    USE SIGNAL ;
    PORT
      LAYER M4 ;
        RECT  0 46.704 0.192 46.728 ;
    END
  END o[460]
  PIN o[461]
    DIRECTION OUTPUT ;
    USE SIGNAL ;
    PORT
      LAYER M4 ;
        RECT  0 46.8 0.192 46.824 ;
    END
  END o[461]
  PIN o[462]
    DIRECTION OUTPUT ;
    USE SIGNAL ;
    PORT
      LAYER M4 ;
        RECT  0 46.896 0.192 46.92 ;
    END
  END o[462]
  PIN o[463]
    DIRECTION OUTPUT ;
    USE SIGNAL ;
    PORT
      LAYER M4 ;
        RECT  0 46.992 0.192 47.016 ;
    END
  END o[463]
  PIN o[464]
    DIRECTION OUTPUT ;
    USE SIGNAL ;
    PORT
      LAYER M4 ;
        RECT  0 47.088 0.192 47.112 ;
    END
  END o[464]
  PIN o[465]
    DIRECTION OUTPUT ;
    USE SIGNAL ;
    PORT
      LAYER M4 ;
        RECT  0 47.184 0.192 47.208 ;
    END
  END o[465]
  PIN o[466]
    DIRECTION OUTPUT ;
    USE SIGNAL ;
    PORT
      LAYER M4 ;
        RECT  0 47.28 0.192 47.304 ;
    END
  END o[466]
  PIN o[467]
    DIRECTION OUTPUT ;
    USE SIGNAL ;
    PORT
      LAYER M4 ;
        RECT  0 47.376 0.192 47.4 ;
    END
  END o[467]
  PIN o[468]
    DIRECTION OUTPUT ;
    USE SIGNAL ;
    PORT
      LAYER M4 ;
        RECT  0 47.472 0.192 47.496 ;
    END
  END o[468]
  PIN o[469]
    DIRECTION OUTPUT ;
    USE SIGNAL ;
    PORT
      LAYER M4 ;
        RECT  0 47.568 0.192 47.592 ;
    END
  END o[469]
  PIN o[46]
    DIRECTION OUTPUT ;
    USE SIGNAL ;
    PORT
      LAYER M4 ;
        RECT  0 6.672 0.192 6.696 ;
    END
  END o[46]
  PIN o[470]
    DIRECTION OUTPUT ;
    USE SIGNAL ;
    PORT
      LAYER M4 ;
        RECT  0 47.664 0.192 47.688 ;
    END
  END o[470]
  PIN o[471]
    DIRECTION OUTPUT ;
    USE SIGNAL ;
    PORT
      LAYER M4 ;
        RECT  0 47.76 0.192 47.784 ;
    END
  END o[471]
  PIN o[472]
    DIRECTION OUTPUT ;
    USE SIGNAL ;
    PORT
      LAYER M4 ;
        RECT  0 47.856 0.192 47.88 ;
    END
  END o[472]
  PIN o[473]
    DIRECTION OUTPUT ;
    USE SIGNAL ;
    PORT
      LAYER M4 ;
        RECT  0 47.952 0.192 47.976 ;
    END
  END o[473]
  PIN o[474]
    DIRECTION OUTPUT ;
    USE SIGNAL ;
    PORT
      LAYER M4 ;
        RECT  0 48.048 0.192 48.072 ;
    END
  END o[474]
  PIN o[475]
    DIRECTION OUTPUT ;
    USE SIGNAL ;
    PORT
      LAYER M4 ;
        RECT  0 48.144 0.192 48.168 ;
    END
  END o[475]
  PIN o[476]
    DIRECTION OUTPUT ;
    USE SIGNAL ;
    PORT
      LAYER M4 ;
        RECT  0 48.24 0.192 48.264 ;
    END
  END o[476]
  PIN o[477]
    DIRECTION OUTPUT ;
    USE SIGNAL ;
    PORT
      LAYER M4 ;
        RECT  0 48.336 0.192 48.36 ;
    END
  END o[477]
  PIN o[478]
    DIRECTION OUTPUT ;
    USE SIGNAL ;
    PORT
      LAYER M4 ;
        RECT  0 48.432 0.192 48.456 ;
    END
  END o[478]
  PIN o[479]
    DIRECTION OUTPUT ;
    USE SIGNAL ;
    PORT
      LAYER M4 ;
        RECT  0 48.528 0.192 48.552 ;
    END
  END o[479]
  PIN o[47]
    DIRECTION OUTPUT ;
    USE SIGNAL ;
    PORT
      LAYER M4 ;
        RECT  0 6.768 0.192 6.792 ;
    END
  END o[47]
  PIN o[480]
    DIRECTION OUTPUT ;
    USE SIGNAL ;
    PORT
      LAYER M4 ;
        RECT  0 48.624 0.192 48.648 ;
    END
  END o[480]
  PIN o[481]
    DIRECTION OUTPUT ;
    USE SIGNAL ;
    PORT
      LAYER M4 ;
        RECT  0 48.72 0.192 48.744 ;
    END
  END o[481]
  PIN o[482]
    DIRECTION OUTPUT ;
    USE SIGNAL ;
    PORT
      LAYER M4 ;
        RECT  0 48.816 0.192 48.84 ;
    END
  END o[482]
  PIN o[483]
    DIRECTION OUTPUT ;
    USE SIGNAL ;
    PORT
      LAYER M4 ;
        RECT  0 48.912 0.192 48.936 ;
    END
  END o[483]
  PIN o[484]
    DIRECTION OUTPUT ;
    USE SIGNAL ;
    PORT
      LAYER M4 ;
        RECT  0 49.008 0.192 49.032 ;
    END
  END o[484]
  PIN o[485]
    DIRECTION OUTPUT ;
    USE SIGNAL ;
    PORT
      LAYER M4 ;
        RECT  0 49.104 0.192 49.128 ;
    END
  END o[485]
  PIN o[486]
    DIRECTION OUTPUT ;
    USE SIGNAL ;
    PORT
      LAYER M4 ;
        RECT  0 49.248 0.192 49.272 ;
    END
  END o[486]
  PIN o[487]
    DIRECTION OUTPUT ;
    USE SIGNAL ;
    PORT
      LAYER M4 ;
        RECT  0 49.344 0.192 49.368 ;
    END
  END o[487]
  PIN o[488]
    DIRECTION OUTPUT ;
    USE SIGNAL ;
    PORT
      LAYER M4 ;
        RECT  0 49.44 0.192 49.464 ;
    END
  END o[488]
  PIN o[489]
    DIRECTION OUTPUT ;
    USE SIGNAL ;
    PORT
      LAYER M4 ;
        RECT  0 49.536 0.192 49.56 ;
    END
  END o[489]
  PIN o[48]
    DIRECTION OUTPUT ;
    USE SIGNAL ;
    PORT
      LAYER M4 ;
        RECT  0 6.864 0.192 6.888 ;
    END
  END o[48]
  PIN o[490]
    DIRECTION OUTPUT ;
    USE SIGNAL ;
    PORT
      LAYER M4 ;
        RECT  0 49.632 0.192 49.656 ;
    END
  END o[490]
  PIN o[491]
    DIRECTION OUTPUT ;
    USE SIGNAL ;
    PORT
      LAYER M4 ;
        RECT  0 49.728 0.192 49.752 ;
    END
  END o[491]
  PIN o[492]
    DIRECTION OUTPUT ;
    USE SIGNAL ;
    PORT
      LAYER M4 ;
        RECT  0 49.824 0.192 49.848 ;
    END
  END o[492]
  PIN o[493]
    DIRECTION OUTPUT ;
    USE SIGNAL ;
    PORT
      LAYER M4 ;
        RECT  0 49.92 0.192 49.944 ;
    END
  END o[493]
  PIN o[494]
    DIRECTION OUTPUT ;
    USE SIGNAL ;
    PORT
      LAYER M4 ;
        RECT  0 50.016 0.192 50.04 ;
    END
  END o[494]
  PIN o[495]
    DIRECTION OUTPUT ;
    USE SIGNAL ;
    PORT
      LAYER M4 ;
        RECT  0 50.112 0.192 50.136 ;
    END
  END o[495]
  PIN o[496]
    DIRECTION OUTPUT ;
    USE SIGNAL ;
    PORT
      LAYER M4 ;
        RECT  0 50.208 0.192 50.232 ;
    END
  END o[496]
  PIN o[497]
    DIRECTION OUTPUT ;
    USE SIGNAL ;
    PORT
      LAYER M4 ;
        RECT  0 50.304 0.192 50.328 ;
    END
  END o[497]
  PIN o[498]
    DIRECTION OUTPUT ;
    USE SIGNAL ;
    PORT
      LAYER M4 ;
        RECT  0 50.4 0.192 50.424 ;
    END
  END o[498]
  PIN o[499]
    DIRECTION OUTPUT ;
    USE SIGNAL ;
    PORT
      LAYER M4 ;
        RECT  0 50.496 0.192 50.52 ;
    END
  END o[499]
  PIN o[49]
    DIRECTION OUTPUT ;
    USE SIGNAL ;
    PORT
      LAYER M4 ;
        RECT  0 6.96 0.192 6.984 ;
    END
  END o[49]
  PIN o[4]
    DIRECTION OUTPUT ;
    USE SIGNAL ;
    PORT
      LAYER M4 ;
        RECT  0 2.592 0.192 2.616 ;
    END
  END o[4]
  PIN o[500]
    DIRECTION OUTPUT ;
    USE SIGNAL ;
    PORT
      LAYER M4 ;
        RECT  0 50.592 0.192 50.616 ;
    END
  END o[500]
  PIN o[501]
    DIRECTION OUTPUT ;
    USE SIGNAL ;
    PORT
      LAYER M4 ;
        RECT  0 50.688 0.192 50.712 ;
    END
  END o[501]
  PIN o[502]
    DIRECTION OUTPUT ;
    USE SIGNAL ;
    PORT
      LAYER M4 ;
        RECT  0 50.784 0.192 50.808 ;
    END
  END o[502]
  PIN o[503]
    DIRECTION OUTPUT ;
    USE SIGNAL ;
    PORT
      LAYER M4 ;
        RECT  0 50.88 0.192 50.904 ;
    END
  END o[503]
  PIN o[504]
    DIRECTION OUTPUT ;
    USE SIGNAL ;
    PORT
      LAYER M4 ;
        RECT  0 50.976 0.192 51 ;
    END
  END o[504]
  PIN o[505]
    DIRECTION OUTPUT ;
    USE SIGNAL ;
    PORT
      LAYER M4 ;
        RECT  0 51.072 0.192 51.096 ;
    END
  END o[505]
  PIN o[506]
    DIRECTION OUTPUT ;
    USE SIGNAL ;
    PORT
      LAYER M4 ;
        RECT  0 51.168 0.192 51.192 ;
    END
  END o[506]
  PIN o[507]
    DIRECTION OUTPUT ;
    USE SIGNAL ;
    PORT
      LAYER M4 ;
        RECT  0 51.264 0.192 51.288 ;
    END
  END o[507]
  PIN o[508]
    DIRECTION OUTPUT ;
    USE SIGNAL ;
    PORT
      LAYER M4 ;
        RECT  0 51.36 0.192 51.384 ;
    END
  END o[508]
  PIN o[509]
    DIRECTION OUTPUT ;
    USE SIGNAL ;
    PORT
      LAYER M4 ;
        RECT  0 51.456 0.192 51.48 ;
    END
  END o[509]
  PIN o[50]
    DIRECTION OUTPUT ;
    USE SIGNAL ;
    PORT
      LAYER M4 ;
        RECT  0 7.056 0.192 7.08 ;
    END
  END o[50]
  PIN o[510]
    DIRECTION OUTPUT ;
    USE SIGNAL ;
    PORT
      LAYER M4 ;
        RECT  0 51.552 0.192 51.576 ;
    END
  END o[510]
  PIN o[511]
    DIRECTION OUTPUT ;
    USE SIGNAL ;
    PORT
      LAYER M4 ;
        RECT  0 51.648 0.192 51.672 ;
    END
  END o[511]
  PIN o[512]
    DIRECTION OUTPUT ;
    USE SIGNAL ;
    PORT
      LAYER M4 ;
        RECT  0 51.744 0.192 51.768 ;
    END
  END o[512]
  PIN o[513]
    DIRECTION OUTPUT ;
    USE SIGNAL ;
    PORT
      LAYER M4 ;
        RECT  0 51.84 0.192 51.864 ;
    END
  END o[513]
  PIN o[514]
    DIRECTION OUTPUT ;
    USE SIGNAL ;
    PORT
      LAYER M4 ;
        RECT  0 51.936 0.192 51.96 ;
    END
  END o[514]
  PIN o[515]
    DIRECTION OUTPUT ;
    USE SIGNAL ;
    PORT
      LAYER M4 ;
        RECT  0 52.032 0.192 52.056 ;
    END
  END o[515]
  PIN o[516]
    DIRECTION OUTPUT ;
    USE SIGNAL ;
    PORT
      LAYER M4 ;
        RECT  0 52.128 0.192 52.152 ;
    END
  END o[516]
  PIN o[517]
    DIRECTION OUTPUT ;
    USE SIGNAL ;
    PORT
      LAYER M4 ;
        RECT  0 52.224 0.192 52.248 ;
    END
  END o[517]
  PIN o[518]
    DIRECTION OUTPUT ;
    USE SIGNAL ;
    PORT
      LAYER M4 ;
        RECT  0 52.32 0.192 52.344 ;
    END
  END o[518]
  PIN o[519]
    DIRECTION OUTPUT ;
    USE SIGNAL ;
    PORT
      LAYER M4 ;
        RECT  0 52.416 0.192 52.44 ;
    END
  END o[519]
  PIN o[51]
    DIRECTION OUTPUT ;
    USE SIGNAL ;
    PORT
      LAYER M4 ;
        RECT  0 7.152 0.192 7.176 ;
    END
  END o[51]
  PIN o[520]
    DIRECTION OUTPUT ;
    USE SIGNAL ;
    PORT
      LAYER M4 ;
        RECT  0 52.512 0.192 52.536 ;
    END
  END o[520]
  PIN o[521]
    DIRECTION OUTPUT ;
    USE SIGNAL ;
    PORT
      LAYER M4 ;
        RECT  0 52.608 0.192 52.632 ;
    END
  END o[521]
  PIN o[522]
    DIRECTION OUTPUT ;
    USE SIGNAL ;
    PORT
      LAYER M4 ;
        RECT  0 52.704 0.192 52.728 ;
    END
  END o[522]
  PIN o[523]
    DIRECTION OUTPUT ;
    USE SIGNAL ;
    PORT
      LAYER M4 ;
        RECT  0 52.8 0.192 52.824 ;
    END
  END o[523]
  PIN o[524]
    DIRECTION OUTPUT ;
    USE SIGNAL ;
    PORT
      LAYER M4 ;
        RECT  0 52.896 0.192 52.92 ;
    END
  END o[524]
  PIN o[525]
    DIRECTION OUTPUT ;
    USE SIGNAL ;
    PORT
      LAYER M4 ;
        RECT  0 52.992 0.192 53.016 ;
    END
  END o[525]
  PIN o[526]
    DIRECTION OUTPUT ;
    USE SIGNAL ;
    PORT
      LAYER M4 ;
        RECT  0 53.088 0.192 53.112 ;
    END
  END o[526]
  PIN o[527]
    DIRECTION OUTPUT ;
    USE SIGNAL ;
    PORT
      LAYER M4 ;
        RECT  0 53.184 0.192 53.208 ;
    END
  END o[527]
  PIN o[528]
    DIRECTION OUTPUT ;
    USE SIGNAL ;
    PORT
      LAYER M4 ;
        RECT  0 53.28 0.192 53.304 ;
    END
  END o[528]
  PIN o[529]
    DIRECTION OUTPUT ;
    USE SIGNAL ;
    PORT
      LAYER M4 ;
        RECT  0 53.376 0.192 53.4 ;
    END
  END o[529]
  PIN o[52]
    DIRECTION OUTPUT ;
    USE SIGNAL ;
    PORT
      LAYER M4 ;
        RECT  0 7.248 0.192 7.272 ;
    END
  END o[52]
  PIN o[530]
    DIRECTION OUTPUT ;
    USE SIGNAL ;
    PORT
      LAYER M4 ;
        RECT  0 53.472 0.192 53.496 ;
    END
  END o[530]
  PIN o[531]
    DIRECTION OUTPUT ;
    USE SIGNAL ;
    PORT
      LAYER M4 ;
        RECT  0 53.568 0.192 53.592 ;
    END
  END o[531]
  PIN o[532]
    DIRECTION OUTPUT ;
    USE SIGNAL ;
    PORT
      LAYER M4 ;
        RECT  0 53.664 0.192 53.688 ;
    END
  END o[532]
  PIN o[533]
    DIRECTION OUTPUT ;
    USE SIGNAL ;
    PORT
      LAYER M4 ;
        RECT  0 53.76 0.192 53.784 ;
    END
  END o[533]
  PIN o[534]
    DIRECTION OUTPUT ;
    USE SIGNAL ;
    PORT
      LAYER M4 ;
        RECT  0 53.856 0.192 53.88 ;
    END
  END o[534]
  PIN o[535]
    DIRECTION OUTPUT ;
    USE SIGNAL ;
    PORT
      LAYER M4 ;
        RECT  0 53.952 0.192 53.976 ;
    END
  END o[535]
  PIN o[53]
    DIRECTION OUTPUT ;
    USE SIGNAL ;
    PORT
      LAYER M4 ;
        RECT  0 7.344 0.192 7.368 ;
    END
  END o[53]
  PIN o[54]
    DIRECTION OUTPUT ;
    USE SIGNAL ;
    PORT
      LAYER M4 ;
        RECT  0 7.44 0.192 7.464 ;
    END
  END o[54]
  PIN o[55]
    DIRECTION OUTPUT ;
    USE SIGNAL ;
    PORT
      LAYER M4 ;
        RECT  0 7.536 0.192 7.56 ;
    END
  END o[55]
  PIN o[56]
    DIRECTION OUTPUT ;
    USE SIGNAL ;
    PORT
      LAYER M4 ;
        RECT  0 7.632 0.192 7.656 ;
    END
  END o[56]
  PIN o[57]
    DIRECTION OUTPUT ;
    USE SIGNAL ;
    PORT
      LAYER M4 ;
        RECT  0 7.728 0.192 7.752 ;
    END
  END o[57]
  PIN o[58]
    DIRECTION OUTPUT ;
    USE SIGNAL ;
    PORT
      LAYER M4 ;
        RECT  0 7.824 0.192 7.848 ;
    END
  END o[58]
  PIN o[59]
    DIRECTION OUTPUT ;
    USE SIGNAL ;
    PORT
      LAYER M4 ;
        RECT  0 7.92 0.192 7.944 ;
    END
  END o[59]
  PIN o[5]
    DIRECTION OUTPUT ;
    USE SIGNAL ;
    PORT
      LAYER M4 ;
        RECT  0 2.688 0.192 2.712 ;
    END
  END o[5]
  PIN o[60]
    DIRECTION OUTPUT ;
    USE SIGNAL ;
    PORT
      LAYER M4 ;
        RECT  0 8.016 0.192 8.04 ;
    END
  END o[60]
  PIN o[61]
    DIRECTION OUTPUT ;
    USE SIGNAL ;
    PORT
      LAYER M4 ;
        RECT  0 8.112 0.192 8.136 ;
    END
  END o[61]
  PIN o[62]
    DIRECTION OUTPUT ;
    USE SIGNAL ;
    PORT
      LAYER M4 ;
        RECT  0 8.208 0.192 8.232 ;
    END
  END o[62]
  PIN o[63]
    DIRECTION OUTPUT ;
    USE SIGNAL ;
    PORT
      LAYER M4 ;
        RECT  0 8.304 0.192 8.328 ;
    END
  END o[63]
  PIN o[64]
    DIRECTION OUTPUT ;
    USE SIGNAL ;
    PORT
      LAYER M4 ;
        RECT  0 8.4 0.192 8.424 ;
    END
  END o[64]
  PIN o[65]
    DIRECTION OUTPUT ;
    USE SIGNAL ;
    PORT
      LAYER M4 ;
        RECT  0 8.496 0.192 8.52 ;
    END
  END o[65]
  PIN o[66]
    DIRECTION OUTPUT ;
    USE SIGNAL ;
    PORT
      LAYER M4 ;
        RECT  0 8.592 0.192 8.616 ;
    END
  END o[66]
  PIN o[67]
    DIRECTION OUTPUT ;
    USE SIGNAL ;
    PORT
      LAYER M4 ;
        RECT  0 8.688 0.192 8.712 ;
    END
  END o[67]
  PIN o[68]
    DIRECTION OUTPUT ;
    USE SIGNAL ;
    PORT
      LAYER M4 ;
        RECT  0 8.784 0.192 8.808 ;
    END
  END o[68]
  PIN o[69]
    DIRECTION OUTPUT ;
    USE SIGNAL ;
    PORT
      LAYER M4 ;
        RECT  0 8.88 0.192 8.904 ;
    END
  END o[69]
  PIN o[6]
    DIRECTION OUTPUT ;
    USE SIGNAL ;
    PORT
      LAYER M4 ;
        RECT  0 2.784 0.192 2.808 ;
    END
  END o[6]
  PIN o[70]
    DIRECTION OUTPUT ;
    USE SIGNAL ;
    PORT
      LAYER M4 ;
        RECT  0 8.976 0.192 9 ;
    END
  END o[70]
  PIN o[71]
    DIRECTION OUTPUT ;
    USE SIGNAL ;
    PORT
      LAYER M4 ;
        RECT  0 9.072 0.192 9.096 ;
    END
  END o[71]
  PIN o[72]
    DIRECTION OUTPUT ;
    USE SIGNAL ;
    PORT
      LAYER M4 ;
        RECT  0 9.168 0.192 9.192 ;
    END
  END o[72]
  PIN o[73]
    DIRECTION OUTPUT ;
    USE SIGNAL ;
    PORT
      LAYER M4 ;
        RECT  0 9.264 0.192 9.288 ;
    END
  END o[73]
  PIN o[74]
    DIRECTION OUTPUT ;
    USE SIGNAL ;
    PORT
      LAYER M4 ;
        RECT  0 9.36 0.192 9.384 ;
    END
  END o[74]
  PIN o[75]
    DIRECTION OUTPUT ;
    USE SIGNAL ;
    PORT
      LAYER M4 ;
        RECT  0 9.456 0.192 9.48 ;
    END
  END o[75]
  PIN o[76]
    DIRECTION OUTPUT ;
    USE SIGNAL ;
    PORT
      LAYER M4 ;
        RECT  0 9.552 0.192 9.576 ;
    END
  END o[76]
  PIN o[77]
    DIRECTION OUTPUT ;
    USE SIGNAL ;
    PORT
      LAYER M4 ;
        RECT  0 9.648 0.192 9.672 ;
    END
  END o[77]
  PIN o[78]
    DIRECTION OUTPUT ;
    USE SIGNAL ;
    PORT
      LAYER M4 ;
        RECT  0 9.744 0.192 9.768 ;
    END
  END o[78]
  PIN o[79]
    DIRECTION OUTPUT ;
    USE SIGNAL ;
    PORT
      LAYER M4 ;
        RECT  0 9.84 0.192 9.864 ;
    END
  END o[79]
  PIN o[7]
    DIRECTION OUTPUT ;
    USE SIGNAL ;
    PORT
      LAYER M4 ;
        RECT  0 2.88 0.192 2.904 ;
    END
  END o[7]
  PIN o[80]
    DIRECTION OUTPUT ;
    USE SIGNAL ;
    PORT
      LAYER M4 ;
        RECT  0 9.936 0.192 9.96 ;
    END
  END o[80]
  PIN o[81]
    DIRECTION OUTPUT ;
    USE SIGNAL ;
    PORT
      LAYER M4 ;
        RECT  0 10.032 0.192 10.056 ;
    END
  END o[81]
  PIN o[82]
    DIRECTION OUTPUT ;
    USE SIGNAL ;
    PORT
      LAYER M4 ;
        RECT  0 10.128 0.192 10.152 ;
    END
  END o[82]
  PIN o[83]
    DIRECTION OUTPUT ;
    USE SIGNAL ;
    PORT
      LAYER M4 ;
        RECT  0 10.224 0.192 10.248 ;
    END
  END o[83]
  PIN o[84]
    DIRECTION OUTPUT ;
    USE SIGNAL ;
    PORT
      LAYER M4 ;
        RECT  0 10.368 0.192 10.392 ;
    END
  END o[84]
  PIN o[85]
    DIRECTION OUTPUT ;
    USE SIGNAL ;
    PORT
      LAYER M4 ;
        RECT  0 10.464 0.192 10.488 ;
    END
  END o[85]
  PIN o[86]
    DIRECTION OUTPUT ;
    USE SIGNAL ;
    PORT
      LAYER M4 ;
        RECT  0 10.56 0.192 10.584 ;
    END
  END o[86]
  PIN o[87]
    DIRECTION OUTPUT ;
    USE SIGNAL ;
    PORT
      LAYER M4 ;
        RECT  0 10.656 0.192 10.68 ;
    END
  END o[87]
  PIN o[88]
    DIRECTION OUTPUT ;
    USE SIGNAL ;
    PORT
      LAYER M4 ;
        RECT  0 10.752 0.192 10.776 ;
    END
  END o[88]
  PIN o[89]
    DIRECTION OUTPUT ;
    USE SIGNAL ;
    PORT
      LAYER M4 ;
        RECT  0 10.848 0.192 10.872 ;
    END
  END o[89]
  PIN o[8]
    DIRECTION OUTPUT ;
    USE SIGNAL ;
    PORT
      LAYER M4 ;
        RECT  0 2.976 0.192 3 ;
    END
  END o[8]
  PIN o[90]
    DIRECTION OUTPUT ;
    USE SIGNAL ;
    PORT
      LAYER M4 ;
        RECT  0 10.944 0.192 10.968 ;
    END
  END o[90]
  PIN o[91]
    DIRECTION OUTPUT ;
    USE SIGNAL ;
    PORT
      LAYER M4 ;
        RECT  0 11.04 0.192 11.064 ;
    END
  END o[91]
  PIN o[92]
    DIRECTION OUTPUT ;
    USE SIGNAL ;
    PORT
      LAYER M4 ;
        RECT  0 11.136 0.192 11.16 ;
    END
  END o[92]
  PIN o[93]
    DIRECTION OUTPUT ;
    USE SIGNAL ;
    PORT
      LAYER M4 ;
        RECT  0 11.232 0.192 11.256 ;
    END
  END o[93]
  PIN o[94]
    DIRECTION OUTPUT ;
    USE SIGNAL ;
    PORT
      LAYER M4 ;
        RECT  0 11.328 0.192 11.352 ;
    END
  END o[94]
  PIN o[95]
    DIRECTION OUTPUT ;
    USE SIGNAL ;
    PORT
      LAYER M4 ;
        RECT  0 11.424 0.192 11.448 ;
    END
  END o[95]
  PIN o[96]
    DIRECTION OUTPUT ;
    USE SIGNAL ;
    PORT
      LAYER M4 ;
        RECT  0 11.52 0.192 11.544 ;
    END
  END o[96]
  PIN o[97]
    DIRECTION OUTPUT ;
    USE SIGNAL ;
    PORT
      LAYER M4 ;
        RECT  0 11.616 0.192 11.64 ;
    END
  END o[97]
  PIN o[98]
    DIRECTION OUTPUT ;
    USE SIGNAL ;
    PORT
      LAYER M4 ;
        RECT  0 11.712 0.192 11.736 ;
    END
  END o[98]
  PIN o[99]
    DIRECTION OUTPUT ;
    USE SIGNAL ;
    PORT
      LAYER M4 ;
        RECT  0 11.808 0.192 11.832 ;
    END
  END o[99]
  PIN o[9]
    DIRECTION OUTPUT ;
    USE SIGNAL ;
    PORT
      LAYER M4 ;
        RECT  0 3.072 0.192 3.096 ;
    END
  END o[9]
  PIN rs
    DIRECTION INPUT ;
    USE SIGNAL ;
    PORT
      LAYER M5 ;
        RECT  41.04 55.968 41.064 56.16 ;
    END
  END rs
  PIN VDD
    DIRECTION INOUT ;
    USE POWER ;
    PORT
      LAYER M5 ;
        RECT  53.892 2.151 54.012 54.009 ;
        RECT  51.192 2.151 51.312 54.009 ;
        RECT  48.492 2.151 48.612 54.009 ;
        RECT  45.792 2.151 45.912 54.009 ;
        RECT  43.092 2.151 43.212 54.009 ;
        RECT  40.392 2.151 40.512 54.009 ;
        RECT  37.692 2.151 37.812 54.009 ;
        RECT  34.992 2.151 35.112 54.009 ;
        RECT  32.292 2.151 32.412 54.009 ;
        RECT  29.592 2.151 29.712 54.009 ;
        RECT  26.892 2.151 27.012 54.009 ;
        RECT  24.192 2.151 24.312 54.009 ;
        RECT  21.492 2.151 21.612 54.009 ;
        RECT  18.792 2.151 18.912 54.009 ;
        RECT  16.092 2.151 16.212 54.009 ;
        RECT  13.392 2.151 13.512 54.009 ;
        RECT  10.692 2.151 10.812 54.009 ;
        RECT  7.992 2.151 8.112 54.009 ;
        RECT  5.292 2.151 5.412 54.009 ;
        RECT  2.592 2.151 2.712 54.009 ;
    END
  END VDD
  PIN VSS
    DIRECTION INOUT ;
    USE GROUND ;
    PORT
      LAYER M5 ;
        RECT  53.7 2.137 53.82 54.023 ;
        RECT  51 2.137 51.12 54.023 ;
        RECT  48.3 2.137 48.42 54.023 ;
        RECT  45.6 2.137 45.72 54.023 ;
        RECT  42.9 2.137 43.02 54.023 ;
        RECT  40.2 2.137 40.32 54.023 ;
        RECT  37.5 2.137 37.62 54.023 ;
        RECT  34.8 2.137 34.92 54.023 ;
        RECT  32.1 2.137 32.22 54.023 ;
        RECT  29.4 2.137 29.52 54.023 ;
        RECT  26.7 2.137 26.82 54.023 ;
        RECT  24 2.137 24.12 54.023 ;
        RECT  21.3 2.137 21.42 54.023 ;
        RECT  18.6 2.137 18.72 54.023 ;
        RECT  15.9 2.137 16.02 54.023 ;
        RECT  13.2 2.137 13.32 54.023 ;
        RECT  10.5 2.137 10.62 54.023 ;
        RECT  7.8 2.137 7.92 54.023 ;
        RECT  5.1 2.137 5.22 54.023 ;
        RECT  2.4 2.137 2.52 54.023 ;
    END
  END VSS
  OBS
    LAYER RVTN ;
     RECT  2.16 2.16 54 2.295 ;
     RECT  2.16 2.565 54 2.835 ;
     RECT  2.16 3.105 54 3.375 ;
     RECT  2.16 3.645 54 3.915 ;
     RECT  2.16 4.185 54 4.455 ;
     RECT  2.16 4.725 54 4.995 ;
     RECT  2.16 5.265 54 5.535 ;
     RECT  2.16 5.805 54 6.075 ;
     RECT  2.16 6.345 54 6.615 ;
     RECT  2.16 6.885 54 7.155 ;
     RECT  2.16 7.425 54 7.695 ;
     RECT  2.16 7.965 54 8.235 ;
     RECT  2.16 8.505 54 8.775 ;
     RECT  2.16 9.045 54 9.315 ;
     RECT  2.16 9.585 54 9.855 ;
     RECT  2.16 10.125 54 10.395 ;
     RECT  2.16 10.665 54 10.935 ;
     RECT  2.16 11.205 54 11.475 ;
     RECT  2.16 11.745 54 12.015 ;
     RECT  2.16 12.285 54 12.555 ;
     RECT  2.16 12.825 54 13.095 ;
     RECT  2.16 13.365 54 13.635 ;
     RECT  2.16 13.905 54 14.175 ;
     RECT  2.16 14.445 54 14.715 ;
     RECT  2.16 14.985 54 15.255 ;
     RECT  2.16 15.525 54 15.795 ;
     RECT  2.16 16.065 54 16.335 ;
     RECT  2.16 16.605 54 16.875 ;
     RECT  2.16 17.145 54 17.415 ;
     RECT  2.16 17.685 54 17.955 ;
     RECT  2.16 18.225 54 18.495 ;
     RECT  2.16 18.765 54 19.035 ;
     RECT  2.16 19.305 54 19.575 ;
     RECT  2.16 19.845 54 20.115 ;
     RECT  2.16 20.385 54 20.655 ;
     RECT  2.16 20.925 54 21.195 ;
     RECT  2.16 21.465 54 21.735 ;
     RECT  2.16 22.005 54 22.275 ;
     RECT  2.16 22.545 54 22.815 ;
     RECT  2.16 23.085 54 23.355 ;
     RECT  2.16 23.625 54 23.895 ;
     RECT  2.16 24.165 54 24.435 ;
     RECT  2.16 24.705 54 24.975 ;
     RECT  2.16 25.245 54 25.515 ;
     RECT  2.16 25.785 54 26.055 ;
     RECT  2.16 26.325 54 26.595 ;
     RECT  2.16 26.865 54 27.135 ;
     RECT  2.16 27.405 54 27.675 ;
     RECT  2.16 27.945 54 28.215 ;
     RECT  2.16 28.485 54 28.755 ;
     RECT  2.16 29.025 54 29.295 ;
     RECT  2.16 29.565 54 29.835 ;
     RECT  2.16 30.105 54 30.375 ;
     RECT  2.16 30.645 54 30.915 ;
     RECT  2.16 31.185 54 31.455 ;
     RECT  2.16 31.725 54 31.995 ;
     RECT  2.16 32.265 54 32.535 ;
     RECT  2.16 32.805 54 33.075 ;
     RECT  2.16 33.345 54 33.615 ;
     RECT  2.16 33.885 54 34.155 ;
     RECT  2.16 34.425 54 34.695 ;
     RECT  2.16 34.965 54 35.235 ;
     RECT  2.16 35.505 54 35.775 ;
     RECT  2.16 36.045 54 36.315 ;
     RECT  2.16 36.585 54 36.855 ;
     RECT  2.16 37.125 54 37.395 ;
     RECT  2.16 37.665 54 37.935 ;
     RECT  2.16 38.205 54 38.475 ;
     RECT  2.16 38.745 54 39.015 ;
     RECT  2.16 39.285 54 39.555 ;
     RECT  2.16 39.825 54 40.095 ;
     RECT  2.16 40.365 54 40.635 ;
     RECT  2.16 40.905 54 41.175 ;
     RECT  2.16 41.445 54 41.715 ;
     RECT  2.16 41.985 54 42.255 ;
     RECT  2.16 42.525 54 42.795 ;
     RECT  2.16 43.065 54 43.335 ;
     RECT  2.16 43.605 54 43.875 ;
     RECT  2.16 44.145 54 44.415 ;
     RECT  2.16 44.685 54 44.955 ;
     RECT  2.16 45.225 54 45.495 ;
     RECT  2.16 45.765 54 46.035 ;
     RECT  2.16 46.305 54 46.575 ;
     RECT  2.16 46.845 54 47.115 ;
     RECT  2.16 47.385 54 47.655 ;
     RECT  2.16 47.925 54 48.195 ;
     RECT  2.16 48.465 54 48.735 ;
     RECT  2.16 49.005 54 49.275 ;
     RECT  2.16 49.545 54 49.815 ;
     RECT  2.16 50.085 54 50.355 ;
     RECT  2.16 50.625 54 50.895 ;
     RECT  2.16 51.165 54 51.435 ;
     RECT  2.16 51.705 54 51.975 ;
     RECT  2.16 52.245 54 52.515 ;
     RECT  2.16 52.785 54 53.055 ;
     RECT  2.16 53.325 54 53.595 ;
     RECT  2.16 53.865 54 54 ;
    LAYER RVTP ;
     RECT  2.16 2.295 54 2.565 ;
     RECT  2.16 2.835 54 3.105 ;
     RECT  2.16 3.375 54 3.645 ;
     RECT  2.16 3.915 54 4.185 ;
     RECT  2.16 4.455 54 4.725 ;
     RECT  2.16 4.995 54 5.265 ;
     RECT  2.16 5.535 54 5.805 ;
     RECT  2.16 6.075 54 6.345 ;
     RECT  2.16 6.615 54 6.885 ;
     RECT  2.16 7.155 54 7.425 ;
     RECT  2.16 7.695 54 7.965 ;
     RECT  2.16 8.235 54 8.505 ;
     RECT  2.16 8.775 54 9.045 ;
     RECT  2.16 9.315 54 9.585 ;
     RECT  2.16 9.855 54 10.125 ;
     RECT  2.16 10.395 54 10.665 ;
     RECT  2.16 10.935 54 11.205 ;
     RECT  2.16 11.475 54 11.745 ;
     RECT  2.16 12.015 54 12.285 ;
     RECT  2.16 12.555 54 12.825 ;
     RECT  2.16 13.095 54 13.365 ;
     RECT  2.16 13.635 54 13.905 ;
     RECT  2.16 14.175 54 14.445 ;
     RECT  2.16 14.715 54 14.985 ;
     RECT  2.16 15.255 54 15.525 ;
     RECT  2.16 15.795 54 16.065 ;
     RECT  2.16 16.335 54 16.605 ;
     RECT  2.16 16.875 54 17.145 ;
     RECT  2.16 17.415 54 17.685 ;
     RECT  2.16 17.955 54 18.225 ;
     RECT  2.16 18.495 54 18.765 ;
     RECT  2.16 19.035 54 19.305 ;
     RECT  2.16 19.575 54 19.845 ;
     RECT  2.16 20.115 54 20.385 ;
     RECT  2.16 20.655 54 20.925 ;
     RECT  2.16 21.195 54 21.465 ;
     RECT  2.16 21.735 54 22.005 ;
     RECT  2.16 22.275 54 22.545 ;
     RECT  2.16 22.815 54 23.085 ;
     RECT  2.16 23.355 54 23.625 ;
     RECT  2.16 23.895 54 24.165 ;
     RECT  2.16 24.435 54 24.705 ;
     RECT  2.16 24.975 54 25.245 ;
     RECT  2.16 25.515 54 25.785 ;
     RECT  2.16 26.055 54 26.325 ;
     RECT  2.16 26.595 54 26.865 ;
     RECT  2.16 27.135 54 27.405 ;
     RECT  2.16 27.675 54 27.945 ;
     RECT  2.16 28.215 54 28.485 ;
     RECT  2.16 28.755 54 29.025 ;
     RECT  2.16 29.295 54 29.565 ;
     RECT  2.16 29.835 54 30.105 ;
     RECT  2.16 30.375 54 30.645 ;
     RECT  2.16 30.915 54 31.185 ;
     RECT  2.16 31.455 54 31.725 ;
     RECT  2.16 31.995 54 32.265 ;
     RECT  2.16 32.535 54 32.805 ;
     RECT  2.16 33.075 54 33.345 ;
     RECT  2.16 33.615 54 33.885 ;
     RECT  2.16 34.155 54 34.425 ;
     RECT  2.16 34.695 54 34.965 ;
     RECT  2.16 35.235 54 35.505 ;
     RECT  2.16 35.775 54 36.045 ;
     RECT  2.16 36.315 54 36.585 ;
     RECT  2.16 36.855 54 37.125 ;
     RECT  2.16 37.395 54 37.665 ;
     RECT  2.16 37.935 54 38.205 ;
     RECT  2.16 38.475 54 38.745 ;
     RECT  2.16 39.015 54 39.285 ;
     RECT  2.16 39.555 54 39.825 ;
     RECT  2.16 40.095 54 40.365 ;
     RECT  2.16 40.635 54 40.905 ;
     RECT  2.16 41.175 54 41.445 ;
     RECT  2.16 41.715 54 41.985 ;
     RECT  2.16 42.255 54 42.525 ;
     RECT  2.16 42.795 54 43.065 ;
     RECT  2.16 43.335 54 43.605 ;
     RECT  2.16 43.875 54 44.145 ;
     RECT  2.16 44.415 54 44.685 ;
     RECT  2.16 44.955 54 45.225 ;
     RECT  2.16 45.495 54 45.765 ;
     RECT  2.16 46.035 54 46.305 ;
     RECT  2.16 46.575 54 46.845 ;
     RECT  2.16 47.115 54 47.385 ;
     RECT  2.16 47.655 54 47.925 ;
     RECT  2.16 48.195 54 48.465 ;
     RECT  2.16 48.735 54 49.005 ;
     RECT  2.16 49.275 54 49.545 ;
     RECT  2.16 49.815 54 50.085 ;
     RECT  2.16 50.355 54 50.625 ;
     RECT  2.16 50.895 54 51.165 ;
     RECT  2.16 51.435 54 51.705 ;
     RECT  2.16 51.975 54 52.245 ;
     RECT  2.16 52.515 54 52.785 ;
     RECT  2.16 53.055 54 53.325 ;
     RECT  2.16 53.595 54 53.865 ;
    LAYER M1 ;
     RECT  2.16 2.151 54 54.009 ;
    LAYER M2 ;
     RECT  0.031 10.566 0.067 10.584 ;
     RECT  0.067 10.566 0.103 10.809 ;
     RECT  0.067 11.646 0.103 11.664 ;
     RECT  0.031 28.998 0.103 29.016 ;
     RECT  0.067 48.708 0.103 48.726 ;
     RECT  0.031 6.741 0.139 6.759 ;
     RECT  0.103 10.566 0.139 11.664 ;
     RECT  0.067 31.311 0.139 31.329 ;
     RECT  0.031 47.826 0.139 47.844 ;
     RECT  0.139 10.566 0.211 11.772 ;
     RECT  0.175 12.834 0.211 12.852 ;
     RECT  0.103 28.998 0.211 29.322 ;
     RECT  0.139 47.556 0.211 47.844 ;
     RECT  0.139 4.968 0.275 4.986 ;
     RECT  0.175 51.912 0.275 51.93 ;
     RECT  0.175 9.486 0.283 9.504 ;
     RECT  0.211 14.688 0.311 15.129 ;
     RECT  0.211 15.966 0.311 19.134 ;
     RECT  0.211 21.132 0.311 21.609 ;
     RECT  0.211 22.896 0.311 25.119 ;
     RECT  0.211 26.298 0.311 26.316 ;
     RECT  0.211 34.056 0.311 34.074 ;
     RECT  0.211 40.878 0.311 40.896 ;
     RECT  0.211 42.192 0.311 43.362 ;
     RECT  0.211 44.118 0.311 44.874 ;
     RECT  0.211 53.568 0.311 53.586 ;
     RECT  0.139 6.741 0.319 6.84 ;
     RECT  0.283 8.946 0.319 9.504 ;
     RECT  0.211 10.566 0.319 12.852 ;
     RECT  0.211 2.844 0.347 2.862 ;
     RECT  0.319 8.946 0.383 12.852 ;
     RECT  0.355 5.661 0.455 5.679 ;
     RECT  0.211 47.322 0.463 47.844 ;
     RECT  0.103 48.636 0.463 48.726 ;
     RECT  0.211 50.868 0.463 50.886 ;
     RECT  0.211 28.341 0.499 30.096 ;
     RECT  0.311 44.694 0.499 44.874 ;
     RECT  0.463 47.322 0.499 47.88 ;
     RECT  0.463 48.636 0.499 49.464 ;
     RECT  0.211 27.144 0.535 27.162 ;
     RECT  0.499 28.341 0.535 30.168 ;
     RECT  0.499 44.694 0.535 45.324 ;
     RECT  0.499 46.476 0.535 46.494 ;
     RECT  0.499 47.322 0.535 49.464 ;
     RECT  0.463 50.868 0.535 51.264 ;
     RECT  0.571 32.58 0.607 32.598 ;
     RECT  0.571 37.17 0.607 37.188 ;
     RECT  0.535 44.694 0.635 51.264 ;
     RECT  0.607 32.076 0.643 32.598 ;
     RECT  0.571 33.624 0.643 33.642 ;
     RECT  0.607 37.17 0.643 37.314 ;
     RECT  0.643 37.17 0.679 37.422 ;
     RECT  0.679 37.134 0.751 37.422 ;
     RECT  0.787 38.754 0.823 38.772 ;
     RECT  0.139 31.194 0.895 31.329 ;
     RECT  0.643 32.076 0.895 33.642 ;
     RECT  0.895 31.194 0.931 33.642 ;
     RECT  0.823 38.754 0.931 38.808 ;
     RECT  0.931 31.041 0.967 33.642 ;
     RECT  0.931 38.754 0.967 38.934 ;
     RECT  0.967 30.96 1.003 33.642 ;
     RECT  0.751 37.134 1.003 37.764 ;
     RECT  0.967 38.556 1.003 38.934 ;
     RECT  0.535 27.144 1.039 30.168 ;
     RECT  1.003 30.924 1.039 33.642 ;
     RECT  0.175 36.126 1.039 36.144 ;
     RECT  1.003 37.134 1.039 38.934 ;
     RECT  1.039 27.144 1.075 33.642 ;
     RECT  1.039 36.126 1.075 38.934 ;
     RECT  0.211 39.726 1.075 39.744 ;
     RECT  1.075 27.144 1.111 33.948 ;
     RECT  1.075 34.704 1.111 40.014 ;
     RECT  1.147 5.706 1.183 5.724 ;
     RECT  0.319 6.516 1.183 6.84 ;
     RECT  0.383 8.946 1.183 12.078 ;
     RECT  0.383 12.834 1.183 12.852 ;
     RECT  1.111 27.144 1.211 40.014 ;
     RECT  0.211 8.046 1.219 8.064 ;
     RECT  1.183 5.706 1.399 6.84 ;
     RECT  1.219 7.596 1.399 8.064 ;
     RECT  0.311 17.586 1.435 17.604 ;
     RECT  1.399 5.706 1.471 8.064 ;
     RECT  1.183 8.946 1.471 12.852 ;
     RECT  1.471 5.706 1.507 12.852 ;
     RECT  0.311 43.344 1.543 43.362 ;
     RECT  0.635 44.694 1.579 49.572 ;
     RECT  0.247 3.924 1.687 3.942 ;
     RECT  1.399 18.576 1.975 18.594 ;
     RECT  1.687 3.924 2.083 4.518 ;
     RECT  1.507 5.436 2.083 12.924 ;
     RECT  1.211 27.144 2.083 35.226 ;
     RECT  1.211 36.126 2.083 40.014 ;
     RECT  0.535 2.034 2.16 2.052 ;
     RECT  2.083 3.924 2.16 12.924 ;
     RECT  0.311 14.688 2.16 14.976 ;
     RECT  0.311 16.416 2.16 16.434 ;
     RECT  1.435 17.496 2.16 17.604 ;
     RECT  1.975 18.576 2.16 18.792 ;
     RECT  0.211 20.196 2.16 20.214 ;
     RECT  0.311 21.546 2.16 21.564 ;
     RECT  0.311 22.896 2.16 23.994 ;
     RECT  0.311 25.056 2.16 25.074 ;
     RECT  2.083 27.144 2.16 40.014 ;
     RECT  1.543 43.002 2.16 43.362 ;
     RECT  1.579 44.496 2.16 49.572 ;
     RECT  0.635 50.634 2.16 51.264 ;
     RECT  2.16 2.034 2.615 54.009 ;
     RECT  2.587 0.144 2.759 0.162 ;
     RECT  2.839 1.152 2.939 1.17 ;
     RECT  2.615 2.106 3.343 54.009 ;
     RECT  3.343 1.728 4.091 54.009 ;
     RECT  4.091 2.151 5.287 54.009 ;
     RECT  4.999 0.144 5.467 0.162 ;
     RECT  5.467 0.144 5.567 0.234 ;
     RECT  5.287 2.106 6.179 54.009 ;
     RECT  5.567 0.144 6.755 0.162 ;
     RECT  6.179 2.151 7.159 54.009 ;
     RECT  7.159 2.106 7.979 54.009 ;
     RECT  7.699 0.144 8.159 0.162 ;
     RECT  7.979 2.151 8.779 54.009 ;
     RECT  8.779 2.106 9.283 54.009 ;
     RECT  9.283 2.07 10.211 54.009 ;
     RECT  10.507 0.144 10.679 0.162 ;
     RECT  10.211 2.151 11.299 54.009 ;
     RECT  11.299 1.728 12.011 54.009 ;
     RECT  12.011 2.106 13.063 54.009 ;
     RECT  13.063 1.728 13.127 54.009 ;
     RECT  13.351 1.224 13.531 1.242 ;
     RECT  13.207 0.144 13.559 0.162 ;
     RECT  13.531 1.152 13.631 1.242 ;
     RECT  13.127 2.151 13.999 54.009 ;
     RECT  13.999 1.728 14.315 54.009 ;
     RECT  14.395 0.144 14.683 0.162 ;
     RECT  14.683 0.144 14.783 0.234 ;
     RECT  14.783 0.144 15.971 0.162 ;
     RECT  16.519 0.306 16.807 0.324 ;
     RECT  16.807 0.144 16.907 0.324 ;
     RECT  16.807 1.152 16.943 1.17 ;
     RECT  14.315 2.151 17.095 54.009 ;
     RECT  17.671 0.144 17.771 0.162 ;
     RECT  18.823 0.306 18.967 0.324 ;
     RECT  18.967 0.144 19.067 0.324 ;
     RECT  17.095 1.728 19.499 54.009 ;
     RECT  21.343 0.144 22.811 0.162 ;
     RECT  24.043 0.144 24.359 0.162 ;
     RECT  19.499 2.151 25.195 54.009 ;
     RECT  24.439 0.576 25.547 0.594 ;
     RECT  25.195 1.728 25.691 54.009 ;
     RECT  25.691 1.8 25.763 54.009 ;
     RECT  26.671 0.144 27.167 0.162 ;
     RECT  25.763 2.151 28.291 54.009 ;
     RECT  28.291 1.728 28.967 54.009 ;
     RECT  28.967 1.8 29.579 54.009 ;
     RECT  29.659 0.144 29.759 0.162 ;
     RECT  29.579 2.151 31.999 54.009 ;
     RECT  32.359 0.144 32.459 0.162 ;
     RECT  31.999 1.728 32.819 54.009 ;
     RECT  34.411 0.144 35.159 0.162 ;
     RECT  32.819 2.151 38.155 54.009 ;
     RECT  38.767 0.144 38.939 0.162 ;
     RECT  38.155 1.728 39.587 54.009 ;
     RECT  39.587 2.106 39.983 54.009 ;
     RECT  40.171 0.144 40.883 0.162 ;
     RECT  39.983 2.151 40.891 54.009 ;
     RECT  40.891 1.728 41.459 54.009 ;
     RECT  41.863 0.576 42.863 0.594 ;
     RECT  41.459 2.106 43.195 54.009 ;
     RECT  43.015 0.144 43.259 0.162 ;
     RECT  43.195 1.728 44.231 54.009 ;
     RECT  44.231 2.151 44.959 54.009 ;
     RECT  44.959 1.728 45.527 54.009 ;
     RECT  45.715 0.144 46.139 0.162 ;
     RECT  45.527 2.151 46.507 54.009 ;
     RECT  46.507 1.728 46.967 54.009 ;
     RECT  46.967 2.151 47.839 54.009 ;
     RECT  47.839 1.728 47.975 54.009 ;
     RECT  48.271 0.144 48.443 0.162 ;
     RECT  49.387 0.144 49.487 0.162 ;
     RECT  47.975 2.106 50.935 54.009 ;
     RECT  51.439 0.144 51.755 0.162 ;
     RECT  50.935 1.728 53.123 54.009 ;
     RECT  53.123 2.106 54 54.009 ;
     RECT  54 2.106 54.012 53.739 ;
     RECT  54.012 2.106 54.059 7.416 ;
     RECT  54.012 9.09 54.059 9.234 ;
     RECT  54.059 2.106 54.095 7.38 ;
     RECT  54.012 8.172 54.095 8.19 ;
     RECT  54.095 2.106 54.131 3.978 ;
     RECT  54.095 5.346 54.131 7.38 ;
     RECT  54.131 2.268 54.167 3.978 ;
     RECT  54.131 5.346 54.167 6.84 ;
     RECT  54.167 5.346 54.203 5.364 ;
     RECT  54.167 2.268 54.239 3.33 ;
     RECT  54.167 6.39 54.239 6.84 ;
     RECT  54.239 3.312 54.275 3.33 ;
     RECT  54.059 9.216 54.275 9.234 ;
     RECT  54.239 2.268 54.311 2.286 ;
     RECT  54.239 6.39 54.311 6.408 ;
    LAYER M3 ;
     RECT  2.196 0.108 53.874 0.173 ;
     RECT  2.196 0.173 32.958 0.269 ;
     RECT  33.912 0.173 53.874 0.365 ;
     RECT  20.376 0.269 32.958 0.557 ;
     RECT  33.912 0.365 37.242 0.557 ;
     RECT  20.376 0.557 22.914 0.605 ;
     RECT  20.592 0.605 22.914 1.723 ;
     RECT  23.688 0.557 32.958 1.723 ;
     RECT  36.036 0.557 37.242 2.011 ;
     RECT  37.98 0.365 53.874 2.011 ;
     RECT  36.036 2.011 54.09 2.101 ;
     RECT  2.196 0.269 19.638 2.191 ;
     RECT  20.592 1.723 32.958 2.191 ;
     RECT  33.912 0.557 35.154 2.191 ;
     RECT  36.036 2.101 54.126 2.191 ;
     RECT  2.196 2.191 32.958 2.203 ;
     RECT  1.512 2.203 32.958 2.251 ;
     RECT  33.696 2.191 54.126 2.251 ;
     RECT  1.512 2.251 54.126 2.263 ;
     RECT  0.54 2.029 0.558 2.587 ;
     RECT  1.512 2.263 54.306 2.779 ;
     RECT  0.216 2.587 0.558 3.547 ;
     RECT  1.404 2.779 54.306 3.547 ;
     RECT  0.216 3.547 54.306 4.963 ;
     RECT  0.144 4.963 54.306 6.413 ;
     RECT  0.144 6.413 54.27 6.736 ;
     RECT  0.036 6.736 54.27 9.239 ;
     RECT  0.036 9.239 54.054 10.589 ;
     RECT  0.072 10.589 54.054 11.669 ;
     RECT  0.144 11.669 54.054 11.777 ;
     RECT  0.18 11.777 54.054 12.029 ;
     RECT  0.18 12.029 53.997 12.083 ;
     RECT  1.152 12.083 53.997 12.281 ;
     RECT  1.152 12.281 3.87 12.353 ;
     RECT  0.18 12.083 0.378 12.389 ;
     RECT  4.68 12.281 53.997 12.479 ;
     RECT  1.152 12.353 3.834 12.515 ;
     RECT  2.34 12.515 3.834 12.557 ;
     RECT  4.68 12.479 10.998 12.557 ;
     RECT  4.968 12.557 9.306 12.587 ;
     RECT  10.26 12.557 10.998 12.587 ;
     RECT  0.18 12.389 0.306 12.845 ;
     RECT  0.18 12.845 0.27 12.857 ;
     RECT  11.952 12.479 53.997 12.893 ;
     RECT  1.152 12.515 1.53 12.929 ;
     RECT  1.152 12.929 1.17 12.989 ;
     RECT  12.024 12.893 53.997 13.019 ;
     RECT  5.004 12.587 9.306 13.055 ;
     RECT  5.004 13.055 8.802 13.091 ;
     RECT  12.528 13.019 53.997 13.163 ;
     RECT  12.564 13.163 53.997 13.199 ;
     RECT  0.252 12.857 0.27 13.277 ;
     RECT  10.26 12.587 10.797 13.297 ;
     RECT  5.004 13.091 8.694 13.325 ;
     RECT  3.996 13.147 4.014 13.339 ;
     RECT  2.34 12.557 3.258 13.432 ;
     RECT  3.996 13.339 4.05 13.433 ;
     RECT  3.996 13.433 4.014 13.469 ;
     RECT  5.004 13.325 6.498 13.531 ;
     RECT  4.968 13.531 6.498 13.559 ;
     RECT  13.215 13.199 53.997 13.559 ;
     RECT  4.968 13.559 5.994 13.568 ;
     RECT  13.215 13.559 13.698 13.631 ;
     RECT  9.936 13.297 10.797 13.837 ;
     RECT  7.488 13.325 8.694 13.873 ;
     RECT  9.936 13.837 10.854 13.873 ;
     RECT  7.488 13.873 10.854 13.973 ;
     RECT  2.304 13.432 3.258 14.011 ;
     RECT  2.304 14.011 3.51 14.045 ;
     RECT  2.415 14.045 3.51 14.141 ;
     RECT  2.415 14.141 3.438 14.189 ;
     RECT  5.004 13.568 5.994 14.243 ;
     RECT  7.488 13.973 10.797 14.413 ;
     RECT  0.36 14.587 0.378 14.668 ;
     RECT  0.216 14.668 0.378 14.711 ;
     RECT  14.436 13.559 53.997 14.747 ;
     RECT  14.436 14.747 15.03 14.783 ;
     RECT  15.876 14.747 53.997 14.819 ;
     RECT  7.092 14.413 10.797 14.989 ;
     RECT  14.436 14.783 14.994 15.017 ;
     RECT  2.415 14.189 3.366 15.151 ;
     RECT  7.092 14.989 10.818 15.163 ;
     RECT  6.948 15.163 10.818 15.211 ;
     RECT  6.84 15.211 10.818 15.215 ;
     RECT  6.84 15.215 8.766 15.341 ;
     RECT  9.612 15.215 10.818 15.565 ;
     RECT  5.115 14.243 5.994 15.592 ;
     RECT  15.915 14.819 53.997 15.601 ;
     RECT  9.612 15.565 10.926 15.763 ;
     RECT  9.612 15.763 10.998 15.863 ;
     RECT  6.876 15.341 8.766 15.899 ;
     RECT  14.436 15.017 14.958 15.899 ;
     RECT  15.804 15.601 53.997 16.025 ;
     RECT  2.304 15.151 3.366 16.169 ;
     RECT  5.004 15.592 5.994 16.169 ;
     RECT  9.612 15.863 10.926 16.231 ;
     RECT  9.504 16.231 10.926 16.315 ;
     RECT  14.436 15.899 14.85 16.339 ;
     RECT  14.256 16.339 14.85 16.681 ;
     RECT  14.256 16.681 14.922 16.871 ;
     RECT  9.144 16.315 10.926 16.951 ;
     RECT  14.256 16.871 14.886 16.979 ;
     RECT  6.876 15.899 8.262 17.083 ;
     RECT  9 16.951 10.926 17.105 ;
     RECT  0.216 14.711 0.306 17.213 ;
     RECT  2.415 16.169 3.366 17.311 ;
     RECT  4.32 16.915 4.338 17.311 ;
     RECT  5.115 16.169 5.994 17.311 ;
     RECT  4.32 17.311 5.994 17.357 ;
     RECT  6.84 17.083 8.262 17.357 ;
     RECT  14.256 16.979 14.67 17.789 ;
     RECT  6.876 17.357 8.262 17.923 ;
     RECT  14.436 17.789 14.67 17.923 ;
     RECT  9.684 17.105 10.926 18.031 ;
     RECT  14.436 17.923 14.85 18.059 ;
     RECT  9.684 18.031 11.034 18.121 ;
     RECT  0.216 17.213 0.234 18.139 ;
     RECT  15.915 16.025 53.997 18.221 ;
     RECT  4.32 17.357 4.338 18.283 ;
     RECT  5.115 17.357 5.994 18.283 ;
     RECT  6.876 17.923 8.55 18.283 ;
     RECT  4.32 18.283 5.994 18.329 ;
     RECT  6.84 18.283 8.55 18.461 ;
     RECT  9.684 18.121 11.178 18.499 ;
     RECT  5.115 18.329 5.994 18.563 ;
     RECT  1.44 17.491 1.458 18.571 ;
     RECT  1.404 18.571 1.458 18.769 ;
     RECT  2.304 17.311 3.366 18.769 ;
     RECT  4.32 18.329 4.338 18.769 ;
     RECT  9.684 18.499 11.574 18.797 ;
     RECT  14.436 18.059 14.67 18.805 ;
     RECT  10.44 18.797 11.574 18.845 ;
     RECT  10.476 18.845 11.574 18.869 ;
     RECT  0.216 18.139 0.306 19.148 ;
     RECT  5.115 18.563 5.49 19.309 ;
     RECT  10.515 18.869 11.574 19.381 ;
     RECT  1.404 18.769 4.338 19.471 ;
     RECT  5.115 19.309 5.922 19.471 ;
     RECT  10.515 19.381 12.078 19.531 ;
     RECT  14.436 18.805 14.778 19.615 ;
     RECT  7.092 18.461 8.55 19.661 ;
     RECT  0.252 19.148 0.27 19.757 ;
     RECT  7.092 19.661 8.097 20.011 ;
     RECT  10.515 19.531 12.15 20.011 ;
     RECT  1.404 19.471 5.922 20.048 ;
     RECT  6.948 20.011 8.097 20.107 ;
     RECT  0.216 20.191 0.234 20.237 ;
     RECT  6.84 20.107 8.097 20.237 ;
     RECT  10.515 20.011 12.222 20.309 ;
     RECT  10.515 20.309 11.718 20.333 ;
     RECT  13.215 13.631 13.497 20.551 ;
     RECT  12.672 20.551 13.497 20.651 ;
     RECT  10.515 20.333 11.61 21.091 ;
     RECT  0.252 20.923 0.27 21.127 ;
     RECT  7.416 20.237 8.097 21.127 ;
     RECT  7.416 21.127 8.55 21.197 ;
     RECT  7.416 21.197 8.097 21.259 ;
     RECT  10.515 21.091 11.898 21.361 ;
     RECT  7.02 21.259 8.097 21.403 ;
     RECT  6.876 21.403 8.097 21.461 ;
     RECT  14.436 19.615 14.814 21.533 ;
     RECT  1.404 20.048 4.338 21.631 ;
     RECT  5.115 20.048 5.922 21.631 ;
     RECT  1.404 21.631 5.922 21.739 ;
     RECT  15.915 18.221 18.897 21.739 ;
     RECT  19.656 18.221 53.997 21.739 ;
     RECT  10.515 21.361 12.114 21.811 ;
     RECT  13.215 20.651 13.497 21.811 ;
     RECT  0.216 21.127 0.306 21.821 ;
     RECT  0.216 21.821 0.234 21.869 ;
     RECT  15.915 21.739 53.997 22.109 ;
     RECT  6.912 21.461 8.097 22.157 ;
     RECT  14.436 21.533 14.778 22.199 ;
     RECT  7.815 22.157 8.097 22.315 ;
     RECT  19.656 22.109 53.997 22.343 ;
     RECT  10.515 21.811 13.497 22.513 ;
     RECT  6.912 22.157 6.966 22.555 ;
     RECT  22.968 22.343 53.997 22.577 ;
     RECT  7.815 22.315 8.154 22.649 ;
     RECT  1.152 21.739 5.922 22.781 ;
     RECT  6.84 22.555 6.966 22.781 ;
     RECT  10.515 22.513 13.554 22.783 ;
     RECT  10.515 22.783 13.626 22.847 ;
     RECT  14.436 22.199 14.67 22.981 ;
     RECT  23.364 22.577 53.997 23.045 ;
     RECT  14.436 22.981 14.886 23.053 ;
     RECT  0.216 22.891 0.234 23.131 ;
     RECT  14.436 23.053 14.958 23.251 ;
     RECT  23.724 23.045 53.997 23.279 ;
     RECT  10.515 22.847 13.497 23.357 ;
     RECT  14.22 23.251 14.958 23.395 ;
     RECT  7.02 23.419 7.038 23.597 ;
     RECT  14.22 23.395 15.066 23.629 ;
     RECT  19.656 22.343 21.978 23.629 ;
     RECT  0.216 23.131 0.306 23.693 ;
     RECT  23.724 23.279 41.994 23.693 ;
     RECT  14.22 23.629 15.102 23.729 ;
     RECT  1.404 22.781 4.338 23.791 ;
     RECT  5.115 22.781 5.922 23.791 ;
     RECT  14.22 23.729 15.03 23.819 ;
     RECT  14.22 23.819 14.922 23.891 ;
     RECT  1.404 23.791 5.922 23.933 ;
     RECT  6.84 23.659 7.002 23.933 ;
     RECT  12.276 23.357 13.497 23.935 ;
     RECT  14.22 23.891 14.886 23.935 ;
     RECT  12.276 23.935 14.886 23.999 ;
     RECT  10.515 23.357 11.538 24.091 ;
     RECT  19.656 23.629 22.266 24.269 ;
     RECT  6.84 23.933 6.966 24.413 ;
     RECT  0.216 23.693 0.234 24.427 ;
     RECT  23.724 23.693 41.922 24.431 ;
     RECT  1.404 23.933 4.338 24.715 ;
     RECT  13.215 23.999 14.886 24.745 ;
     RECT  6.876 24.413 6.966 24.763 ;
     RECT  1.152 24.715 4.338 24.781 ;
     RECT  5.076 23.933 5.922 24.781 ;
     RECT  1.152 24.781 5.922 24.941 ;
     RECT  22.824 24.871 22.842 25.015 ;
     RECT  23.724 24.431 40.626 25.015 ;
     RECT  41.436 24.431 41.922 25.043 ;
     RECT  0.216 24.427 0.306 25.045 ;
     RECT  0.216 25.045 0.342 25.085 ;
     RECT  22.824 25.015 40.626 25.169 ;
     RECT  6.876 24.763 7.038 25.243 ;
     RECT  13.215 24.745 14.958 25.321 ;
     RECT  0.216 25.085 0.306 25.325 ;
     RECT  6.84 25.243 7.038 25.339 ;
     RECT  0.216 25.325 0.234 25.373 ;
     RECT  42.915 23.279 53.997 25.411 ;
     RECT  42.768 25.411 53.997 25.511 ;
     RECT  15.915 22.109 18.897 25.555 ;
     RECT  19.656 24.269 21.978 25.555 ;
     RECT  6.84 25.339 7.074 25.627 ;
     RECT  7.815 22.649 8.097 25.627 ;
     RECT  13.215 25.321 15.066 25.717 ;
     RECT  15.915 25.555 21.978 25.717 ;
     RECT  13.215 25.717 21.978 25.889 ;
     RECT  1.404 24.941 4.338 25.951 ;
     RECT  5.115 24.941 5.922 25.951 ;
     RECT  22.824 25.169 22.842 26.051 ;
     RECT  13.215 25.889 18.897 26.123 ;
     RECT  10.515 24.091 11.97 26.257 ;
     RECT  0.288 26.059 0.306 26.284 ;
     RECT  10.515 26.257 12.006 26.381 ;
     RECT  13.215 26.123 13.497 26.491 ;
     RECT  0.216 26.284 0.306 26.573 ;
     RECT  22.86 26.365 22.878 26.663 ;
     RECT  6.84 25.627 8.097 26.669 ;
     RECT  13.104 26.491 13.497 26.875 ;
     RECT  14.436 26.123 18.897 27.031 ;
     RECT  10.515 26.381 11.97 27.163 ;
     RECT  14.328 27.031 18.897 27.167 ;
     RECT  10.515 27.163 12.078 27.301 ;
     RECT  13.068 26.875 13.497 27.301 ;
     RECT  10.515 27.301 13.497 27.341 ;
     RECT  12.564 27.341 13.497 27.389 ;
     RECT  6.84 26.669 6.966 27.481 ;
     RECT  0.216 26.573 0.234 27.547 ;
     RECT  0.216 27.547 0.414 27.877 ;
     RECT  14.4 27.167 18.897 27.917 ;
     RECT  12.78 27.389 13.497 27.965 ;
     RECT  1.404 25.951 5.922 28.021 ;
     RECT  6.66 27.481 6.966 28.021 ;
     RECT  13.104 27.965 13.497 28.157 ;
     RECT  10.515 27.341 11.43 28.213 ;
     RECT  1.404 28.021 6.966 28.253 ;
     RECT  10.515 28.213 11.97 28.253 ;
     RECT  22.932 28.759 22.95 28.831 ;
     RECT  22.896 28.831 22.95 28.921 ;
     RECT  23.724 25.169 40.626 28.921 ;
     RECT  0.216 27.877 0.558 28.993 ;
     RECT  22.824 28.921 40.626 29.021 ;
     RECT  22.824 29.021 22.95 29.057 ;
     RECT  1.404 28.253 6.678 29.083 ;
     RECT  13.215 28.157 13.497 29.083 ;
     RECT  13.104 29.083 13.497 29.129 ;
     RECT  14.436 27.917 18.897 29.255 ;
     RECT  1.404 29.083 6.858 29.261 ;
     RECT  22.86 29.057 22.95 29.327 ;
     RECT  22.86 29.327 22.878 29.363 ;
     RECT  10.515 28.253 11.43 29.399 ;
     RECT  15.66 29.255 18.897 29.839 ;
     RECT  19.656 25.889 21.978 29.839 ;
     RECT  14.436 29.255 14.886 30.145 ;
     RECT  15.66 29.839 21.978 30.145 ;
     RECT  23.724 29.021 40.626 30.271 ;
     RECT  14.436 30.145 21.978 30.569 ;
     RECT  0.036 28.993 0.558 30.649 ;
     RECT  1.404 29.261 6.678 30.649 ;
     RECT  0.036 30.649 6.678 30.811 ;
     RECT  13.215 29.129 13.497 30.811 ;
     RECT  15.732 30.569 21.978 30.893 ;
     RECT  22.824 30.613 22.842 30.919 ;
     RECT  23.616 30.271 40.626 30.919 ;
     RECT  0.036 30.811 6.858 30.941 ;
     RECT  15.804 30.893 21.978 30.947 ;
     RECT  15.876 30.947 21.978 31.019 ;
     RECT  14.436 30.569 14.886 31.109 ;
     RECT  15.915 31.019 21.978 31.181 ;
     RECT  9.684 18.797 9.702 31.243 ;
     RECT  10.515 29.399 10.797 31.243 ;
     RECT  9.684 31.243 10.797 31.289 ;
     RECT  13.104 30.811 13.497 31.289 ;
     RECT  19.656 31.181 21.978 31.387 ;
     RECT  22.824 30.919 40.626 31.387 ;
     RECT  14.436 31.109 14.85 31.649 ;
     RECT  42.915 25.511 53.997 31.657 ;
     RECT  15.915 31.181 18.897 32.567 ;
     RECT  42.444 31.657 53.997 32.909 ;
     RECT  14.436 31.649 14.67 33.151 ;
     RECT  0.036 30.941 6.678 33.307 ;
     RECT  10.515 31.289 10.797 33.349 ;
     RECT  13.215 31.289 13.497 33.403 ;
     RECT  0.036 33.307 6.858 33.437 ;
     RECT  14.436 33.151 14.85 33.437 ;
     RECT  10.515 33.349 10.854 33.449 ;
     RECT  13.104 33.403 13.497 33.449 ;
     RECT  0.036 33.437 6.678 33.647 ;
     RECT  1.044 33.647 6.678 33.965 ;
     RECT  44.244 32.909 53.997 33.989 ;
     RECT  0.036 33.647 0.306 34.109 ;
     RECT  14.436 33.437 14.67 34.219 ;
     RECT  1.08 33.965 6.678 34.459 ;
     RECT  10.515 33.449 10.797 34.459 ;
     RECT  44.244 33.989 44.694 34.493 ;
     RECT  13.215 33.449 13.497 34.591 ;
     RECT  1.08 34.459 6.858 34.603 ;
     RECT  19.656 31.387 40.626 34.655 ;
     RECT  10.515 34.459 10.818 34.733 ;
     RECT  41.436 25.043 41.562 34.799 ;
     RECT  1.08 34.603 6.966 35.005 ;
     RECT  7.815 26.669 8.097 35.005 ;
     RECT  13.104 34.591 13.497 35.069 ;
     RECT  14.436 34.219 14.85 35.069 ;
     RECT  42.444 32.909 43.506 35.069 ;
     RECT  35.892 34.655 40.626 35.339 ;
     RECT  0.036 34.109 0.162 35.467 ;
     RECT  1.08 35.005 8.097 35.467 ;
     RECT  19.656 34.655 35.097 36.049 ;
     RECT  14.436 35.069 14.67 36.235 ;
     RECT  35.892 35.339 36.162 36.319 ;
     RECT  37.116 35.339 40.626 36.319 ;
     RECT  19.656 36.049 35.154 36.391 ;
     RECT  35.892 36.319 40.626 36.391 ;
     RECT  14.436 36.235 14.85 36.413 ;
     RECT  19.656 36.391 40.626 36.419 ;
     RECT  19.656 36.419 35.097 37.085 ;
     RECT  37.296 36.419 40.626 37.193 ;
     RECT  19.656 37.085 31.014 37.319 ;
     RECT  44.28 34.493 44.694 37.391 ;
     RECT  31.752 37.085 35.097 37.463 ;
     RECT  31.752 37.463 33.57 37.499 ;
     RECT  34.452 37.463 35.097 38.039 ;
     RECT  15.915 32.567 16.197 38.101 ;
     RECT  16.92 32.567 18.897 38.101 ;
     RECT  15.915 38.101 18.897 38.141 ;
     RECT  19.656 37.319 30.978 38.371 ;
     RECT  31.752 37.499 33.498 38.371 ;
     RECT  44.676 37.391 44.694 38.399 ;
     RECT  37.515 37.193 40.626 38.669 ;
     RECT  37.515 38.669 40.497 38.777 ;
     RECT  0.036 35.467 8.097 38.813 ;
     RECT  37.515 38.777 38.394 38.813 ;
     RECT  19.656 38.371 33.498 39.281 ;
     RECT  19.656 39.281 32.706 39.515 ;
     RECT  19.656 39.515 32.397 39.587 ;
     RECT  0.036 38.813 0.198 39.721 ;
     RECT  0.936 38.813 8.097 39.721 ;
     RECT  19.656 39.587 31.302 39.749 ;
     RECT  19.656 39.749 31.05 39.869 ;
     RECT  14.436 36.413 14.67 39.883 ;
     RECT  33.48 39.281 33.498 39.929 ;
     RECT  0.036 39.721 8.097 40.061 ;
     RECT  19.656 39.869 30.762 40.091 ;
     RECT  19.656 40.091 30.114 40.157 ;
     RECT  45.432 33.989 53.997 40.163 ;
     RECT  35.82 36.419 36.162 40.199 ;
     RECT  0.036 40.061 0.342 40.253 ;
     RECT  1.08 40.061 8.097 40.541 ;
     RECT  19.656 40.157 29.97 40.559 ;
     RECT  19.656 40.559 29.826 40.637 ;
     RECT  0.036 40.253 0.306 40.973 ;
     RECT  13.215 35.069 13.497 41.071 ;
     RECT  14.436 39.883 14.85 41.083 ;
     RECT  41.436 34.799 41.454 41.099 ;
     RECT  30.744 41.071 30.762 41.171 ;
     RECT  10.515 34.733 10.797 41.179 ;
     RECT  14.436 41.083 14.958 41.213 ;
     RECT  10.515 41.179 10.818 41.243 ;
     RECT  9.684 31.289 9.702 41.512 ;
     RECT  10.515 41.243 10.797 41.512 ;
     RECT  15.915 38.141 16.197 41.512 ;
     RECT  9.684 41.512 10.797 41.549 ;
     RECT  15.804 41.512 16.197 41.549 ;
     RECT  0.036 40.973 0.234 41.707 ;
     RECT  13.104 41.071 13.497 41.881 ;
     RECT  45.615 40.163 53.997 41.909 ;
     RECT  35.82 40.199 35.838 41.945 ;
     RECT  1.152 40.541 8.097 42.077 ;
     RECT  0.036 41.707 0.27 42.172 ;
     RECT  0.036 42.172 0.306 43.133 ;
     RECT  19.656 40.637 29.697 43.565 ;
     RECT  8.82 35.743 8.838 43.573 ;
     RECT  45.615 41.909 47.538 43.601 ;
     RECT  8.82 43.573 8.874 43.661 ;
     RECT  14.436 41.213 14.85 43.709 ;
     RECT  0.036 43.133 0.234 44.059 ;
     RECT  19.656 43.565 28.206 44.141 ;
     RECT  8.856 43.661 8.874 44.149 ;
     RECT  9.684 41.549 9.702 44.149 ;
     RECT  0.036 44.059 0.306 44.761 ;
     RECT  12.6 41.881 13.497 44.879 ;
     RECT  10.515 41.549 10.797 44.887 ;
     RECT  48.315 41.909 53.997 44.915 ;
     RECT  1.404 42.077 8.097 44.923 ;
     RECT  8.856 44.149 9.702 44.923 ;
     RECT  10.515 44.887 10.926 44.987 ;
     RECT  12.78 44.879 13.497 44.987 ;
     RECT  28.044 44.141 28.206 45.005 ;
     RECT  14.436 43.709 14.67 45.019 ;
     RECT  0.036 44.761 0.558 45.259 ;
     RECT  49.356 44.915 53.997 45.329 ;
     RECT  0.036 45.259 0.666 45.389 ;
     RECT  19.656 44.141 26.997 45.485 ;
     RECT  19.656 45.485 25.47 45.725 ;
     RECT  13.215 44.987 13.497 45.805 ;
     RECT  1.404 44.923 9.702 45.833 ;
     RECT  15.915 41.549 16.197 45.931 ;
     RECT  28.188 45.005 28.206 45.965 ;
     RECT  15.804 45.931 16.197 45.968 ;
     RECT  16.92 38.141 18.897 45.995 ;
     RECT  26.676 45.485 26.997 46.061 ;
     RECT  20.592 45.725 25.47 46.109 ;
     RECT  18.615 45.995 18.897 46.267 ;
     RECT  20.772 46.109 25.47 46.301 ;
     RECT  18.615 46.267 18.918 46.397 ;
     RECT  24.015 46.301 25.47 46.589 ;
     RECT  1.404 45.833 8.097 46.637 ;
     RECT  13.104 45.805 13.497 46.651 ;
     RECT  12.528 46.651 13.497 46.925 ;
     RECT  49.356 45.329 51.714 47.039 ;
     RECT  20.772 46.301 23.166 47.117 ;
     RECT  22.536 47.117 23.166 47.165 ;
     RECT  24.015 46.589 25.29 47.453 ;
     RECT  8.856 45.833 9.702 47.615 ;
     RECT  19.656 45.725 19.854 47.615 ;
     RECT  22.536 47.165 22.554 47.741 ;
     RECT  49.356 47.039 51.297 47.759 ;
     RECT  0.036 45.389 0.558 47.849 ;
     RECT  14.436 45.019 14.85 47.885 ;
     RECT  49.356 47.759 49.95 48.191 ;
     RECT  42.444 35.069 43.197 48.227 ;
     RECT  9.396 47.615 9.702 48.425 ;
     RECT  0.072 47.849 0.558 48.731 ;
     RECT  16.92 45.995 17.622 48.731 ;
     RECT  52.704 45.329 53.997 48.803 ;
     RECT  24.015 47.453 24.534 48.839 ;
     RECT  14.436 47.885 14.454 49.243 ;
     RECT  20.772 47.117 21.597 49.243 ;
     RECT  25.272 47.453 25.29 49.277 ;
     RECT  45.615 43.601 47.034 49.307 ;
     RECT  14.436 49.243 14.85 49.373 ;
     RECT  20.772 49.243 21.69 49.373 ;
     RECT  22.824 49.243 22.842 49.373 ;
     RECT  2.415 46.637 8.097 49.775 ;
     RECT  0.18 48.731 0.558 49.867 ;
     RECT  0.18 49.867 0.63 49.919 ;
     RECT  39.6 38.777 40.497 50.045 ;
     RECT  2.415 49.775 5.922 50.161 ;
     RECT  49.356 48.191 49.446 50.459 ;
     RECT  9.684 48.425 9.702 50.585 ;
     RECT  2.304 50.161 5.922 50.729 ;
     RECT  9.108 50.701 9.126 50.909 ;
     RECT  10.515 44.987 10.797 51.097 ;
     RECT  2.376 50.729 5.922 51.101 ;
     RECT  6.768 49.775 8.097 51.169 ;
     RECT  2.415 51.101 5.922 51.197 ;
     RECT  10.515 51.097 10.854 51.197 ;
     RECT  6.768 51.169 8.442 51.269 ;
     RECT  0.18 49.919 0.558 51.293 ;
     RECT  0.18 51.293 0.522 51.581 ;
     RECT  14.436 49.373 14.454 51.665 ;
     RECT  0.18 51.581 0.486 51.677 ;
     RECT  13.215 46.925 13.497 51.691 ;
     RECT  49.428 50.459 49.446 51.701 ;
     RECT  13.104 51.691 13.497 51.737 ;
     RECT  0.18 51.677 0.342 51.935 ;
     RECT  5.115 51.197 5.922 51.935 ;
     RECT  1.404 46.637 1.566 52.061 ;
     RECT  0.252 51.935 0.342 52.157 ;
     RECT  41.976 51.883 41.994 52.169 ;
     RECT  53.064 48.803 53.997 52.205 ;
     RECT  19.656 47.615 19.674 52.241 ;
     RECT  6.768 51.269 8.097 52.277 ;
     RECT  2.415 51.197 4.338 52.312 ;
     RECT  41.292 52.285 41.778 52.439 ;
     RECT  40.215 50.045 40.497 52.459 ;
     RECT  20.772 49.373 21.597 52.511 ;
     RECT  5.115 51.935 5.706 52.541 ;
     RECT  40.215 52.459 40.554 52.583 ;
     RECT  0.252 52.157 0.27 52.637 ;
     RECT  2.304 52.312 4.338 52.681 ;
     RECT  5.115 52.541 5.397 52.681 ;
     RECT  41.292 52.439 41.49 52.709 ;
     RECT  16.92 48.731 17.586 52.745 ;
     RECT  41.292 52.709 41.418 52.825 ;
     RECT  7.092 52.277 8.097 52.853 ;
     RECT  45.615 49.307 46.458 53.087 ;
     RECT  17.568 52.745 17.586 53.123 ;
     RECT  1.548 52.061 1.566 53.213 ;
     RECT  41.22 52.825 41.418 53.249 ;
     RECT  40.215 52.583 40.497 53.329 ;
     RECT  41.22 53.249 41.274 53.329 ;
     RECT  7.128 52.853 8.097 53.357 ;
     RECT  0.216 53.467 0.234 53.515 ;
     RECT  40.215 53.329 41.274 53.519 ;
     RECT  2.304 52.681 5.397 53.549 ;
     RECT  40.215 53.519 41.202 53.555 ;
     RECT  0.216 53.515 0.306 53.591 ;
     RECT  2.304 53.549 4.086 53.645 ;
     RECT  3.492 53.645 4.086 53.693 ;
     RECT  7.38 53.357 8.097 53.699 ;
     RECT  2.304 53.645 2.697 53.747 ;
     RECT  5.115 53.549 5.397 53.747 ;
     RECT  7.815 53.699 8.097 53.747 ;
     RECT  10.515 51.197 10.797 53.747 ;
     RECT  13.215 51.737 13.497 53.747 ;
     RECT  15.915 45.968 16.197 53.747 ;
     RECT  18.615 46.397 18.897 53.747 ;
     RECT  21.315 52.511 21.597 53.747 ;
     RECT  24.015 48.839 24.297 53.747 ;
     RECT  26.715 46.061 26.997 53.747 ;
     RECT  29.415 43.565 29.697 53.747 ;
     RECT  32.115 39.587 32.397 53.747 ;
     RECT  34.815 38.039 35.097 53.747 ;
     RECT  37.515 38.813 37.797 53.747 ;
     RECT  40.215 53.555 41.166 53.747 ;
     RECT  42.915 48.227 43.197 53.747 ;
     RECT  45.615 53.087 45.897 53.747 ;
     RECT  48.315 44.915 48.597 53.747 ;
     RECT  51.015 47.759 51.297 53.747 ;
     RECT  53.715 52.205 53.997 53.747 ;
     RECT  0.252 53.591 0.27 53.789 ;
     RECT  41.076 53.747 41.166 53.789 ;
     RECT  2.304 53.747 2.505 53.905 ;
     RECT  4.068 53.693 4.086 53.933 ;
     RECT  2.268 53.905 2.505 53.981 ;
     RECT  41.076 53.789 41.094 53.981 ;
     RECT  2.415 53.981 2.505 54.017 ;
     RECT  5.115 53.747 5.205 54.017 ;
     RECT  7.815 53.747 7.905 54.017 ;
     RECT  10.515 53.747 10.605 54.017 ;
     RECT  13.215 53.747 13.305 54.017 ;
     RECT  15.915 53.747 16.005 54.017 ;
     RECT  18.615 53.747 18.705 54.017 ;
     RECT  21.315 53.747 21.405 54.017 ;
     RECT  24.015 53.747 24.105 54.017 ;
     RECT  26.715 53.747 26.805 54.017 ;
     RECT  29.415 53.747 29.505 54.017 ;
     RECT  32.115 53.747 32.205 54.017 ;
     RECT  34.815 53.747 34.905 54.017 ;
     RECT  37.515 53.747 37.605 54.017 ;
     RECT  40.215 53.747 40.305 54.017 ;
     RECT  42.915 53.747 43.005 54.017 ;
     RECT  45.615 53.747 45.705 54.017 ;
     RECT  48.315 53.747 48.405 54.017 ;
     RECT  51.015 53.747 51.105 54.017 ;
     RECT  53.715 53.747 53.805 54.017 ;
     RECT  15.12 55.291 15.138 56.028 ;
    LAYER M4 ;
     RECT  0.097 7.776 0.156 7.8 ;
     RECT  0.156 2.208 1.145 53.976 ;
     RECT  1.145 2.208 2.293 31.272 ;
     RECT  2.293 1.728 2.408 31.272 ;
     RECT  1.145 32.304 2.408 53.976 ;
     RECT  2.408 1.728 2.512 54.012 ;
     RECT  2.485 0.288 2.677 0.312 ;
     RECT  2.512 1.728 2.704 53.928 ;
     RECT  2.704 32.304 2.765 53.928 ;
     RECT  2.677 0.192 2.819 0.312 ;
     RECT  2.819 0.288 2.833 0.312 ;
     RECT  2.833 0.288 2.867 0.552 ;
     RECT  2.867 0.528 2.917 0.552 ;
     RECT  2.704 1.728 3.233 31.272 ;
     RECT  3.233 3.408 3.413 31.272 ;
     RECT  3.413 5.424 3.485 31.272 ;
     RECT  3.233 1.728 3.697 1.8 ;
     RECT  3.413 3.408 3.773 4.2 ;
     RECT  3.697 1.152 3.881 1.8 ;
     RECT  2.765 48.912 4.097 53.928 ;
     RECT  3.881 1.152 4.259 1.752 ;
     RECT  3.773 3.408 4.597 4.104 ;
     RECT  3.485 5.472 4.597 31.272 ;
     RECT  4.597 2.88 4.741 4.104 ;
     RECT  4.597 5.136 4.741 31.272 ;
     RECT  4.259 1.728 5.108 1.752 ;
     RECT  4.741 2.88 5.108 31.272 ;
     RECT  2.765 32.304 5.108 47.88 ;
     RECT  4.097 48.912 5.108 53.592 ;
     RECT  5.108 1.728 5.212 54.012 ;
     RECT  5.212 1.728 5.404 53.742 ;
     RECT  5.404 1.728 5.411 31.272 ;
     RECT  5.389 0.192 5.603 0.216 ;
     RECT  5.404 50.88 5.717 52.536 ;
     RECT  5.404 49.344 6.761 49.56 ;
     RECT  5.411 1.728 7.669 1.752 ;
     RECT  5.411 2.88 7.669 31.272 ;
     RECT  7.669 1.728 7.808 31.272 ;
     RECT  5.404 32.304 7.808 47.88 ;
     RECT  6.761 49.344 7.808 49.368 ;
     RECT  5.717 50.88 7.808 51.768 ;
     RECT  5.404 53.568 7.808 53.592 ;
     RECT  7.808 1.728 7.912 54.012 ;
     RECT  7.912 1.728 8.104 53.742 ;
     RECT  8.104 1.728 8.561 31.272 ;
     RECT  8.561 13.872 8.633 17.208 ;
     RECT  8.633 13.872 8.705 15 ;
     RECT  8.705 13.92 8.885 15 ;
     RECT  8.885 14.112 9.029 15 ;
     RECT  8.561 1.728 9.137 12.888 ;
     RECT  8.104 50.88 9.137 51.72 ;
     RECT  9.137 1.728 9.317 12.792 ;
     RECT  9.317 1.728 9.461 12.6 ;
     RECT  8.633 16.272 9.533 17.208 ;
     RECT  8.54 0.144 9.587 0.168 ;
     RECT  9.029 14.112 10.033 14.712 ;
     RECT  9.461 1.728 10.429 1.752 ;
     RECT  9.461 2.736 10.429 12.6 ;
     RECT  10.261 0.192 10.451 0.552 ;
     RECT  10.429 1.728 10.508 12.6 ;
     RECT  10.033 14.112 10.508 14.952 ;
     RECT  9.533 16.368 10.508 17.208 ;
     RECT  8.561 18.432 10.508 31.272 ;
     RECT  8.104 32.304 10.508 47.88 ;
     RECT  8.104 49.344 10.508 49.368 ;
     RECT  9.137 51.696 10.508 51.72 ;
     RECT  10.508 1.728 10.612 54.012 ;
     RECT  10.451 0.288 10.757 0.552 ;
     RECT  10.612 1.728 10.804 53.742 ;
     RECT  10.804 17.184 10.937 17.208 ;
     RECT  10.804 19.056 11.441 31.272 ;
     RECT  11.441 19.536 11.729 31.272 ;
     RECT  11.729 21.12 11.909 31.272 ;
     RECT  11.909 21.408 11.945 31.272 ;
     RECT  11.945 21.696 11.981 31.272 ;
     RECT  11.981 26.352 12.017 31.272 ;
     RECT  11.729 19.536 12.161 20.136 ;
     RECT  12.161 20.112 12.233 20.136 ;
     RECT  10.757 0.288 12.517 0.312 ;
     RECT  10.804 1.728 12.517 12.552 ;
     RECT  12.517 0.288 12.659 12.552 ;
     RECT  12.659 1.728 13.093 12.552 ;
     RECT  13.093 1.728 13.208 12.888 ;
     RECT  10.804 14.112 13.208 14.136 ;
     RECT  11.981 22.224 13.208 23.544 ;
     RECT  12.017 26.496 13.208 31.272 ;
     RECT  10.804 32.304 13.208 47.88 ;
     RECT  10.804 49.344 13.208 49.368 ;
     RECT  10.804 51.696 13.208 51.72 ;
     RECT  13.208 1.728 13.312 54.012 ;
     RECT  13.312 1.728 13.504 53.742 ;
     RECT  12.659 0.288 13.525 0.552 ;
     RECT  13.525 0.192 13.817 0.552 ;
     RECT  13.817 0.192 14.156 0.312 ;
     RECT  14.156 0.144 14.243 0.312 ;
     RECT  14.243 0.288 14.339 0.312 ;
     RECT  13.504 1.728 14.645 14.136 ;
     RECT  14.645 12.864 14.821 14.136 ;
     RECT  13.504 49.344 14.821 49.368 ;
     RECT  14.497 21.168 14.825 21.192 ;
     RECT  13.504 26.496 14.861 31.272 ;
     RECT  13.504 32.304 14.861 47.88 ;
     RECT  14.821 49.248 14.861 49.368 ;
     RECT  14.821 12.864 14.933 14.904 ;
     RECT  14.645 1.728 15.185 11.64 ;
     RECT  15.109 55.296 15.193 55.32 ;
     RECT  15.185 1.824 15.221 11.64 ;
     RECT  15.308 0.144 15.397 0.168 ;
     RECT  15.397 0.144 15.587 0.312 ;
     RECT  15.221 2.148 15.908 11.64 ;
     RECT  14.933 12.864 15.908 14.136 ;
     RECT  14.861 26.592 15.908 31.176 ;
     RECT  14.861 32.304 15.908 47.736 ;
     RECT  14.861 49.248 15.908 49.272 ;
     RECT  15.908 2.148 16.012 54.012 ;
     RECT  15.587 0.192 16.117 0.312 ;
     RECT  16.012 2.148 16.204 53.742 ;
     RECT  16.117 0.192 16.213 0.408 ;
     RECT  16.204 13.872 16.301 14.424 ;
     RECT  16.213 0.192 16.499 0.504 ;
     RECT  16.204 26.496 16.517 31.176 ;
     RECT  16.499 0.192 16.547 0.216 ;
     RECT  16.204 2.148 16.597 11.448 ;
     RECT  16.597 1.728 16.805 11.448 ;
     RECT  16.805 1.728 16.841 1.8 ;
     RECT  16.517 27.6 16.985 31.176 ;
     RECT  16.805 2.784 17.021 11.448 ;
     RECT  16.985 27.6 17.129 29.352 ;
     RECT  17.129 27.6 17.201 29.016 ;
     RECT  16.204 32.304 17.201 47.736 ;
     RECT  16.204 15.696 17.341 15.912 ;
     RECT  16.301 13.872 17.449 14.136 ;
     RECT  16.841 1.728 17.453 1.752 ;
     RECT  17.341 15.456 17.665 15.912 ;
     RECT  17.521 16.896 17.665 16.92 ;
     RECT  17.021 2.832 18.305 11.4 ;
     RECT  18.313 0.576 18.397 0.6 ;
     RECT  17.449 13.872 18.469 14.28 ;
     RECT  18.305 2.256 18.565 11.4 ;
     RECT  18.565 2.016 18.608 11.4 ;
     RECT  18.469 13.104 18.608 14.28 ;
     RECT  17.665 15.456 18.608 16.92 ;
     RECT  16.517 26.496 18.608 26.52 ;
     RECT  17.201 27.6 18.608 28.44 ;
     RECT  16.985 30.576 18.608 31.176 ;
     RECT  17.201 33.12 18.608 47.736 ;
     RECT  16.204 49.248 18.608 49.272 ;
     RECT  18.608 2.016 18.712 54.012 ;
     RECT  18.712 2.016 18.755 53.742 ;
     RECT  18.755 2.16 18.904 53.742 ;
     RECT  18.904 2.16 19.261 10.68 ;
     RECT  18.421 0.144 19.501 0.552 ;
     RECT  18.904 16.56 19.937 16.92 ;
     RECT  19.501 0.144 20.405 0.6 ;
     RECT  20.405 0.144 20.819 0.312 ;
     RECT  18.904 14.112 21.085 14.136 ;
     RECT  19.261 2.256 21.149 10.68 ;
     RECT  21.149 2.256 21.308 10.872 ;
     RECT  21.085 14.112 21.308 14.952 ;
     RECT  19.937 16.896 21.308 16.92 ;
     RECT  18.904 26.496 21.308 26.52 ;
     RECT  18.904 27.6 21.308 28.44 ;
     RECT  18.904 30.576 21.308 31.176 ;
     RECT  18.904 33.12 21.308 47.736 ;
     RECT  18.904 49.248 21.308 49.272 ;
     RECT  21.308 2.148 21.412 54.012 ;
     RECT  21.412 2.148 21.604 53.742 ;
     RECT  21.604 49.248 21.701 49.368 ;
     RECT  20.819 0.192 21.73 0.312 ;
     RECT  21.73 0.192 21.875 0.36 ;
     RECT  21.875 0.192 21.971 0.216 ;
     RECT  21.604 2.148 22.013 11.496 ;
     RECT  21.604 18.768 22.097 18.792 ;
     RECT  21.604 13.104 22.393 13.128 ;
     RECT  21.604 33.12 22.565 47.736 ;
     RECT  22.013 1.728 22.705 11.496 ;
     RECT  22.705 1.728 22.789 12.024 ;
     RECT  21.604 20.352 22.813 21.24 ;
     RECT  21.701 49.344 22.813 49.368 ;
     RECT  22.789 1.728 22.853 11.496 ;
     RECT  22.813 49.248 22.853 49.368 ;
     RECT  22.813 20.352 22.957 21.768 ;
     RECT  23.065 0.288 23.269 0.312 ;
     RECT  23.269 0.288 23.365 0.552 ;
     RECT  23.365 0.192 23.501 0.552 ;
     RECT  23.501 0.192 23.507 0.408 ;
     RECT  21.604 26.496 23.893 26.52 ;
     RECT  22.853 1.728 24.008 11.448 ;
     RECT  23.713 13.104 24.008 13.128 ;
     RECT  21.604 14.112 24.008 14.136 ;
     RECT  22.957 20.352 24.008 22.344 ;
     RECT  23.893 26.496 24.008 26.616 ;
     RECT  21.604 27.6 24.008 28.44 ;
     RECT  21.604 30.576 24.008 31.176 ;
     RECT  22.565 33.12 24.008 47.448 ;
     RECT  22.853 49.248 24.008 49.272 ;
     RECT  24.008 1.728 24.112 54.012 ;
     RECT  24.112 1.728 24.304 53.742 ;
     RECT  24.304 21.408 24.401 21.768 ;
     RECT  23.507 0.288 24.419 0.408 ;
     RECT  24.304 12.528 24.445 14.856 ;
     RECT  24.304 1.728 24.473 11.448 ;
     RECT  24.473 1.728 24.509 10.68 ;
     RECT  24.419 0.384 24.515 0.408 ;
     RECT  24.401 21.504 24.617 21.768 ;
     RECT  24.509 1.776 24.797 10.68 ;
     RECT  24.304 33.12 24.797 47.448 ;
     RECT  24.445 13.104 25.013 14.856 ;
     RECT  24.304 26.352 25.193 29.064 ;
     RECT  25.013 13.68 25.297 14.856 ;
     RECT  25.193 27.456 25.301 29.064 ;
     RECT  24.304 49.248 25.301 49.272 ;
     RECT  25.301 27.696 25.337 29.064 ;
     RECT  24.797 33.12 25.481 46.584 ;
     RECT  24.304 30.576 25.513 31.56 ;
     RECT  25.513 30.576 25.585 31.752 ;
     RECT  24.304 23.088 25.765 23.64 ;
     RECT  25.585 30.576 25.873 31.8 ;
     RECT  25.873 30.048 25.981 31.8 ;
     RECT  25.481 33.12 25.981 46.056 ;
     RECT  24.797 2.256 26.005 10.68 ;
     RECT  25.765 23.088 26.053 23.976 ;
     RECT  25.765 12.528 26.101 12.552 ;
     RECT  25.297 13.68 26.101 15.432 ;
     RECT  25.981 30.048 26.125 46.056 ;
     RECT  25.388 0.288 26.333 0.312 ;
     RECT  26.333 0.288 26.417 0.552 ;
     RECT  26.417 0.288 26.581 0.312 ;
     RECT  26.005 2.208 26.708 10.68 ;
     RECT  26.101 12.528 26.708 15.432 ;
     RECT  25.981 18.768 26.708 18.792 ;
     RECT  24.617 21.744 26.708 21.768 ;
     RECT  26.053 23.088 26.708 24.408 ;
     RECT  25.193 26.352 26.708 26.376 ;
     RECT  25.337 27.696 26.708 28.44 ;
     RECT  26.125 29.856 26.708 46.056 ;
     RECT  26.708 2.148 26.812 54.012 ;
     RECT  26.812 2.148 26.869 53.742 ;
     RECT  26.581 0.192 26.953 0.312 ;
     RECT  26.869 1.728 27.004 53.742 ;
     RECT  27.004 1.728 27.281 10.68 ;
     RECT  27.004 23.952 27.317 25.272 ;
     RECT  26.953 0.144 27.443 0.312 ;
     RECT  27.004 32.736 27.677 45.96 ;
     RECT  27.004 13.68 27.713 14.904 ;
     RECT  27.317 24.384 27.749 25.272 ;
     RECT  27.281 2.208 27.821 10.68 ;
     RECT  27.004 29.568 27.893 31.176 ;
     RECT  27.677 32.736 28.073 43.56 ;
     RECT  27.677 44.976 28.073 45.96 ;
     RECT  28.073 45.936 28.217 45.96 ;
     RECT  27.893 29.568 28.325 30.792 ;
     RECT  28.073 32.736 28.361 41.064 ;
     RECT  27.749 24.384 28.453 24.408 ;
     RECT  27.004 26.304 28.537 28.44 ;
     RECT  27.443 0.144 28.741 0.168 ;
     RECT  27.004 22.752 28.789 22.776 ;
     RECT  28.453 23.904 28.789 24.408 ;
     RECT  27.821 2.208 28.897 10.44 ;
     RECT  28.789 22.752 29.084 24.408 ;
     RECT  28.537 25.488 29.084 28.44 ;
     RECT  28.741 0.144 29.125 0.312 ;
     RECT  27.713 14.112 29.269 14.904 ;
     RECT  28.325 30.048 29.365 30.792 ;
     RECT  28.897 2.208 29.408 10.68 ;
     RECT  29.269 14.112 29.408 15.48 ;
     RECT  27.004 16.56 29.408 16.584 ;
     RECT  29.084 22.752 29.408 28.44 ;
     RECT  29.365 30.048 29.408 31.128 ;
     RECT  28.361 32.736 29.408 40.632 ;
     RECT  28.073 42.048 29.408 43.56 ;
     RECT  29.408 2.148 29.512 54.012 ;
     RECT  29.125 0.144 29.513 0.552 ;
     RECT  29.512 2.148 29.704 53.742 ;
     RECT  29.704 22.752 29.765 31.128 ;
     RECT  29.704 15.408 29.801 15.48 ;
     RECT  29.704 32.736 29.837 40.632 ;
     RECT  29.704 14.112 29.845 14.28 ;
     RECT  29.765 22.752 29.873 25.512 ;
     RECT  29.704 17.664 29.987 17.688 ;
     RECT  29.873 25.152 30.089 25.512 ;
     RECT  29.837 32.736 30.125 40.152 ;
     RECT  29.513 0.144 30.275 0.312 ;
     RECT  29.704 2.148 30.325 10.68 ;
     RECT  30.325 1.728 30.665 10.68 ;
     RECT  30.089 25.152 30.701 25.176 ;
     RECT  30.275 0.288 30.707 0.312 ;
     RECT  30.665 2.208 30.709 10.68 ;
     RECT  29.765 26.592 30.769 31.128 ;
     RECT  29.704 16.56 30.773 16.584 ;
     RECT  30.125 32.736 30.809 39.864 ;
     RECT  30.709 2.208 30.917 10.824 ;
     RECT  29.801 15.408 30.989 15.432 ;
     RECT  30.809 37.392 31.061 39.864 ;
     RECT  29.845 14.112 31.129 14.136 ;
     RECT  31.772 0.288 31.957 0.312 ;
     RECT  31.957 0.192 32.099 0.312 ;
     RECT  30.917 2.208 32.108 10.68 ;
     RECT  31.129 14.112 32.108 14.856 ;
     RECT  31.381 15.984 32.108 16.008 ;
     RECT  31.813 17.088 32.108 17.112 ;
     RECT  29.873 22.752 32.108 23.928 ;
     RECT  30.769 26.592 32.108 31.176 ;
     RECT  30.809 32.736 32.108 36.312 ;
     RECT  31.061 37.392 32.108 39.384 ;
     RECT  32.108 2.148 32.212 54.012 ;
     RECT  32.212 2.148 32.404 53.742 ;
     RECT  32.404 2.148 32.417 10.824 ;
     RECT  32.417 2.016 32.501 10.824 ;
     RECT  32.404 26.592 32.537 28.536 ;
     RECT  32.537 26.592 32.645 28.488 ;
     RECT  32.404 18.816 32.819 18.936 ;
     RECT  32.645 26.592 33.077 28.44 ;
     RECT  32.404 15.984 33.085 16.584 ;
     RECT  32.099 0.288 33.116 0.312 ;
     RECT  32.819 18.816 33.149 18.84 ;
     RECT  32.501 2.208 33.401 10.824 ;
     RECT  33.116 0.144 33.589 0.312 ;
     RECT  32.404 29.52 33.617 36.312 ;
     RECT  33.617 29.568 33.689 36.312 ;
     RECT  33.589 0.144 33.779 0.552 ;
     RECT  33.085 16.56 33.925 16.584 ;
     RECT  32.404 20.64 33.937 20.664 ;
     RECT  33.401 2.208 34.001 10.68 ;
     RECT  34.001 1.728 34.085 10.68 ;
     RECT  33.779 0.528 34.337 0.552 ;
     RECT  34.213 18.816 34.441 18.84 ;
     RECT  33.937 19.968 34.441 20.664 ;
     RECT  32.404 17.664 34.453 17.688 ;
     RECT  34.441 18.816 34.453 20.664 ;
     RECT  34.453 17.664 34.549 20.664 ;
     RECT  34.549 17.664 34.585 21.144 ;
     RECT  34.085 2.016 34.808 10.68 ;
     RECT  32.404 14.112 34.808 14.136 ;
     RECT  33.925 16.56 34.808 16.632 ;
     RECT  34.585 17.664 34.808 21.672 ;
     RECT  32.404 22.752 34.808 23.928 ;
     RECT  33.077 26.592 34.808 26.616 ;
     RECT  33.077 27.6 34.808 28.44 ;
     RECT  33.689 29.808 34.808 36.312 ;
     RECT  32.404 37.392 34.808 38.424 ;
     RECT  34.808 2.016 34.912 54.012 ;
     RECT  34.912 2.016 35.057 53.742 ;
     RECT  34.789 0.288 35.089 0.408 ;
     RECT  35.057 2.256 35.104 53.742 ;
     RECT  35.104 17.136 35.201 23.928 ;
     RECT  35.201 17.136 35.353 18.264 ;
     RECT  35.089 0.144 35.365 0.408 ;
     RECT  35.365 0.144 35.885 0.552 ;
     RECT  35.885 0.144 35.891 0.312 ;
     RECT  35.104 31.104 36.029 31.704 ;
     RECT  35.104 2.256 36.085 10.68 ;
     RECT  35.201 19.536 36.245 23.928 ;
     RECT  36.085 2.16 36.353 10.68 ;
     RECT  36.245 19.584 36.353 23.928 ;
     RECT  35.104 32.736 36.353 36.312 ;
     RECT  35.891 0.192 36.956 0.312 ;
     RECT  36.353 2.256 37.508 10.68 ;
     RECT  35.104 14.112 37.508 14.136 ;
     RECT  35.353 17.664 37.508 18.264 ;
     RECT  36.353 19.584 37.508 23.88 ;
     RECT  35.104 26.592 37.508 26.616 ;
     RECT  35.104 27.6 37.508 28.44 ;
     RECT  35.104 29.808 37.508 29.832 ;
     RECT  36.029 31.104 37.508 31.128 ;
     RECT  36.353 32.736 37.508 32.76 ;
     RECT  36.353 34.08 37.508 36.312 ;
     RECT  35.104 37.392 37.508 38.424 ;
     RECT  36.956 0.144 37.573 0.312 ;
     RECT  37.508 2.148 37.612 54.012 ;
     RECT  37.612 2.148 37.628 53.742 ;
     RECT  37.628 2.016 37.804 53.742 ;
     RECT  37.804 2.016 38.245 10.632 ;
     RECT  37.804 19.584 38.297 20.04 ;
     RECT  38.297 19.584 38.405 19.608 ;
     RECT  37.804 21.12 38.627 21.768 ;
     RECT  37.573 0.144 38.723 0.36 ;
     RECT  38.627 21.12 38.729 21.672 ;
     RECT  38.729 21.12 38.771 21.192 ;
     RECT  37.804 26.496 38.801 26.616 ;
     RECT  37.804 29.808 38.801 29.928 ;
     RECT  37.804 37.296 38.801 38.424 ;
     RECT  37.804 17.952 38.819 18.312 ;
     RECT  37.804 35.28 38.945 36.312 ;
     RECT  38.245 1.728 39.265 10.632 ;
     RECT  38.771 21.12 39.373 21.144 ;
     RECT  39.265 1.68 39.491 10.632 ;
     RECT  38.723 0.144 39.779 0.216 ;
     RECT  39.491 2.148 40.208 10.632 ;
     RECT  37.804 14.112 40.208 14.136 ;
     RECT  38.819 17.952 40.208 17.976 ;
     RECT  39.373 20.544 40.208 21.144 ;
     RECT  38.801 26.592 40.208 26.616 ;
     RECT  37.804 27.6 40.208 28.44 ;
     RECT  38.801 29.808 40.208 29.832 ;
     RECT  37.804 31.104 40.208 31.128 ;
     RECT  37.804 32.736 40.208 32.76 ;
     RECT  38.945 35.28 40.208 36.264 ;
     RECT  38.801 37.392 40.208 38.424 ;
     RECT  39.973 0.288 40.259 0.36 ;
     RECT  40.208 2.148 40.312 54.012 ;
     RECT  40.259 0.336 40.451 0.36 ;
     RECT  40.312 2.148 40.504 53.976 ;
     RECT  40.504 52.464 40.643 52.488 ;
     RECT  40.504 17.952 40.739 17.976 ;
     RECT  40.597 1.728 40.961 1.752 ;
     RECT  40.504 53.952 41.116 53.976 ;
     RECT  41.228 0.144 41.315 0.168 ;
     RECT  40.504 2.736 41.653 10.632 ;
     RECT  41.653 2.496 41.965 10.632 ;
     RECT  41.965 1.728 42.433 10.632 ;
     RECT  42.433 1.728 42.908 10.824 ;
     RECT  40.504 14.112 42.908 14.136 ;
     RECT  40.504 15.984 42.908 16.008 ;
     RECT  40.504 26.592 42.908 26.616 ;
     RECT  40.504 27.6 42.908 28.44 ;
     RECT  40.504 29.808 42.908 29.832 ;
     RECT  40.504 31.104 42.908 31.128 ;
     RECT  40.504 32.736 42.908 32.76 ;
     RECT  40.504 37.392 42.908 37.416 ;
     RECT  41.965 51.888 42.908 51.912 ;
     RECT  42.908 1.728 43.012 54.012 ;
     RECT  42.757 0.288 43.093 0.312 ;
     RECT  43.093 0.288 43.189 0.408 ;
     RECT  43.012 1.728 43.204 53.742 ;
     RECT  43.189 0.192 43.331 0.408 ;
     RECT  43.331 0.288 43.489 0.312 ;
     RECT  43.204 1.728 43.841 10.728 ;
     RECT  43.841 1.776 44.381 10.728 ;
     RECT  44.381 1.776 44.561 10.344 ;
     RECT  45.133 1.728 45.608 1.752 ;
     RECT  44.561 2.88 45.608 10.344 ;
     RECT  43.204 14.112 45.608 14.136 ;
     RECT  43.204 15.984 45.608 16.008 ;
     RECT  43.204 26.592 45.608 26.616 ;
     RECT  43.204 27.6 45.608 28.44 ;
     RECT  43.204 29.808 45.608 29.832 ;
     RECT  43.204 32.736 45.608 32.76 ;
     RECT  43.204 37.392 45.608 37.416 ;
     RECT  45.608 1.728 45.712 54.012 ;
     RECT  45.589 0.288 45.781 0.312 ;
     RECT  45.781 0.288 45.889 0.408 ;
     RECT  45.712 1.728 45.904 53.742 ;
     RECT  45.889 0.144 46.163 0.408 ;
     RECT  45.904 2.784 46.541 10.776 ;
     RECT  45.904 29.808 46.613 29.832 ;
     RECT  45.904 26.496 46.793 26.616 ;
     RECT  45.904 1.728 46.981 1.752 ;
     RECT  46.981 1.152 47.123 1.752 ;
     RECT  47.123 1.728 47.141 1.752 ;
     RECT  46.541 2.784 47.141 10.344 ;
     RECT  47.141 1.728 47.189 10.344 ;
     RECT  47.189 1.824 47.225 10.344 ;
     RECT  46.163 0.144 47.507 0.168 ;
     RECT  47.893 11.424 47.977 11.448 ;
     RECT  47.225 2.688 48.013 10.344 ;
     RECT  47.977 11.424 48.013 12.024 ;
     RECT  48.049 0.288 48.181 0.312 ;
     RECT  48.181 0.288 48.193 0.408 ;
     RECT  48.013 2.688 48.308 12.024 ;
     RECT  45.904 14.112 48.308 14.136 ;
     RECT  45.904 15.984 48.308 16.008 ;
     RECT  46.793 26.592 48.308 26.616 ;
     RECT  45.904 27.6 48.308 28.44 ;
     RECT  48.308 2.148 48.412 54.012 ;
     RECT  48.412 2.418 48.604 53.742 ;
     RECT  48.193 0.288 48.709 1.176 ;
     RECT  48.709 0.192 48.805 1.176 ;
     RECT  48.805 0.144 49.043 1.176 ;
     RECT  49.043 0.192 49.089 1.176 ;
     RECT  48.604 3.12 49.133 13.08 ;
     RECT  48.604 30.24 49.285 30.264 ;
     RECT  49.445 1.728 49.529 1.752 ;
     RECT  49.133 3.12 49.916 12.504 ;
     RECT  49.089 0.192 50.195 0.216 ;
     RECT  49.916 2.88 50.425 12.504 ;
     RECT  50.425 2.88 50.641 12.84 ;
     RECT  50.641 2.832 50.725 12.84 ;
     RECT  50.725 2.256 50.821 12.84 ;
     RECT  50.821 1.728 51.008 12.84 ;
     RECT  48.604 14.112 51.008 14.136 ;
     RECT  48.604 15.984 51.008 16.008 ;
     RECT  48.604 26.592 51.008 26.616 ;
     RECT  48.604 27.6 51.008 28.44 ;
     RECT  50.869 0.288 51.059 0.312 ;
     RECT  51.008 1.728 51.112 54.012 ;
     RECT  51.112 1.728 51.251 53.742 ;
     RECT  51.251 2.208 51.304 53.742 ;
     RECT  51.397 1.152 51.539 1.176 ;
     RECT  51.304 27.6 51.545 28.44 ;
     RECT  51.545 27.6 52.265 27.624 ;
     RECT  51.304 2.208 52.307 14.52 ;
     RECT  51.304 16.224 52.307 16.248 ;
     RECT  52.307 2.208 52.348 14.136 ;
     RECT  52.297 0.288 52.499 0.312 ;
     RECT  52.348 2.208 52.553 13.08 ;
     RECT  52.513 31.344 52.739 31.368 ;
     RECT  52.693 0.528 53.093 0.552 ;
     RECT  52.553 2.208 53.708 6.936 ;
     RECT  52.553 8.208 53.708 13.08 ;
     RECT  52.348 14.112 53.708 14.136 ;
     RECT  51.304 26.592 53.708 26.616 ;
     RECT  53.708 2.148 53.812 54.012 ;
     RECT  53.812 2.148 53.941 53.742 ;
     RECT  53.941 2.016 54.004 53.742 ;
     RECT  54.004 6.816 54.029 6.84 ;
     RECT  54.004 12 54.065 12.024 ;
     RECT  54.004 2.016 54.101 2.04 ;
     RECT  53.749 0.192 54.131 0.216 ;
     RECT  54.004 4.56 54.145 4.584 ;
    LAYER M5 ;
     RECT  8.592 0.133 9.576 0.144 ;
     RECT  14.208 0.133 14.232 0.144 ;
     RECT  15.36 0.133 15.576 0.144 ;
     RECT  19.008 0.133 20.808 0.144 ;
     RECT  27.36 0.133 30.264 0.144 ;
     RECT  33.168 0.133 33.768 0.144 ;
     RECT  35.472 0.133 35.88 0.144 ;
     RECT  37.008 0.133 37.032 0.144 ;
     RECT  38.352 0.133 38.376 0.144 ;
     RECT  39.36 0.133 39.768 0.144 ;
     RECT  41.28 0.133 41.304 0.144 ;
     RECT  46.32 0.133 46.344 0.144 ;
     RECT  47.472 0.133 47.496 0.144 ;
     RECT  49.008 0.133 49.032 0.144 ;
     RECT  2.304 0.144 53.976 0.181 ;
     RECT  2.304 0.181 54.12 1.763 ;
     RECT  2.4 1.763 54.12 3.443 ;
     RECT  4.752 3.443 54.12 4.019 ;
     RECT  4.752 4.019 44.52 4.547 ;
     RECT  45.6 4.019 54.12 4.595 ;
     RECT  5.1 4.547 44.52 5.123 ;
     RECT  45.6 4.595 54.012 5.123 ;
     RECT  5.1 5.123 41.688 5.171 ;
     RECT  5.1 5.171 41.544 5.219 ;
     RECT  45.6 5.123 48.984 5.267 ;
     RECT  42.672 5.123 44.52 5.509 ;
     RECT  45.6 5.267 48.612 5.509 ;
     RECT  42.672 5.509 48.612 5.555 ;
     RECT  49.968 5.123 54.012 5.699 ;
     RECT  5.1 5.219 41.112 5.749 ;
     RECT  2.4 3.443 3.144 6.037 ;
     RECT  4.56 5.749 41.112 6.037 ;
     RECT  42.768 5.555 48.612 6.227 ;
     RECT  45.072 6.227 48.612 6.323 ;
     RECT  45.12 6.323 48.612 6.371 ;
     RECT  2.4 6.037 41.112 6.373 ;
     RECT  49.968 5.699 51.864 6.419 ;
     RECT  49.968 6.419 51.672 6.707 ;
     RECT  2.208 6.373 41.112 6.805 ;
     RECT  53.184 5.699 54.012 6.947 ;
     RECT  2.208 6.805 41.592 7.045 ;
     RECT  42.768 6.227 44.088 7.045 ;
     RECT  45.12 6.371 46.008 7.187 ;
     RECT  2.208 7.045 44.088 7.475 ;
     RECT  2.208 7.475 43.944 7.859 ;
     RECT  2.208 7.859 41.304 8.147 ;
     RECT  45.312 7.187 46.008 8.149 ;
     RECT  46.992 6.371 48.612 8.149 ;
     RECT  45.312 8.149 48.612 8.437 ;
     RECT  49.968 6.707 51.528 8.437 ;
     RECT  53.52 6.947 54.012 8.437 ;
     RECT  45.312 8.437 51.528 8.675 ;
     RECT  42.432 7.859 43.944 8.723 ;
     RECT  0.288 7.621 0.312 8.821 ;
     RECT  45.312 8.675 51.312 8.963 ;
     RECT  0.192 8.821 0.312 9.011 ;
     RECT  42.432 8.723 43.212 9.061 ;
     RECT  45.312 8.963 46.92 9.155 ;
     RECT  2.208 8.147 41.112 9.493 ;
     RECT  42.144 9.061 43.212 9.493 ;
     RECT  2.208 9.493 43.212 9.541 ;
     RECT  1.92 9.541 43.212 9.587 ;
     RECT  48.3 8.963 51.312 9.683 ;
     RECT  18 9.587 43.212 9.779 ;
     RECT  18 9.779 19.416 10.115 ;
     RECT  48.3 9.683 49.272 10.117 ;
     RECT  1.92 9.587 17.016 10.163 ;
     RECT  20.496 9.779 43.212 10.307 ;
     RECT  18.192 10.115 19.416 10.355 ;
     RECT  20.928 10.307 43.212 10.355 ;
     RECT  45.312 9.155 46.776 10.355 ;
     RECT  2.208 10.163 17.016 10.403 ;
     RECT  18.24 10.355 19.416 10.451 ;
     RECT  2.208 10.403 5.928 10.547 ;
     RECT  18.24 10.451 18.912 10.595 ;
     RECT  21.168 10.355 43.212 10.595 ;
     RECT  21.168 10.595 40.728 10.883 ;
     RECT  7.632 10.403 17.016 10.931 ;
     RECT  7.632 10.931 16.728 11.123 ;
     RECT  7.632 11.123 16.392 11.411 ;
     RECT  7.8 11.411 16.212 11.459 ;
     RECT  21.3 10.883 40.728 11.459 ;
     RECT  47.904 10.117 49.272 11.459 ;
     RECT  1.152 11.077 1.176 11.461 ;
     RECT  13.056 11.459 16.212 11.603 ;
     RECT  2.304 10.547 5.928 11.651 ;
     RECT  2.304 11.651 5.88 11.699 ;
     RECT  0.288 11.461 1.176 11.843 ;
     RECT  3.744 11.699 5.88 11.987 ;
     RECT  2.304 11.699 2.712 12.035 ;
     RECT  7.8 11.459 11.496 12.035 ;
     RECT  21.3 11.459 22.776 12.035 ;
     RECT  9.456 12.035 10.812 12.083 ;
     RECT  3.744 11.987 3.768 12.179 ;
     RECT  4.848 11.987 5.88 12.179 ;
     RECT  9.504 12.083 10.812 12.179 ;
     RECT  5.1 12.179 5.88 12.515 ;
     RECT  50.688 9.683 51.312 12.755 ;
     RECT  5.1 12.515 5.64 12.803 ;
     RECT  1.152 11.843 1.176 12.805 ;
     RECT  1.152 12.805 1.272 13.091 ;
     RECT  52.704 8.437 54.012 13.091 ;
     RECT  13.2 11.603 16.212 13.139 ;
     RECT  18.48 10.595 18.912 13.139 ;
     RECT  21.3 12.035 22.344 13.139 ;
     RECT  23.76 11.459 40.728 13.139 ;
     RECT  50.88 12.755 51.312 13.141 ;
     RECT  52.704 13.091 52.728 13.141 ;
     RECT  13.2 13.139 13.608 13.187 ;
     RECT  24 13.139 40.728 13.715 ;
     RECT  25.296 13.715 40.728 14.867 ;
     RECT  25.584 14.867 40.728 15.443 ;
     RECT  26.592 15.443 40.728 16.019 ;
     RECT  50.88 13.141 52.728 16.019 ;
     RECT  51 16.019 52.728 16.259 ;
     RECT  26.592 16.019 30.744 16.595 ;
     RECT  31.824 16.019 40.728 17.123 ;
     RECT  29.4 16.595 29.976 17.699 ;
     RECT  32.1 17.123 40.728 17.699 ;
     RECT  34.032 17.699 40.728 17.987 ;
     RECT  32.1 17.699 32.856 18.851 ;
     RECT  32.1 18.851 32.808 18.947 ;
     RECT  34.032 17.987 40.632 20.579 ;
     RECT  34.56 20.579 35.832 21.155 ;
     RECT  37.008 20.579 38.76 21.203 ;
     RECT  37.008 21.203 38.712 21.635 ;
     RECT  2.4 12.035 2.712 21.637 ;
     RECT  34.608 21.155 35.832 21.683 ;
     RECT  37.5 21.635 38.712 21.683 ;
     RECT  7.8 12.035 8.112 21.733 ;
     RECT  2.304 21.637 2.712 21.779 ;
     RECT  37.5 21.683 38.616 21.779 ;
     RECT  6.864 21.733 8.112 22.163 ;
     RECT  34.8 21.683 35.832 22.259 ;
     RECT  26.592 16.595 27.624 22.741 ;
     RECT  29.4 17.699 29.712 23.269 ;
     RECT  28.8 23.269 29.712 23.317 ;
     RECT  7.8 22.163 8.112 23.365 ;
     RECT  2.4 21.779 2.712 23.797 ;
     RECT  28.8 23.317 30.456 23.845 ;
     RECT  32.1 18.947 32.412 23.845 ;
     RECT  26.592 22.741 27.672 23.893 ;
     RECT  28.8 23.845 32.412 23.893 ;
     RECT  6.864 23.365 8.112 23.939 ;
     RECT  2.304 23.797 2.712 24.323 ;
     RECT  0.288 24.421 0.312 24.659 ;
     RECT  7.8 23.939 8.112 25.429 ;
     RECT  6.96 25.429 8.112 25.525 ;
     RECT  6.864 25.525 8.112 25.667 ;
     RECT  0.288 26.053 0.312 26.291 ;
     RECT  24 13.715 24.312 26.485 ;
     RECT  23.904 26.485 24.312 26.627 ;
     RECT  48.3 11.459 49.272 30.275 ;
     RECT  1.104 31.093 1.128 31.331 ;
     RECT  52.704 16.259 52.728 31.379 ;
     RECT  24 26.627 24.312 34.597 ;
     RECT  23.904 34.597 24.312 34.739 ;
     RECT  0.72 36.085 0.744 36.275 ;
     RECT  45.312 10.355 45.912 37.427 ;
     RECT  2.4 24.323 2.712 37.717 ;
     RECT  1.632 37.717 2.712 37.907 ;
     RECT  26.592 23.893 32.412 39.395 ;
     RECT  26.592 39.395 27.012 39.923 ;
     RECT  22.8 40.069 22.824 40.499 ;
     RECT  28.464 39.395 29.712 40.499 ;
     RECT  2.4 37.907 2.712 41.077 ;
     RECT  24 34.739 24.312 41.077 ;
     RECT  2.304 41.077 2.712 41.219 ;
     RECT  23.904 41.077 24.312 41.219 ;
     RECT  2.4 41.219 2.712 43.573 ;
     RECT  2.304 43.573 2.712 43.763 ;
     RECT  24 41.219 24.312 45.925 ;
     RECT  23.904 45.925 24.312 46.067 ;
     RECT  0.288 50.629 0.312 50.867 ;
     RECT  42 10.595 43.212 51.923 ;
     RECT  40.2 20.579 40.632 52.499 ;
     RECT  40.2 52.499 40.512 53.941 ;
     RECT  2.4 43.763 2.712 54.009 ;
     RECT  5.1 12.803 5.412 54.009 ;
     RECT  7.8 25.667 8.112 54.009 ;
     RECT  10.5 12.179 10.812 54.009 ;
     RECT  13.2 13.187 13.512 54.009 ;
     RECT  15.12 13.139 16.212 54.009 ;
     RECT  18.6 13.139 18.912 54.009 ;
     RECT  21.3 13.139 21.612 54.009 ;
     RECT  24 46.067 24.312 54.009 ;
     RECT  26.7 39.923 27.012 54.009 ;
     RECT  29.4 40.499 29.712 54.009 ;
     RECT  32.1 39.395 32.412 54.009 ;
     RECT  34.8 22.259 35.112 54.009 ;
     RECT  37.5 21.779 37.812 54.009 ;
     RECT  42.9 51.923 43.212 54.009 ;
     RECT  45.6 37.427 45.912 54.009 ;
     RECT  48.3 30.275 48.612 54.009 ;
     RECT  51 16.259 51.312 54.009 ;
     RECT  53.7 13.091 54.012 54.009 ;
     RECT  2.4 54.009 2.52 54.023 ;
     RECT  5.1 54.009 5.22 54.023 ;
     RECT  7.8 54.009 7.92 54.023 ;
     RECT  10.5 54.009 10.62 54.023 ;
     RECT  13.2 54.009 13.32 54.023 ;
     RECT  15.12 54.009 16.02 54.023 ;
     RECT  18.6 54.009 18.72 54.023 ;
     RECT  21.3 54.009 21.42 54.023 ;
     RECT  24 54.009 24.12 54.023 ;
     RECT  26.7 54.009 26.82 54.023 ;
     RECT  29.4 54.009 29.52 54.023 ;
     RECT  32.1 54.009 32.22 54.023 ;
     RECT  34.8 54.009 34.92 54.023 ;
     RECT  37.5 54.009 37.62 54.023 ;
     RECT  40.2 53.941 41.064 54.023 ;
     RECT  42.9 54.009 43.02 54.023 ;
     RECT  45.6 54.009 45.72 54.023 ;
     RECT  48.3 54.009 48.42 54.023 ;
     RECT  51 54.009 51.12 54.023 ;
     RECT  53.7 54.009 53.82 54.023 ;
     RECT  15.12 54.023 15.144 55.331 ;
     RECT  41.04 54.023 41.064 56.016 ;
  END
END dsfd_rly_536_SW
END LIBRARY
